VERSION 5.8 ;
BUSBITCHARS "[]" ;
DIVIDERCHAR "/" ;
UNITS
    DATABASE MICRONS 1000 ;
END UNITS

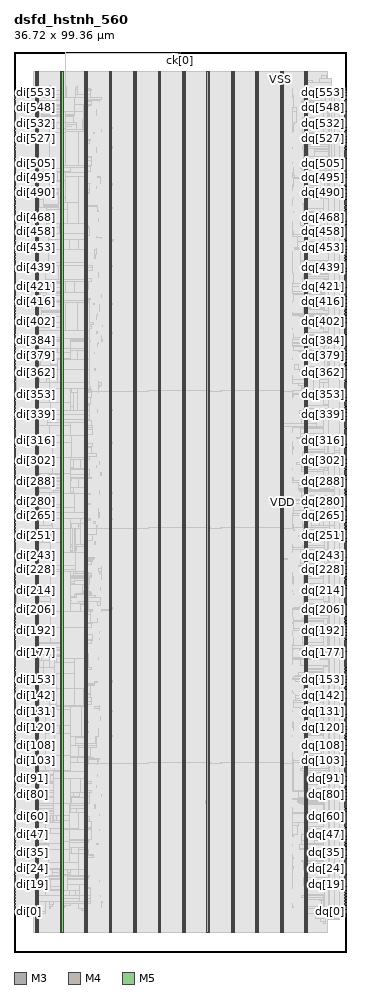
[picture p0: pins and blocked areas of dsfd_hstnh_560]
MACRO dsfd_hstnh_560
  FOREIGN dsfd_hstnh_560 0 0 ;
  CLASS BLOCK ;
  SIZE 36.72 BY 99.36 ;
  PIN ck[0]
    DIRECTION INPUT ;
    USE SIGNAL ;
    PORT
      LAYER M3 ;
        RECT  18.36 99.216 18.378 99.36 ;
    END
    PORT
      LAYER M3 ;
        RECT  18.18 99.193 18.378 99.228 ;
    END
  END ck[0]
  PIN di[0]
    DIRECTION INPUT ;
    USE SIGNAL ;
    PORT
      LAYER M4 ;
        RECT  0 4.416 0.192 4.44 ;
    END
  END di[0]
  PIN di[100]
    DIRECTION INPUT ;
    USE SIGNAL ;
    PORT
      LAYER M4 ;
        RECT  0 20.592 0.192 20.616 ;
    END
  END di[100]
  PIN di[101]
    DIRECTION INPUT ;
    USE SIGNAL ;
    PORT
      LAYER M4 ;
        RECT  0 20.784 0.192 20.808 ;
    END
  END di[101]
  PIN di[102]
    DIRECTION INPUT ;
    USE SIGNAL ;
    PORT
      LAYER M4 ;
        RECT  0 20.928 0.192 20.952 ;
    END
  END di[102]
  PIN di[103]
    DIRECTION INPUT ;
    USE SIGNAL ;
    PORT
      LAYER M4 ;
        RECT  0 21.12 0.192 21.144 ;
    END
  END di[103]
  PIN di[104]
    DIRECTION INPUT ;
    USE SIGNAL ;
    PORT
      LAYER M4 ;
        RECT  0 21.264 0.192 21.288 ;
    END
  END di[104]
  PIN di[105]
    DIRECTION INPUT ;
    USE SIGNAL ;
    PORT
      LAYER M4 ;
        RECT  0 21.408 0.192 21.432 ;
    END
  END di[105]
  PIN di[106]
    DIRECTION INPUT ;
    USE SIGNAL ;
    PORT
      LAYER M4 ;
        RECT  0 21.6 0.192 21.624 ;
    END
  END di[106]
  PIN di[107]
    DIRECTION INPUT ;
    USE SIGNAL ;
    PORT
      LAYER M4 ;
        RECT  0 21.744 0.192 21.768 ;
    END
  END di[107]
  PIN di[108]
    DIRECTION INPUT ;
    USE SIGNAL ;
    PORT
      LAYER M4 ;
        RECT  0 21.888 0.192 21.912 ;
    END
  END di[108]
  PIN di[109]
    DIRECTION INPUT ;
    USE SIGNAL ;
    PORT
      LAYER M4 ;
        RECT  0 22.08 0.192 22.104 ;
    END
  END di[109]
  PIN di[10]
    DIRECTION INPUT ;
    USE SIGNAL ;
    PORT
      LAYER M4 ;
        RECT  0 6.048 0.192 6.072 ;
    END
  END di[10]
  PIN di[110]
    DIRECTION INPUT ;
    USE SIGNAL ;
    PORT
      LAYER M4 ;
        RECT  0 22.224 0.192 22.248 ;
    END
  END di[110]
  PIN di[111]
    DIRECTION INPUT ;
    USE SIGNAL ;
    PORT
      LAYER M4 ;
        RECT  0 22.416 0.192 22.44 ;
    END
  END di[111]
  PIN di[112]
    DIRECTION INPUT ;
    USE SIGNAL ;
    PORT
      LAYER M4 ;
        RECT  0 22.56 0.192 22.584 ;
    END
  END di[112]
  PIN di[113]
    DIRECTION INPUT ;
    USE SIGNAL ;
    PORT
      LAYER M4 ;
        RECT  0 22.704 0.192 22.728 ;
    END
  END di[113]
  PIN di[114]
    DIRECTION INPUT ;
    USE SIGNAL ;
    PORT
      LAYER M4 ;
        RECT  0 22.896 0.192 22.92 ;
    END
  END di[114]
  PIN di[115]
    DIRECTION INPUT ;
    USE SIGNAL ;
    PORT
      LAYER M4 ;
        RECT  0 23.04 0.192 23.064 ;
    END
  END di[115]
  PIN di[116]
    DIRECTION INPUT ;
    USE SIGNAL ;
    PORT
      LAYER M4 ;
        RECT  0 23.184 0.192 23.208 ;
    END
  END di[116]
  PIN di[117]
    DIRECTION INPUT ;
    USE SIGNAL ;
    PORT
      LAYER M4 ;
        RECT  0 23.376 0.192 23.4 ;
    END
  END di[117]
  PIN di[118]
    DIRECTION INPUT ;
    USE SIGNAL ;
    PORT
      LAYER M4 ;
        RECT  0 23.52 0.192 23.544 ;
    END
  END di[118]
  PIN di[119]
    DIRECTION INPUT ;
    USE SIGNAL ;
    PORT
      LAYER M4 ;
        RECT  0 23.712 0.192 23.736 ;
    END
  END di[119]
  PIN di[11]
    DIRECTION INPUT ;
    USE SIGNAL ;
    PORT
      LAYER M4 ;
        RECT  0 6.192 0.192 6.216 ;
    END
  END di[11]
  PIN di[120]
    DIRECTION INPUT ;
    USE SIGNAL ;
    PORT
      LAYER M4 ;
        RECT  0 23.856 0.192 23.88 ;
    END
  END di[120]
  PIN di[121]
    DIRECTION INPUT ;
    USE SIGNAL ;
    PORT
      LAYER M4 ;
        RECT  0 24 0.192 24.024 ;
    END
  END di[121]
  PIN di[122]
    DIRECTION INPUT ;
    USE SIGNAL ;
    PORT
      LAYER M4 ;
        RECT  0 24.192 0.192 24.216 ;
    END
  END di[122]
  PIN di[123]
    DIRECTION INPUT ;
    USE SIGNAL ;
    PORT
      LAYER M4 ;
        RECT  0 24.336 0.192 24.36 ;
    END
  END di[123]
  PIN di[124]
    DIRECTION INPUT ;
    USE SIGNAL ;
    PORT
      LAYER M4 ;
        RECT  0 24.48 0.192 24.504 ;
    END
  END di[124]
  PIN di[125]
    DIRECTION INPUT ;
    USE SIGNAL ;
    PORT
      LAYER M4 ;
        RECT  0 24.672 0.192 24.696 ;
    END
  END di[125]
  PIN di[126]
    DIRECTION INPUT ;
    USE SIGNAL ;
    PORT
      LAYER M4 ;
        RECT  0 24.816 0.192 24.84 ;
    END
  END di[126]
  PIN di[127]
    DIRECTION INPUT ;
    USE SIGNAL ;
    PORT
      LAYER M4 ;
        RECT  0 25.008 0.192 25.032 ;
    END
  END di[127]
  PIN di[128]
    DIRECTION INPUT ;
    USE SIGNAL ;
    PORT
      LAYER M4 ;
        RECT  0 25.152 0.192 25.176 ;
    END
  END di[128]
  PIN di[129]
    DIRECTION INPUT ;
    USE SIGNAL ;
    PORT
      LAYER M4 ;
        RECT  0 25.296 0.192 25.32 ;
    END
  END di[129]
  PIN di[12]
    DIRECTION INPUT ;
    USE SIGNAL ;
    PORT
      LAYER M4 ;
        RECT  0 6.336 0.192 6.36 ;
    END
  END di[12]
  PIN di[130]
    DIRECTION INPUT ;
    USE SIGNAL ;
    PORT
      LAYER M4 ;
        RECT  0 25.488 0.192 25.512 ;
    END
  END di[130]
  PIN di[131]
    DIRECTION INPUT ;
    USE SIGNAL ;
    PORT
      LAYER M4 ;
        RECT  0 25.632 0.192 25.656 ;
    END
  END di[131]
  PIN di[132]
    DIRECTION INPUT ;
    USE SIGNAL ;
    PORT
      LAYER M4 ;
        RECT  0 25.776 0.192 25.8 ;
    END
  END di[132]
  PIN di[133]
    DIRECTION INPUT ;
    USE SIGNAL ;
    PORT
      LAYER M4 ;
        RECT  0 25.968 0.192 25.992 ;
    END
  END di[133]
  PIN di[134]
    DIRECTION INPUT ;
    USE SIGNAL ;
    PORT
      LAYER M4 ;
        RECT  0 26.112 0.192 26.136 ;
    END
  END di[134]
  PIN di[135]
    DIRECTION INPUT ;
    USE SIGNAL ;
    PORT
      LAYER M4 ;
        RECT  0 26.304 0.192 26.328 ;
    END
  END di[135]
  PIN di[136]
    DIRECTION INPUT ;
    USE SIGNAL ;
    PORT
      LAYER M4 ;
        RECT  0 26.448 0.192 26.472 ;
    END
  END di[136]
  PIN di[137]
    DIRECTION INPUT ;
    USE SIGNAL ;
    PORT
      LAYER M4 ;
        RECT  0 26.592 0.192 26.616 ;
    END
  END di[137]
  PIN di[138]
    DIRECTION INPUT ;
    USE SIGNAL ;
    PORT
      LAYER M4 ;
        RECT  0 26.784 0.192 26.808 ;
    END
  END di[138]
  PIN di[139]
    DIRECTION INPUT ;
    USE SIGNAL ;
    PORT
      LAYER M4 ;
        RECT  0 26.928 0.192 26.952 ;
    END
  END di[139]
  PIN di[13]
    DIRECTION INPUT ;
    USE SIGNAL ;
    PORT
      LAYER M4 ;
        RECT  0 6.528 0.192 6.552 ;
    END
  END di[13]
  PIN di[140]
    DIRECTION INPUT ;
    USE SIGNAL ;
    PORT
      LAYER M4 ;
        RECT  0 27.072 0.192 27.096 ;
    END
  END di[140]
  PIN di[141]
    DIRECTION INPUT ;
    USE SIGNAL ;
    PORT
      LAYER M4 ;
        RECT  0 27.264 0.192 27.288 ;
    END
  END di[141]
  PIN di[142]
    DIRECTION INPUT ;
    USE SIGNAL ;
    PORT
      LAYER M4 ;
        RECT  0 27.408 0.192 27.432 ;
    END
  END di[142]
  PIN di[143]
    DIRECTION INPUT ;
    USE SIGNAL ;
    PORT
      LAYER M4 ;
        RECT  0 27.6 0.192 27.624 ;
    END
  END di[143]
  PIN di[144]
    DIRECTION INPUT ;
    USE SIGNAL ;
    PORT
      LAYER M4 ;
        RECT  0 27.744 0.192 27.768 ;
    END
  END di[144]
  PIN di[145]
    DIRECTION INPUT ;
    USE SIGNAL ;
    PORT
      LAYER M4 ;
        RECT  0 27.888 0.192 27.912 ;
    END
  END di[145]
  PIN di[146]
    DIRECTION INPUT ;
    USE SIGNAL ;
    PORT
      LAYER M4 ;
        RECT  0 28.08 0.192 28.104 ;
    END
  END di[146]
  PIN di[147]
    DIRECTION INPUT ;
    USE SIGNAL ;
    PORT
      LAYER M4 ;
        RECT  0 28.224 0.192 28.248 ;
    END
  END di[147]
  PIN di[148]
    DIRECTION INPUT ;
    USE SIGNAL ;
    PORT
      LAYER M4 ;
        RECT  0 28.368 0.192 28.392 ;
    END
  END di[148]
  PIN di[149]
    DIRECTION INPUT ;
    USE SIGNAL ;
    PORT
      LAYER M4 ;
        RECT  0 28.56 0.192 28.584 ;
    END
  END di[149]
  PIN di[14]
    DIRECTION INPUT ;
    USE SIGNAL ;
    PORT
      LAYER M4 ;
        RECT  0 6.672 0.192 6.696 ;
    END
  END di[14]
  PIN di[150]
    DIRECTION INPUT ;
    USE SIGNAL ;
    PORT
      LAYER M4 ;
        RECT  0 28.704 0.192 28.728 ;
    END
  END di[150]
  PIN di[151]
    DIRECTION INPUT ;
    USE SIGNAL ;
    PORT
      LAYER M4 ;
        RECT  0 28.896 0.192 28.92 ;
    END
  END di[151]
  PIN di[152]
    DIRECTION INPUT ;
    USE SIGNAL ;
    PORT
      LAYER M4 ;
        RECT  0 29.04 0.192 29.064 ;
    END
  END di[152]
  PIN di[153]
    DIRECTION INPUT ;
    USE SIGNAL ;
    PORT
      LAYER M4 ;
        RECT  0 29.184 0.192 29.208 ;
    END
  END di[153]
  PIN di[154]
    DIRECTION INPUT ;
    USE SIGNAL ;
    PORT
      LAYER M4 ;
        RECT  0 29.376 0.192 29.4 ;
    END
  END di[154]
  PIN di[155]
    DIRECTION INPUT ;
    USE SIGNAL ;
    PORT
      LAYER M4 ;
        RECT  0 29.52 0.192 29.544 ;
    END
  END di[155]
  PIN di[156]
    DIRECTION INPUT ;
    USE SIGNAL ;
    PORT
      LAYER M4 ;
        RECT  0 29.664 0.192 29.688 ;
    END
  END di[156]
  PIN di[157]
    DIRECTION INPUT ;
    USE SIGNAL ;
    PORT
      LAYER M4 ;
        RECT  0 29.856 0.192 29.88 ;
    END
  END di[157]
  PIN di[158]
    DIRECTION INPUT ;
    USE SIGNAL ;
    PORT
      LAYER M4 ;
        RECT  0 30 0.192 30.024 ;
    END
  END di[158]
  PIN di[159]
    DIRECTION INPUT ;
    USE SIGNAL ;
    PORT
      LAYER M4 ;
        RECT  0 30.192 0.192 30.216 ;
    END
  END di[159]
  PIN di[15]
    DIRECTION INPUT ;
    USE SIGNAL ;
    PORT
      LAYER M4 ;
        RECT  0 6.864 0.192 6.888 ;
    END
  END di[15]
  PIN di[160]
    DIRECTION INPUT ;
    USE SIGNAL ;
    PORT
      LAYER M4 ;
        RECT  0 30.336 0.192 30.36 ;
    END
  END di[160]
  PIN di[161]
    DIRECTION INPUT ;
    USE SIGNAL ;
    PORT
      LAYER M4 ;
        RECT  0 30.48 0.192 30.504 ;
    END
  END di[161]
  PIN di[162]
    DIRECTION INPUT ;
    USE SIGNAL ;
    PORT
      LAYER M4 ;
        RECT  0 30.672 0.192 30.696 ;
    END
  END di[162]
  PIN di[163]
    DIRECTION INPUT ;
    USE SIGNAL ;
    PORT
      LAYER M4 ;
        RECT  0 30.816 0.192 30.84 ;
    END
  END di[163]
  PIN di[164]
    DIRECTION INPUT ;
    USE SIGNAL ;
    PORT
      LAYER M4 ;
        RECT  0 30.96 0.192 30.984 ;
    END
  END di[164]
  PIN di[165]
    DIRECTION INPUT ;
    USE SIGNAL ;
    PORT
      LAYER M4 ;
        RECT  0 31.152 0.192 31.176 ;
    END
  END di[165]
  PIN di[166]
    DIRECTION INPUT ;
    USE SIGNAL ;
    PORT
      LAYER M4 ;
        RECT  0 31.296 0.192 31.32 ;
    END
  END di[166]
  PIN di[167]
    DIRECTION INPUT ;
    USE SIGNAL ;
    PORT
      LAYER M4 ;
        RECT  0 31.488 0.192 31.512 ;
    END
  END di[167]
  PIN di[168]
    DIRECTION INPUT ;
    USE SIGNAL ;
    PORT
      LAYER M4 ;
        RECT  0 31.632 0.192 31.656 ;
    END
  END di[168]
  PIN di[169]
    DIRECTION INPUT ;
    USE SIGNAL ;
    PORT
      LAYER M4 ;
        RECT  0 31.776 0.192 31.8 ;
    END
  END di[169]
  PIN di[16]
    DIRECTION INPUT ;
    USE SIGNAL ;
    PORT
      LAYER M4 ;
        RECT  0 7.008 0.192 7.032 ;
    END
  END di[16]
  PIN di[170]
    DIRECTION INPUT ;
    USE SIGNAL ;
    PORT
      LAYER M4 ;
        RECT  0 31.968 0.192 31.992 ;
    END
  END di[170]
  PIN di[171]
    DIRECTION INPUT ;
    USE SIGNAL ;
    PORT
      LAYER M4 ;
        RECT  0 32.112 0.192 32.136 ;
    END
  END di[171]
  PIN di[172]
    DIRECTION INPUT ;
    USE SIGNAL ;
    PORT
      LAYER M4 ;
        RECT  0 32.256 0.192 32.28 ;
    END
  END di[172]
  PIN di[173]
    DIRECTION INPUT ;
    USE SIGNAL ;
    PORT
      LAYER M4 ;
        RECT  0 32.448 0.192 32.472 ;
    END
  END di[173]
  PIN di[174]
    DIRECTION INPUT ;
    USE SIGNAL ;
    PORT
      LAYER M4 ;
        RECT  0 32.592 0.192 32.616 ;
    END
  END di[174]
  PIN di[175]
    DIRECTION INPUT ;
    USE SIGNAL ;
    PORT
      LAYER M4 ;
        RECT  0 32.784 0.192 32.808 ;
    END
  END di[175]
  PIN di[176]
    DIRECTION INPUT ;
    USE SIGNAL ;
    PORT
      LAYER M4 ;
        RECT  0 32.928 0.192 32.952 ;
    END
  END di[176]
  PIN di[177]
    DIRECTION INPUT ;
    USE SIGNAL ;
    PORT
      LAYER M4 ;
        RECT  0 33.072 0.192 33.096 ;
    END
  END di[177]
  PIN di[178]
    DIRECTION INPUT ;
    USE SIGNAL ;
    PORT
      LAYER M4 ;
        RECT  0 33.264 0.192 33.288 ;
    END
  END di[178]
  PIN di[179]
    DIRECTION INPUT ;
    USE SIGNAL ;
    PORT
      LAYER M4 ;
        RECT  0 33.408 0.192 33.432 ;
    END
  END di[179]
  PIN di[17]
    DIRECTION INPUT ;
    USE SIGNAL ;
    PORT
      LAYER M4 ;
        RECT  0 7.152 0.192 7.176 ;
    END
  END di[17]
  PIN di[180]
    DIRECTION INPUT ;
    USE SIGNAL ;
    PORT
      LAYER M4 ;
        RECT  0 33.552 0.192 33.576 ;
    END
  END di[180]
  PIN di[181]
    DIRECTION INPUT ;
    USE SIGNAL ;
    PORT
      LAYER M4 ;
        RECT  0 33.744 0.192 33.768 ;
    END
  END di[181]
  PIN di[182]
    DIRECTION INPUT ;
    USE SIGNAL ;
    PORT
      LAYER M4 ;
        RECT  0 33.888 0.192 33.912 ;
    END
  END di[182]
  PIN di[183]
    DIRECTION INPUT ;
    USE SIGNAL ;
    PORT
      LAYER M4 ;
        RECT  0 34.08 0.192 34.104 ;
    END
  END di[183]
  PIN di[184]
    DIRECTION INPUT ;
    USE SIGNAL ;
    PORT
      LAYER M4 ;
        RECT  0 34.224 0.192 34.248 ;
    END
  END di[184]
  PIN di[185]
    DIRECTION INPUT ;
    USE SIGNAL ;
    PORT
      LAYER M4 ;
        RECT  0 34.368 0.192 34.392 ;
    END
  END di[185]
  PIN di[186]
    DIRECTION INPUT ;
    USE SIGNAL ;
    PORT
      LAYER M4 ;
        RECT  0 34.56 0.192 34.584 ;
    END
  END di[186]
  PIN di[187]
    DIRECTION INPUT ;
    USE SIGNAL ;
    PORT
      LAYER M4 ;
        RECT  0 34.704 0.192 34.728 ;
    END
  END di[187]
  PIN di[188]
    DIRECTION INPUT ;
    USE SIGNAL ;
    PORT
      LAYER M4 ;
        RECT  0 34.848 0.192 34.872 ;
    END
  END di[188]
  PIN di[189]
    DIRECTION INPUT ;
    USE SIGNAL ;
    PORT
      LAYER M4 ;
        RECT  0 35.04 0.192 35.064 ;
    END
  END di[189]
  PIN di[18]
    DIRECTION INPUT ;
    USE SIGNAL ;
    PORT
      LAYER M4 ;
        RECT  0 7.344 0.192 7.368 ;
    END
  END di[18]
  PIN di[190]
    DIRECTION INPUT ;
    USE SIGNAL ;
    PORT
      LAYER M4 ;
        RECT  0 35.184 0.192 35.208 ;
    END
  END di[190]
  PIN di[191]
    DIRECTION INPUT ;
    USE SIGNAL ;
    PORT
      LAYER M4 ;
        RECT  0 35.376 0.192 35.4 ;
    END
  END di[191]
  PIN di[192]
    DIRECTION INPUT ;
    USE SIGNAL ;
    PORT
      LAYER M4 ;
        RECT  0 35.52 0.192 35.544 ;
    END
  END di[192]
  PIN di[193]
    DIRECTION INPUT ;
    USE SIGNAL ;
    PORT
      LAYER M4 ;
        RECT  0 35.664 0.192 35.688 ;
    END
  END di[193]
  PIN di[194]
    DIRECTION INPUT ;
    USE SIGNAL ;
    PORT
      LAYER M4 ;
        RECT  0 35.856 0.192 35.88 ;
    END
  END di[194]
  PIN di[195]
    DIRECTION INPUT ;
    USE SIGNAL ;
    PORT
      LAYER M4 ;
        RECT  0 36 0.192 36.024 ;
    END
  END di[195]
  PIN di[196]
    DIRECTION INPUT ;
    USE SIGNAL ;
    PORT
      LAYER M4 ;
        RECT  0 36.144 0.192 36.168 ;
    END
  END di[196]
  PIN di[197]
    DIRECTION INPUT ;
    USE SIGNAL ;
    PORT
      LAYER M4 ;
        RECT  0 36.336 0.192 36.36 ;
    END
  END di[197]
  PIN di[198]
    DIRECTION INPUT ;
    USE SIGNAL ;
    PORT
      LAYER M4 ;
        RECT  0 36.48 0.192 36.504 ;
    END
  END di[198]
  PIN di[199]
    DIRECTION INPUT ;
    USE SIGNAL ;
    PORT
      LAYER M4 ;
        RECT  0 36.672 0.192 36.696 ;
    END
  END di[199]
  PIN di[19]
    DIRECTION INPUT ;
    USE SIGNAL ;
    PORT
      LAYER M4 ;
        RECT  0 7.488 0.192 7.512 ;
    END
  END di[19]
  PIN di[1]
    DIRECTION INPUT ;
    USE SIGNAL ;
    PORT
      LAYER M4 ;
        RECT  0 4.56 0.192 4.584 ;
    END
  END di[1]
  PIN di[200]
    DIRECTION INPUT ;
    USE SIGNAL ;
    PORT
      LAYER M4 ;
        RECT  0 36.816 0.192 36.84 ;
    END
  END di[200]
  PIN di[201]
    DIRECTION INPUT ;
    USE SIGNAL ;
    PORT
      LAYER M4 ;
        RECT  0 36.96 0.192 36.984 ;
    END
  END di[201]
  PIN di[202]
    DIRECTION INPUT ;
    USE SIGNAL ;
    PORT
      LAYER M4 ;
        RECT  0 37.152 0.192 37.176 ;
    END
  END di[202]
  PIN di[203]
    DIRECTION INPUT ;
    USE SIGNAL ;
    PORT
      LAYER M4 ;
        RECT  0 37.296 0.192 37.32 ;
    END
  END di[203]
  PIN di[204]
    DIRECTION INPUT ;
    USE SIGNAL ;
    PORT
      LAYER M4 ;
        RECT  0 37.44 0.192 37.464 ;
    END
  END di[204]
  PIN di[205]
    DIRECTION INPUT ;
    USE SIGNAL ;
    PORT
      LAYER M4 ;
        RECT  0 37.632 0.192 37.656 ;
    END
  END di[205]
  PIN di[206]
    DIRECTION INPUT ;
    USE SIGNAL ;
    PORT
      LAYER M4 ;
        RECT  0 37.776 0.192 37.8 ;
    END
  END di[206]
  PIN di[207]
    DIRECTION INPUT ;
    USE SIGNAL ;
    PORT
      LAYER M4 ;
        RECT  0 37.968 0.192 37.992 ;
    END
  END di[207]
  PIN di[208]
    DIRECTION INPUT ;
    USE SIGNAL ;
    PORT
      LAYER M4 ;
        RECT  0 38.112 0.192 38.136 ;
    END
  END di[208]
  PIN di[209]
    DIRECTION INPUT ;
    USE SIGNAL ;
    PORT
      LAYER M4 ;
        RECT  0 38.256 0.192 38.28 ;
    END
  END di[209]
  PIN di[20]
    DIRECTION INPUT ;
    USE SIGNAL ;
    PORT
      LAYER M4 ;
        RECT  0 7.632 0.192 7.656 ;
    END
  END di[20]
  PIN di[210]
    DIRECTION INPUT ;
    USE SIGNAL ;
    PORT
      LAYER M4 ;
        RECT  0 38.448 0.192 38.472 ;
    END
  END di[210]
  PIN di[211]
    DIRECTION INPUT ;
    USE SIGNAL ;
    PORT
      LAYER M4 ;
        RECT  0 38.592 0.192 38.616 ;
    END
  END di[211]
  PIN di[212]
    DIRECTION INPUT ;
    USE SIGNAL ;
    PORT
      LAYER M4 ;
        RECT  0 38.736 0.192 38.76 ;
    END
  END di[212]
  PIN di[213]
    DIRECTION INPUT ;
    USE SIGNAL ;
    PORT
      LAYER M4 ;
        RECT  0 38.928 0.192 38.952 ;
    END
  END di[213]
  PIN di[214]
    DIRECTION INPUT ;
    USE SIGNAL ;
    PORT
      LAYER M4 ;
        RECT  0 39.072 0.192 39.096 ;
    END
  END di[214]
  PIN di[215]
    DIRECTION INPUT ;
    USE SIGNAL ;
    PORT
      LAYER M4 ;
        RECT  0 39.264 0.192 39.288 ;
    END
  END di[215]
  PIN di[216]
    DIRECTION INPUT ;
    USE SIGNAL ;
    PORT
      LAYER M4 ;
        RECT  0 39.408 0.192 39.432 ;
    END
  END di[216]
  PIN di[217]
    DIRECTION INPUT ;
    USE SIGNAL ;
    PORT
      LAYER M4 ;
        RECT  0 39.552 0.192 39.576 ;
    END
  END di[217]
  PIN di[218]
    DIRECTION INPUT ;
    USE SIGNAL ;
    PORT
      LAYER M4 ;
        RECT  0 39.744 0.192 39.768 ;
    END
  END di[218]
  PIN di[219]
    DIRECTION INPUT ;
    USE SIGNAL ;
    PORT
      LAYER M4 ;
        RECT  0 39.888 0.192 39.912 ;
    END
  END di[219]
  PIN di[21]
    DIRECTION INPUT ;
    USE SIGNAL ;
    PORT
      LAYER M4 ;
        RECT  0 7.824 0.192 7.848 ;
    END
  END di[21]
  PIN di[220]
    DIRECTION INPUT ;
    USE SIGNAL ;
    PORT
      LAYER M4 ;
        RECT  0 40.032 0.192 40.056 ;
    END
  END di[220]
  PIN di[221]
    DIRECTION INPUT ;
    USE SIGNAL ;
    PORT
      LAYER M4 ;
        RECT  0 40.224 0.192 40.248 ;
    END
  END di[221]
  PIN di[222]
    DIRECTION INPUT ;
    USE SIGNAL ;
    PORT
      LAYER M4 ;
        RECT  0 40.368 0.192 40.392 ;
    END
  END di[222]
  PIN di[223]
    DIRECTION INPUT ;
    USE SIGNAL ;
    PORT
      LAYER M4 ;
        RECT  0 40.56 0.192 40.584 ;
    END
  END di[223]
  PIN di[224]
    DIRECTION INPUT ;
    USE SIGNAL ;
    PORT
      LAYER M4 ;
        RECT  0 40.704 0.192 40.728 ;
    END
  END di[224]
  PIN di[225]
    DIRECTION INPUT ;
    USE SIGNAL ;
    PORT
      LAYER M4 ;
        RECT  0 40.848 0.192 40.872 ;
    END
  END di[225]
  PIN di[226]
    DIRECTION INPUT ;
    USE SIGNAL ;
    PORT
      LAYER M4 ;
        RECT  0 41.04 0.192 41.064 ;
    END
  END di[226]
  PIN di[227]
    DIRECTION INPUT ;
    USE SIGNAL ;
    PORT
      LAYER M4 ;
        RECT  0 41.184 0.192 41.208 ;
    END
  END di[227]
  PIN di[228]
    DIRECTION INPUT ;
    USE SIGNAL ;
    PORT
      LAYER M4 ;
        RECT  0 41.328 0.192 41.352 ;
    END
  END di[228]
  PIN di[229]
    DIRECTION INPUT ;
    USE SIGNAL ;
    PORT
      LAYER M4 ;
        RECT  0 41.52 0.192 41.544 ;
    END
  END di[229]
  PIN di[22]
    DIRECTION INPUT ;
    USE SIGNAL ;
    PORT
      LAYER M4 ;
        RECT  0 7.968 0.192 7.992 ;
    END
  END di[22]
  PIN di[230]
    DIRECTION INPUT ;
    USE SIGNAL ;
    PORT
      LAYER M4 ;
        RECT  0 41.664 0.192 41.688 ;
    END
  END di[230]
  PIN di[231]
    DIRECTION INPUT ;
    USE SIGNAL ;
    PORT
      LAYER M4 ;
        RECT  0 41.856 0.192 41.88 ;
    END
  END di[231]
  PIN di[232]
    DIRECTION INPUT ;
    USE SIGNAL ;
    PORT
      LAYER M4 ;
        RECT  0 42 0.192 42.024 ;
    END
  END di[232]
  PIN di[233]
    DIRECTION INPUT ;
    USE SIGNAL ;
    PORT
      LAYER M4 ;
        RECT  0 42.144 0.192 42.168 ;
    END
  END di[233]
  PIN di[234]
    DIRECTION INPUT ;
    USE SIGNAL ;
    PORT
      LAYER M4 ;
        RECT  0 42.336 0.192 42.36 ;
    END
  END di[234]
  PIN di[235]
    DIRECTION INPUT ;
    USE SIGNAL ;
    PORT
      LAYER M4 ;
        RECT  0 42.48 0.192 42.504 ;
    END
  END di[235]
  PIN di[236]
    DIRECTION INPUT ;
    USE SIGNAL ;
    PORT
      LAYER M4 ;
        RECT  0 42.624 0.192 42.648 ;
    END
  END di[236]
  PIN di[237]
    DIRECTION INPUT ;
    USE SIGNAL ;
    PORT
      LAYER M4 ;
        RECT  0 42.816 0.192 42.84 ;
    END
  END di[237]
  PIN di[238]
    DIRECTION INPUT ;
    USE SIGNAL ;
    PORT
      LAYER M4 ;
        RECT  0 42.96 0.192 42.984 ;
    END
  END di[238]
  PIN di[239]
    DIRECTION INPUT ;
    USE SIGNAL ;
    PORT
      LAYER M4 ;
        RECT  0 43.152 0.192 43.176 ;
    END
  END di[239]
  PIN di[23]
    DIRECTION INPUT ;
    USE SIGNAL ;
    PORT
      LAYER M4 ;
        RECT  0 8.16 0.192 8.184 ;
    END
  END di[23]
  PIN di[240]
    DIRECTION INPUT ;
    USE SIGNAL ;
    PORT
      LAYER M4 ;
        RECT  0 43.296 0.192 43.32 ;
    END
  END di[240]
  PIN di[241]
    DIRECTION INPUT ;
    USE SIGNAL ;
    PORT
      LAYER M4 ;
        RECT  0 43.44 0.192 43.464 ;
    END
  END di[241]
  PIN di[242]
    DIRECTION INPUT ;
    USE SIGNAL ;
    PORT
      LAYER M4 ;
        RECT  0 43.632 0.192 43.656 ;
    END
  END di[242]
  PIN di[243]
    DIRECTION INPUT ;
    USE SIGNAL ;
    PORT
      LAYER M4 ;
        RECT  0 43.776 0.192 43.8 ;
    END
  END di[243]
  PIN di[244]
    DIRECTION INPUT ;
    USE SIGNAL ;
    PORT
      LAYER M4 ;
        RECT  0 43.92 0.192 43.944 ;
    END
  END di[244]
  PIN di[245]
    DIRECTION INPUT ;
    USE SIGNAL ;
    PORT
      LAYER M4 ;
        RECT  0 44.112 0.192 44.136 ;
    END
  END di[245]
  PIN di[246]
    DIRECTION INPUT ;
    USE SIGNAL ;
    PORT
      LAYER M4 ;
        RECT  0 44.256 0.192 44.28 ;
    END
  END di[246]
  PIN di[247]
    DIRECTION INPUT ;
    USE SIGNAL ;
    PORT
      LAYER M4 ;
        RECT  0 44.448 0.192 44.472 ;
    END
  END di[247]
  PIN di[248]
    DIRECTION INPUT ;
    USE SIGNAL ;
    PORT
      LAYER M4 ;
        RECT  0 44.592 0.192 44.616 ;
    END
  END di[248]
  PIN di[249]
    DIRECTION INPUT ;
    USE SIGNAL ;
    PORT
      LAYER M4 ;
        RECT  0 44.736 0.192 44.76 ;
    END
  END di[249]
  PIN di[24]
    DIRECTION INPUT ;
    USE SIGNAL ;
    PORT
      LAYER M4 ;
        RECT  0 8.304 0.192 8.328 ;
    END
  END di[24]
  PIN di[250]
    DIRECTION INPUT ;
    USE SIGNAL ;
    PORT
      LAYER M4 ;
        RECT  0 44.928 0.192 44.952 ;
    END
  END di[250]
  PIN di[251]
    DIRECTION INPUT ;
    USE SIGNAL ;
    PORT
      LAYER M4 ;
        RECT  0 45.072 0.192 45.096 ;
    END
  END di[251]
  PIN di[252]
    DIRECTION INPUT ;
    USE SIGNAL ;
    PORT
      LAYER M4 ;
        RECT  0 45.216 0.192 45.24 ;
    END
  END di[252]
  PIN di[253]
    DIRECTION INPUT ;
    USE SIGNAL ;
    PORT
      LAYER M4 ;
        RECT  0 45.408 0.192 45.432 ;
    END
  END di[253]
  PIN di[254]
    DIRECTION INPUT ;
    USE SIGNAL ;
    PORT
      LAYER M4 ;
        RECT  0 45.552 0.192 45.576 ;
    END
  END di[254]
  PIN di[255]
    DIRECTION INPUT ;
    USE SIGNAL ;
    PORT
      LAYER M4 ;
        RECT  0 45.744 0.192 45.768 ;
    END
  END di[255]
  PIN di[256]
    DIRECTION INPUT ;
    USE SIGNAL ;
    PORT
      LAYER M4 ;
        RECT  0 45.888 0.192 45.912 ;
    END
  END di[256]
  PIN di[257]
    DIRECTION INPUT ;
    USE SIGNAL ;
    PORT
      LAYER M4 ;
        RECT  0 46.032 0.192 46.056 ;
    END
  END di[257]
  PIN di[258]
    DIRECTION INPUT ;
    USE SIGNAL ;
    PORT
      LAYER M4 ;
        RECT  0 46.224 0.192 46.248 ;
    END
  END di[258]
  PIN di[259]
    DIRECTION INPUT ;
    USE SIGNAL ;
    PORT
      LAYER M4 ;
        RECT  0 46.368 0.192 46.392 ;
    END
  END di[259]
  PIN di[25]
    DIRECTION INPUT ;
    USE SIGNAL ;
    PORT
      LAYER M4 ;
        RECT  0 8.448 0.192 8.472 ;
    END
  END di[25]
  PIN di[260]
    DIRECTION INPUT ;
    USE SIGNAL ;
    PORT
      LAYER M4 ;
        RECT  0 46.512 0.192 46.536 ;
    END
  END di[260]
  PIN di[261]
    DIRECTION INPUT ;
    USE SIGNAL ;
    PORT
      LAYER M4 ;
        RECT  0 46.704 0.192 46.728 ;
    END
  END di[261]
  PIN di[262]
    DIRECTION INPUT ;
    USE SIGNAL ;
    PORT
      LAYER M4 ;
        RECT  0 46.848 0.192 46.872 ;
    END
  END di[262]
  PIN di[263]
    DIRECTION INPUT ;
    USE SIGNAL ;
    PORT
      LAYER M4 ;
        RECT  0 47.04 0.192 47.064 ;
    END
  END di[263]
  PIN di[264]
    DIRECTION INPUT ;
    USE SIGNAL ;
    PORT
      LAYER M4 ;
        RECT  0 47.184 0.192 47.208 ;
    END
  END di[264]
  PIN di[265]
    DIRECTION INPUT ;
    USE SIGNAL ;
    PORT
      LAYER M4 ;
        RECT  0 47.328 0.192 47.352 ;
    END
  END di[265]
  PIN di[266]
    DIRECTION INPUT ;
    USE SIGNAL ;
    PORT
      LAYER M4 ;
        RECT  0 47.52 0.192 47.544 ;
    END
  END di[266]
  PIN di[267]
    DIRECTION INPUT ;
    USE SIGNAL ;
    PORT
      LAYER M4 ;
        RECT  0 47.664 0.192 47.688 ;
    END
  END di[267]
  PIN di[268]
    DIRECTION INPUT ;
    USE SIGNAL ;
    PORT
      LAYER M4 ;
        RECT  0 47.808 0.192 47.832 ;
    END
  END di[268]
  PIN di[269]
    DIRECTION INPUT ;
    USE SIGNAL ;
    PORT
      LAYER M4 ;
        RECT  0 48 0.192 48.024 ;
    END
  END di[269]
  PIN di[26]
    DIRECTION INPUT ;
    USE SIGNAL ;
    PORT
      LAYER M4 ;
        RECT  0 8.64 0.192 8.664 ;
    END
  END di[26]
  PIN di[270]
    DIRECTION INPUT ;
    USE SIGNAL ;
    PORT
      LAYER M4 ;
        RECT  0 48.144 0.192 48.168 ;
    END
  END di[270]
  PIN di[271]
    DIRECTION INPUT ;
    USE SIGNAL ;
    PORT
      LAYER M4 ;
        RECT  0 48.336 0.192 48.36 ;
    END
  END di[271]
  PIN di[272]
    DIRECTION INPUT ;
    USE SIGNAL ;
    PORT
      LAYER M4 ;
        RECT  0 48.48 0.192 48.504 ;
    END
  END di[272]
  PIN di[273]
    DIRECTION INPUT ;
    USE SIGNAL ;
    PORT
      LAYER M4 ;
        RECT  0 48.624 0.192 48.648 ;
    END
  END di[273]
  PIN di[274]
    DIRECTION INPUT ;
    USE SIGNAL ;
    PORT
      LAYER M4 ;
        RECT  0 48.816 0.192 48.84 ;
    END
  END di[274]
  PIN di[275]
    DIRECTION INPUT ;
    USE SIGNAL ;
    PORT
      LAYER M4 ;
        RECT  0 48.96 0.192 48.984 ;
    END
  END di[275]
  PIN di[276]
    DIRECTION INPUT ;
    USE SIGNAL ;
    PORT
      LAYER M4 ;
        RECT  0 49.104 0.192 49.128 ;
    END
  END di[276]
  PIN di[277]
    DIRECTION INPUT ;
    USE SIGNAL ;
    PORT
      LAYER M4 ;
        RECT  0 49.296 0.192 49.32 ;
    END
  END di[277]
  PIN di[278]
    DIRECTION INPUT ;
    USE SIGNAL ;
    PORT
      LAYER M4 ;
        RECT  0 49.44 0.192 49.464 ;
    END
  END di[278]
  PIN di[279]
    DIRECTION INPUT ;
    USE SIGNAL ;
    PORT
      LAYER M4 ;
        RECT  0 49.632 0.192 49.656 ;
    END
  END di[279]
  PIN di[27]
    DIRECTION INPUT ;
    USE SIGNAL ;
    PORT
      LAYER M4 ;
        RECT  0 8.784 0.192 8.808 ;
    END
  END di[27]
  PIN di[280]
    DIRECTION INPUT ;
    USE SIGNAL ;
    PORT
      LAYER M4 ;
        RECT  0 49.776 0.192 49.8 ;
    END
  END di[280]
  PIN di[281]
    DIRECTION INPUT ;
    USE SIGNAL ;
    PORT
      LAYER M4 ;
        RECT  0 49.92 0.192 49.944 ;
    END
  END di[281]
  PIN di[282]
    DIRECTION INPUT ;
    USE SIGNAL ;
    PORT
      LAYER M4 ;
        RECT  0 50.112 0.192 50.136 ;
    END
  END di[282]
  PIN di[283]
    DIRECTION INPUT ;
    USE SIGNAL ;
    PORT
      LAYER M4 ;
        RECT  0 50.256 0.192 50.28 ;
    END
  END di[283]
  PIN di[284]
    DIRECTION INPUT ;
    USE SIGNAL ;
    PORT
      LAYER M4 ;
        RECT  0 50.4 0.192 50.424 ;
    END
  END di[284]
  PIN di[285]
    DIRECTION INPUT ;
    USE SIGNAL ;
    PORT
      LAYER M4 ;
        RECT  0 50.592 0.192 50.616 ;
    END
  END di[285]
  PIN di[286]
    DIRECTION INPUT ;
    USE SIGNAL ;
    PORT
      LAYER M4 ;
        RECT  0 50.736 0.192 50.76 ;
    END
  END di[286]
  PIN di[287]
    DIRECTION INPUT ;
    USE SIGNAL ;
    PORT
      LAYER M4 ;
        RECT  0 50.928 0.192 50.952 ;
    END
  END di[287]
  PIN di[288]
    DIRECTION INPUT ;
    USE SIGNAL ;
    PORT
      LAYER M4 ;
        RECT  0 51.072 0.192 51.096 ;
    END
  END di[288]
  PIN di[289]
    DIRECTION INPUT ;
    USE SIGNAL ;
    PORT
      LAYER M4 ;
        RECT  0 51.216 0.192 51.24 ;
    END
  END di[289]
  PIN di[28]
    DIRECTION INPUT ;
    USE SIGNAL ;
    PORT
      LAYER M4 ;
        RECT  0 8.928 0.192 8.952 ;
    END
  END di[28]
  PIN di[290]
    DIRECTION INPUT ;
    USE SIGNAL ;
    PORT
      LAYER M4 ;
        RECT  0 51.408 0.192 51.432 ;
    END
  END di[290]
  PIN di[291]
    DIRECTION INPUT ;
    USE SIGNAL ;
    PORT
      LAYER M4 ;
        RECT  0 51.552 0.192 51.576 ;
    END
  END di[291]
  PIN di[292]
    DIRECTION INPUT ;
    USE SIGNAL ;
    PORT
      LAYER M4 ;
        RECT  0 51.696 0.192 51.72 ;
    END
  END di[292]
  PIN di[293]
    DIRECTION INPUT ;
    USE SIGNAL ;
    PORT
      LAYER M4 ;
        RECT  0 51.888 0.192 51.912 ;
    END
  END di[293]
  PIN di[294]
    DIRECTION INPUT ;
    USE SIGNAL ;
    PORT
      LAYER M4 ;
        RECT  0 52.032 0.192 52.056 ;
    END
  END di[294]
  PIN di[295]
    DIRECTION INPUT ;
    USE SIGNAL ;
    PORT
      LAYER M4 ;
        RECT  0 52.224 0.192 52.248 ;
    END
  END di[295]
  PIN di[296]
    DIRECTION INPUT ;
    USE SIGNAL ;
    PORT
      LAYER M4 ;
        RECT  0 52.368 0.192 52.392 ;
    END
  END di[296]
  PIN di[297]
    DIRECTION INPUT ;
    USE SIGNAL ;
    PORT
      LAYER M4 ;
        RECT  0 52.512 0.192 52.536 ;
    END
  END di[297]
  PIN di[298]
    DIRECTION INPUT ;
    USE SIGNAL ;
    PORT
      LAYER M4 ;
        RECT  0 52.704 0.192 52.728 ;
    END
  END di[298]
  PIN di[299]
    DIRECTION INPUT ;
    USE SIGNAL ;
    PORT
      LAYER M4 ;
        RECT  0 52.848 0.192 52.872 ;
    END
  END di[299]
  PIN di[29]
    DIRECTION INPUT ;
    USE SIGNAL ;
    PORT
      LAYER M4 ;
        RECT  0 9.12 0.192 9.144 ;
    END
  END di[29]
  PIN di[2]
    DIRECTION INPUT ;
    USE SIGNAL ;
    PORT
      LAYER M4 ;
        RECT  0 4.752 0.192 4.776 ;
    END
  END di[2]
  PIN di[300]
    DIRECTION INPUT ;
    USE SIGNAL ;
    PORT
      LAYER M4 ;
        RECT  0 52.992 0.192 53.016 ;
    END
  END di[300]
  PIN di[301]
    DIRECTION INPUT ;
    USE SIGNAL ;
    PORT
      LAYER M4 ;
        RECT  0 53.184 0.192 53.208 ;
    END
  END di[301]
  PIN di[302]
    DIRECTION INPUT ;
    USE SIGNAL ;
    PORT
      LAYER M4 ;
        RECT  0 53.328 0.192 53.352 ;
    END
  END di[302]
  PIN di[303]
    DIRECTION INPUT ;
    USE SIGNAL ;
    PORT
      LAYER M4 ;
        RECT  0 53.52 0.192 53.544 ;
    END
  END di[303]
  PIN di[304]
    DIRECTION INPUT ;
    USE SIGNAL ;
    PORT
      LAYER M4 ;
        RECT  0 53.664 0.192 53.688 ;
    END
  END di[304]
  PIN di[305]
    DIRECTION INPUT ;
    USE SIGNAL ;
    PORT
      LAYER M4 ;
        RECT  0 53.808 0.192 53.832 ;
    END
  END di[305]
  PIN di[306]
    DIRECTION INPUT ;
    USE SIGNAL ;
    PORT
      LAYER M4 ;
        RECT  0 54 0.192 54.024 ;
    END
  END di[306]
  PIN di[307]
    DIRECTION INPUT ;
    USE SIGNAL ;
    PORT
      LAYER M4 ;
        RECT  0 54.144 0.192 54.168 ;
    END
  END di[307]
  PIN di[308]
    DIRECTION INPUT ;
    USE SIGNAL ;
    PORT
      LAYER M4 ;
        RECT  0 54.288 0.192 54.312 ;
    END
  END di[308]
  PIN di[309]
    DIRECTION INPUT ;
    USE SIGNAL ;
    PORT
      LAYER M4 ;
        RECT  0 54.48 0.192 54.504 ;
    END
  END di[309]
  PIN di[30]
    DIRECTION INPUT ;
    USE SIGNAL ;
    PORT
      LAYER M4 ;
        RECT  0 9.264 0.192 9.288 ;
    END
  END di[30]
  PIN di[310]
    DIRECTION INPUT ;
    USE SIGNAL ;
    PORT
      LAYER M4 ;
        RECT  0 54.624 0.192 54.648 ;
    END
  END di[310]
  PIN di[311]
    DIRECTION INPUT ;
    USE SIGNAL ;
    PORT
      LAYER M4 ;
        RECT  0 54.816 0.192 54.84 ;
    END
  END di[311]
  PIN di[312]
    DIRECTION INPUT ;
    USE SIGNAL ;
    PORT
      LAYER M4 ;
        RECT  0 54.96 0.192 54.984 ;
    END
  END di[312]
  PIN di[313]
    DIRECTION INPUT ;
    USE SIGNAL ;
    PORT
      LAYER M4 ;
        RECT  0 55.104 0.192 55.128 ;
    END
  END di[313]
  PIN di[314]
    DIRECTION INPUT ;
    USE SIGNAL ;
    PORT
      LAYER M4 ;
        RECT  0 55.296 0.192 55.32 ;
    END
  END di[314]
  PIN di[315]
    DIRECTION INPUT ;
    USE SIGNAL ;
    PORT
      LAYER M4 ;
        RECT  0 55.44 0.192 55.464 ;
    END
  END di[315]
  PIN di[316]
    DIRECTION INPUT ;
    USE SIGNAL ;
    PORT
      LAYER M4 ;
        RECT  0 55.584 0.192 55.608 ;
    END
  END di[316]
  PIN di[317]
    DIRECTION INPUT ;
    USE SIGNAL ;
    PORT
      LAYER M4 ;
        RECT  0 55.776 0.192 55.8 ;
    END
  END di[317]
  PIN di[318]
    DIRECTION INPUT ;
    USE SIGNAL ;
    PORT
      LAYER M4 ;
        RECT  0 55.92 0.192 55.944 ;
    END
  END di[318]
  PIN di[319]
    DIRECTION INPUT ;
    USE SIGNAL ;
    PORT
      LAYER M4 ;
        RECT  0 56.112 0.192 56.136 ;
    END
  END di[319]
  PIN di[31]
    DIRECTION INPUT ;
    USE SIGNAL ;
    PORT
      LAYER M4 ;
        RECT  0 9.456 0.192 9.48 ;
    END
  END di[31]
  PIN di[320]
    DIRECTION INPUT ;
    USE SIGNAL ;
    PORT
      LAYER M4 ;
        RECT  0 56.256 0.192 56.28 ;
    END
  END di[320]
  PIN di[321]
    DIRECTION INPUT ;
    USE SIGNAL ;
    PORT
      LAYER M4 ;
        RECT  0 56.4 0.192 56.424 ;
    END
  END di[321]
  PIN di[322]
    DIRECTION INPUT ;
    USE SIGNAL ;
    PORT
      LAYER M4 ;
        RECT  0 56.592 0.192 56.616 ;
    END
  END di[322]
  PIN di[323]
    DIRECTION INPUT ;
    USE SIGNAL ;
    PORT
      LAYER M4 ;
        RECT  0 56.736 0.192 56.76 ;
    END
  END di[323]
  PIN di[324]
    DIRECTION INPUT ;
    USE SIGNAL ;
    PORT
      LAYER M4 ;
        RECT  0 56.88 0.192 56.904 ;
    END
  END di[324]
  PIN di[325]
    DIRECTION INPUT ;
    USE SIGNAL ;
    PORT
      LAYER M4 ;
        RECT  0 57.072 0.192 57.096 ;
    END
  END di[325]
  PIN di[326]
    DIRECTION INPUT ;
    USE SIGNAL ;
    PORT
      LAYER M4 ;
        RECT  0 57.216 0.192 57.24 ;
    END
  END di[326]
  PIN di[327]
    DIRECTION INPUT ;
    USE SIGNAL ;
    PORT
      LAYER M4 ;
        RECT  0 57.408 0.192 57.432 ;
    END
  END di[327]
  PIN di[328]
    DIRECTION INPUT ;
    USE SIGNAL ;
    PORT
      LAYER M4 ;
        RECT  0 57.552 0.192 57.576 ;
    END
  END di[328]
  PIN di[329]
    DIRECTION INPUT ;
    USE SIGNAL ;
    PORT
      LAYER M4 ;
        RECT  0 57.696 0.192 57.72 ;
    END
  END di[329]
  PIN di[32]
    DIRECTION INPUT ;
    USE SIGNAL ;
    PORT
      LAYER M4 ;
        RECT  0 9.6 0.192 9.624 ;
    END
  END di[32]
  PIN di[330]
    DIRECTION INPUT ;
    USE SIGNAL ;
    PORT
      LAYER M4 ;
        RECT  0 57.888 0.192 57.912 ;
    END
  END di[330]
  PIN di[331]
    DIRECTION INPUT ;
    USE SIGNAL ;
    PORT
      LAYER M4 ;
        RECT  0 58.032 0.192 58.056 ;
    END
  END di[331]
  PIN di[332]
    DIRECTION INPUT ;
    USE SIGNAL ;
    PORT
      LAYER M4 ;
        RECT  0 58.176 0.192 58.2 ;
    END
  END di[332]
  PIN di[333]
    DIRECTION INPUT ;
    USE SIGNAL ;
    PORT
      LAYER M4 ;
        RECT  0 58.368 0.192 58.392 ;
    END
  END di[333]
  PIN di[334]
    DIRECTION INPUT ;
    USE SIGNAL ;
    PORT
      LAYER M4 ;
        RECT  0 58.512 0.192 58.536 ;
    END
  END di[334]
  PIN di[335]
    DIRECTION INPUT ;
    USE SIGNAL ;
    PORT
      LAYER M4 ;
        RECT  0 58.704 0.192 58.728 ;
    END
  END di[335]
  PIN di[336]
    DIRECTION INPUT ;
    USE SIGNAL ;
    PORT
      LAYER M4 ;
        RECT  0 58.848 0.192 58.872 ;
    END
  END di[336]
  PIN di[337]
    DIRECTION INPUT ;
    USE SIGNAL ;
    PORT
      LAYER M4 ;
        RECT  0 58.992 0.192 59.016 ;
    END
  END di[337]
  PIN di[338]
    DIRECTION INPUT ;
    USE SIGNAL ;
    PORT
      LAYER M4 ;
        RECT  0 59.184 0.192 59.208 ;
    END
  END di[338]
  PIN di[339]
    DIRECTION INPUT ;
    USE SIGNAL ;
    PORT
      LAYER M4 ;
        RECT  0 59.328 0.192 59.352 ;
    END
  END di[339]
  PIN di[33]
    DIRECTION INPUT ;
    USE SIGNAL ;
    PORT
      LAYER M4 ;
        RECT  0 9.744 0.192 9.768 ;
    END
  END di[33]
  PIN di[340]
    DIRECTION INPUT ;
    USE SIGNAL ;
    PORT
      LAYER M4 ;
        RECT  0 59.472 0.192 59.496 ;
    END
  END di[340]
  PIN di[341]
    DIRECTION INPUT ;
    USE SIGNAL ;
    PORT
      LAYER M4 ;
        RECT  0 59.664 0.192 59.688 ;
    END
  END di[341]
  PIN di[342]
    DIRECTION INPUT ;
    USE SIGNAL ;
    PORT
      LAYER M4 ;
        RECT  0 59.808 0.192 59.832 ;
    END
  END di[342]
  PIN di[343]
    DIRECTION INPUT ;
    USE SIGNAL ;
    PORT
      LAYER M4 ;
        RECT  0 60 0.192 60.024 ;
    END
  END di[343]
  PIN di[344]
    DIRECTION INPUT ;
    USE SIGNAL ;
    PORT
      LAYER M4 ;
        RECT  0 60.144 0.192 60.168 ;
    END
  END di[344]
  PIN di[345]
    DIRECTION INPUT ;
    USE SIGNAL ;
    PORT
      LAYER M4 ;
        RECT  0 60.288 0.192 60.312 ;
    END
  END di[345]
  PIN di[346]
    DIRECTION INPUT ;
    USE SIGNAL ;
    PORT
      LAYER M4 ;
        RECT  0 60.48 0.192 60.504 ;
    END
  END di[346]
  PIN di[347]
    DIRECTION INPUT ;
    USE SIGNAL ;
    PORT
      LAYER M4 ;
        RECT  0 60.624 0.192 60.648 ;
    END
  END di[347]
  PIN di[348]
    DIRECTION INPUT ;
    USE SIGNAL ;
    PORT
      LAYER M4 ;
        RECT  0 60.768 0.192 60.792 ;
    END
  END di[348]
  PIN di[349]
    DIRECTION INPUT ;
    USE SIGNAL ;
    PORT
      LAYER M4 ;
        RECT  0 60.96 0.192 60.984 ;
    END
  END di[349]
  PIN di[34]
    DIRECTION INPUT ;
    USE SIGNAL ;
    PORT
      LAYER M4 ;
        RECT  0 9.936 0.192 9.96 ;
    END
  END di[34]
  PIN di[350]
    DIRECTION INPUT ;
    USE SIGNAL ;
    PORT
      LAYER M4 ;
        RECT  0 61.104 0.192 61.128 ;
    END
  END di[350]
  PIN di[351]
    DIRECTION INPUT ;
    USE SIGNAL ;
    PORT
      LAYER M4 ;
        RECT  0 61.296 0.192 61.32 ;
    END
  END di[351]
  PIN di[352]
    DIRECTION INPUT ;
    USE SIGNAL ;
    PORT
      LAYER M4 ;
        RECT  0 61.44 0.192 61.464 ;
    END
  END di[352]
  PIN di[353]
    DIRECTION INPUT ;
    USE SIGNAL ;
    PORT
      LAYER M4 ;
        RECT  0 61.584 0.192 61.608 ;
    END
  END di[353]
  PIN di[354]
    DIRECTION INPUT ;
    USE SIGNAL ;
    PORT
      LAYER M4 ;
        RECT  0 61.776 0.192 61.8 ;
    END
  END di[354]
  PIN di[355]
    DIRECTION INPUT ;
    USE SIGNAL ;
    PORT
      LAYER M4 ;
        RECT  0 61.92 0.192 61.944 ;
    END
  END di[355]
  PIN di[356]
    DIRECTION INPUT ;
    USE SIGNAL ;
    PORT
      LAYER M4 ;
        RECT  0 62.064 0.192 62.088 ;
    END
  END di[356]
  PIN di[357]
    DIRECTION INPUT ;
    USE SIGNAL ;
    PORT
      LAYER M4 ;
        RECT  0 62.256 0.192 62.28 ;
    END
  END di[357]
  PIN di[358]
    DIRECTION INPUT ;
    USE SIGNAL ;
    PORT
      LAYER M4 ;
        RECT  0 62.4 0.192 62.424 ;
    END
  END di[358]
  PIN di[359]
    DIRECTION INPUT ;
    USE SIGNAL ;
    PORT
      LAYER M4 ;
        RECT  0 62.592 0.192 62.616 ;
    END
  END di[359]
  PIN di[35]
    DIRECTION INPUT ;
    USE SIGNAL ;
    PORT
      LAYER M4 ;
        RECT  0 10.08 0.192 10.104 ;
    END
  END di[35]
  PIN di[360]
    DIRECTION INPUT ;
    USE SIGNAL ;
    PORT
      LAYER M4 ;
        RECT  0 62.736 0.192 62.76 ;
    END
  END di[360]
  PIN di[361]
    DIRECTION INPUT ;
    USE SIGNAL ;
    PORT
      LAYER M4 ;
        RECT  0 62.88 0.192 62.904 ;
    END
  END di[361]
  PIN di[362]
    DIRECTION INPUT ;
    USE SIGNAL ;
    PORT
      LAYER M4 ;
        RECT  0 63.072 0.192 63.096 ;
    END
  END di[362]
  PIN di[363]
    DIRECTION INPUT ;
    USE SIGNAL ;
    PORT
      LAYER M4 ;
        RECT  0 63.216 0.192 63.24 ;
    END
  END di[363]
  PIN di[364]
    DIRECTION INPUT ;
    USE SIGNAL ;
    PORT
      LAYER M4 ;
        RECT  0 63.36 0.192 63.384 ;
    END
  END di[364]
  PIN di[365]
    DIRECTION INPUT ;
    USE SIGNAL ;
    PORT
      LAYER M4 ;
        RECT  0 63.552 0.192 63.576 ;
    END
  END di[365]
  PIN di[366]
    DIRECTION INPUT ;
    USE SIGNAL ;
    PORT
      LAYER M4 ;
        RECT  0 63.696 0.192 63.72 ;
    END
  END di[366]
  PIN di[367]
    DIRECTION INPUT ;
    USE SIGNAL ;
    PORT
      LAYER M4 ;
        RECT  0 63.888 0.192 63.912 ;
    END
  END di[367]
  PIN di[368]
    DIRECTION INPUT ;
    USE SIGNAL ;
    PORT
      LAYER M4 ;
        RECT  0 64.032 0.192 64.056 ;
    END
  END di[368]
  PIN di[369]
    DIRECTION INPUT ;
    USE SIGNAL ;
    PORT
      LAYER M4 ;
        RECT  0 64.176 0.192 64.2 ;
    END
  END di[369]
  PIN di[36]
    DIRECTION INPUT ;
    USE SIGNAL ;
    PORT
      LAYER M4 ;
        RECT  0 10.224 0.192 10.248 ;
    END
  END di[36]
  PIN di[370]
    DIRECTION INPUT ;
    USE SIGNAL ;
    PORT
      LAYER M4 ;
        RECT  0 64.368 0.192 64.392 ;
    END
  END di[370]
  PIN di[371]
    DIRECTION INPUT ;
    USE SIGNAL ;
    PORT
      LAYER M4 ;
        RECT  0 64.512 0.192 64.536 ;
    END
  END di[371]
  PIN di[372]
    DIRECTION INPUT ;
    USE SIGNAL ;
    PORT
      LAYER M4 ;
        RECT  0 64.656 0.192 64.68 ;
    END
  END di[372]
  PIN di[373]
    DIRECTION INPUT ;
    USE SIGNAL ;
    PORT
      LAYER M4 ;
        RECT  0 64.848 0.192 64.872 ;
    END
  END di[373]
  PIN di[374]
    DIRECTION INPUT ;
    USE SIGNAL ;
    PORT
      LAYER M4 ;
        RECT  0 64.992 0.192 65.016 ;
    END
  END di[374]
  PIN di[375]
    DIRECTION INPUT ;
    USE SIGNAL ;
    PORT
      LAYER M4 ;
        RECT  0 65.184 0.192 65.208 ;
    END
  END di[375]
  PIN di[376]
    DIRECTION INPUT ;
    USE SIGNAL ;
    PORT
      LAYER M4 ;
        RECT  0 65.328 0.192 65.352 ;
    END
  END di[376]
  PIN di[377]
    DIRECTION INPUT ;
    USE SIGNAL ;
    PORT
      LAYER M4 ;
        RECT  0 65.472 0.192 65.496 ;
    END
  END di[377]
  PIN di[378]
    DIRECTION INPUT ;
    USE SIGNAL ;
    PORT
      LAYER M4 ;
        RECT  0 65.664 0.192 65.688 ;
    END
  END di[378]
  PIN di[379]
    DIRECTION INPUT ;
    USE SIGNAL ;
    PORT
      LAYER M4 ;
        RECT  0 65.808 0.192 65.832 ;
    END
  END di[379]
  PIN di[37]
    DIRECTION INPUT ;
    USE SIGNAL ;
    PORT
      LAYER M4 ;
        RECT  0 10.416 0.192 10.44 ;
    END
  END di[37]
  PIN di[380]
    DIRECTION INPUT ;
    USE SIGNAL ;
    PORT
      LAYER M4 ;
        RECT  0 65.952 0.192 65.976 ;
    END
  END di[380]
  PIN di[381]
    DIRECTION INPUT ;
    USE SIGNAL ;
    PORT
      LAYER M4 ;
        RECT  0 66.144 0.192 66.168 ;
    END
  END di[381]
  PIN di[382]
    DIRECTION INPUT ;
    USE SIGNAL ;
    PORT
      LAYER M4 ;
        RECT  0 66.288 0.192 66.312 ;
    END
  END di[382]
  PIN di[383]
    DIRECTION INPUT ;
    USE SIGNAL ;
    PORT
      LAYER M4 ;
        RECT  0 66.48 0.192 66.504 ;
    END
  END di[383]
  PIN di[384]
    DIRECTION INPUT ;
    USE SIGNAL ;
    PORT
      LAYER M4 ;
        RECT  0 66.624 0.192 66.648 ;
    END
  END di[384]
  PIN di[385]
    DIRECTION INPUT ;
    USE SIGNAL ;
    PORT
      LAYER M4 ;
        RECT  0 66.768 0.192 66.792 ;
    END
  END di[385]
  PIN di[386]
    DIRECTION INPUT ;
    USE SIGNAL ;
    PORT
      LAYER M4 ;
        RECT  0 66.96 0.192 66.984 ;
    END
  END di[386]
  PIN di[387]
    DIRECTION INPUT ;
    USE SIGNAL ;
    PORT
      LAYER M4 ;
        RECT  0 67.104 0.192 67.128 ;
    END
  END di[387]
  PIN di[388]
    DIRECTION INPUT ;
    USE SIGNAL ;
    PORT
      LAYER M4 ;
        RECT  0 67.248 0.192 67.272 ;
    END
  END di[388]
  PIN di[389]
    DIRECTION INPUT ;
    USE SIGNAL ;
    PORT
      LAYER M4 ;
        RECT  0 67.44 0.192 67.464 ;
    END
  END di[389]
  PIN di[38]
    DIRECTION INPUT ;
    USE SIGNAL ;
    PORT
      LAYER M4 ;
        RECT  0 10.56 0.192 10.584 ;
    END
  END di[38]
  PIN di[390]
    DIRECTION INPUT ;
    USE SIGNAL ;
    PORT
      LAYER M4 ;
        RECT  0 67.584 0.192 67.608 ;
    END
  END di[390]
  PIN di[391]
    DIRECTION INPUT ;
    USE SIGNAL ;
    PORT
      LAYER M4 ;
        RECT  0 67.776 0.192 67.8 ;
    END
  END di[391]
  PIN di[392]
    DIRECTION INPUT ;
    USE SIGNAL ;
    PORT
      LAYER M4 ;
        RECT  0 67.92 0.192 67.944 ;
    END
  END di[392]
  PIN di[393]
    DIRECTION INPUT ;
    USE SIGNAL ;
    PORT
      LAYER M4 ;
        RECT  0 68.064 0.192 68.088 ;
    END
  END di[393]
  PIN di[394]
    DIRECTION INPUT ;
    USE SIGNAL ;
    PORT
      LAYER M4 ;
        RECT  0 68.256 0.192 68.28 ;
    END
  END di[394]
  PIN di[395]
    DIRECTION INPUT ;
    USE SIGNAL ;
    PORT
      LAYER M4 ;
        RECT  0 68.4 0.192 68.424 ;
    END
  END di[395]
  PIN di[396]
    DIRECTION INPUT ;
    USE SIGNAL ;
    PORT
      LAYER M4 ;
        RECT  0 68.544 0.192 68.568 ;
    END
  END di[396]
  PIN di[397]
    DIRECTION INPUT ;
    USE SIGNAL ;
    PORT
      LAYER M4 ;
        RECT  0 68.736 0.192 68.76 ;
    END
  END di[397]
  PIN di[398]
    DIRECTION INPUT ;
    USE SIGNAL ;
    PORT
      LAYER M4 ;
        RECT  0 68.88 0.192 68.904 ;
    END
  END di[398]
  PIN di[399]
    DIRECTION INPUT ;
    USE SIGNAL ;
    PORT
      LAYER M4 ;
        RECT  0 69.072 0.192 69.096 ;
    END
  END di[399]
  PIN di[39]
    DIRECTION INPUT ;
    USE SIGNAL ;
    PORT
      LAYER M4 ;
        RECT  0 10.752 0.192 10.776 ;
    END
  END di[39]
  PIN di[3]
    DIRECTION INPUT ;
    USE SIGNAL ;
    PORT
      LAYER M4 ;
        RECT  0 4.896 0.192 4.92 ;
    END
  END di[3]
  PIN di[400]
    DIRECTION INPUT ;
    USE SIGNAL ;
    PORT
      LAYER M4 ;
        RECT  0 69.216 0.192 69.24 ;
    END
  END di[400]
  PIN di[401]
    DIRECTION INPUT ;
    USE SIGNAL ;
    PORT
      LAYER M4 ;
        RECT  0 69.36 0.192 69.384 ;
    END
  END di[401]
  PIN di[402]
    DIRECTION INPUT ;
    USE SIGNAL ;
    PORT
      LAYER M4 ;
        RECT  0 69.552 0.192 69.576 ;
    END
  END di[402]
  PIN di[403]
    DIRECTION INPUT ;
    USE SIGNAL ;
    PORT
      LAYER M4 ;
        RECT  0 69.696 0.192 69.72 ;
    END
  END di[403]
  PIN di[404]
    DIRECTION INPUT ;
    USE SIGNAL ;
    PORT
      LAYER M4 ;
        RECT  0 69.84 0.192 69.864 ;
    END
  END di[404]
  PIN di[405]
    DIRECTION INPUT ;
    USE SIGNAL ;
    PORT
      LAYER M4 ;
        RECT  0 70.032 0.192 70.056 ;
    END
  END di[405]
  PIN di[406]
    DIRECTION INPUT ;
    USE SIGNAL ;
    PORT
      LAYER M4 ;
        RECT  0 70.176 0.192 70.2 ;
    END
  END di[406]
  PIN di[407]
    DIRECTION INPUT ;
    USE SIGNAL ;
    PORT
      LAYER M4 ;
        RECT  0 70.368 0.192 70.392 ;
    END
  END di[407]
  PIN di[408]
    DIRECTION INPUT ;
    USE SIGNAL ;
    PORT
      LAYER M4 ;
        RECT  0 70.512 0.192 70.536 ;
    END
  END di[408]
  PIN di[409]
    DIRECTION INPUT ;
    USE SIGNAL ;
    PORT
      LAYER M4 ;
        RECT  0 70.656 0.192 70.68 ;
    END
  END di[409]
  PIN di[40]
    DIRECTION INPUT ;
    USE SIGNAL ;
    PORT
      LAYER M4 ;
        RECT  0 10.896 0.192 10.92 ;
    END
  END di[40]
  PIN di[410]
    DIRECTION INPUT ;
    USE SIGNAL ;
    PORT
      LAYER M4 ;
        RECT  0 70.848 0.192 70.872 ;
    END
  END di[410]
  PIN di[411]
    DIRECTION INPUT ;
    USE SIGNAL ;
    PORT
      LAYER M4 ;
        RECT  0 70.992 0.192 71.016 ;
    END
  END di[411]
  PIN di[412]
    DIRECTION INPUT ;
    USE SIGNAL ;
    PORT
      LAYER M4 ;
        RECT  0 71.136 0.192 71.16 ;
    END
  END di[412]
  PIN di[413]
    DIRECTION INPUT ;
    USE SIGNAL ;
    PORT
      LAYER M4 ;
        RECT  0 71.328 0.192 71.352 ;
    END
  END di[413]
  PIN di[414]
    DIRECTION INPUT ;
    USE SIGNAL ;
    PORT
      LAYER M4 ;
        RECT  0 71.472 0.192 71.496 ;
    END
  END di[414]
  PIN di[415]
    DIRECTION INPUT ;
    USE SIGNAL ;
    PORT
      LAYER M4 ;
        RECT  0 71.664 0.192 71.688 ;
    END
  END di[415]
  PIN di[416]
    DIRECTION INPUT ;
    USE SIGNAL ;
    PORT
      LAYER M4 ;
        RECT  0 71.808 0.192 71.832 ;
    END
  END di[416]
  PIN di[417]
    DIRECTION INPUT ;
    USE SIGNAL ;
    PORT
      LAYER M4 ;
        RECT  0 71.952 0.192 71.976 ;
    END
  END di[417]
  PIN di[418]
    DIRECTION INPUT ;
    USE SIGNAL ;
    PORT
      LAYER M4 ;
        RECT  0 72.144 0.192 72.168 ;
    END
  END di[418]
  PIN di[419]
    DIRECTION INPUT ;
    USE SIGNAL ;
    PORT
      LAYER M4 ;
        RECT  0 72.288 0.192 72.312 ;
    END
  END di[419]
  PIN di[41]
    DIRECTION INPUT ;
    USE SIGNAL ;
    PORT
      LAYER M4 ;
        RECT  0 11.04 0.192 11.064 ;
    END
  END di[41]
  PIN di[420]
    DIRECTION INPUT ;
    USE SIGNAL ;
    PORT
      LAYER M4 ;
        RECT  0 72.432 0.192 72.456 ;
    END
  END di[420]
  PIN di[421]
    DIRECTION INPUT ;
    USE SIGNAL ;
    PORT
      LAYER M4 ;
        RECT  0 72.624 0.192 72.648 ;
    END
  END di[421]
  PIN di[422]
    DIRECTION INPUT ;
    USE SIGNAL ;
    PORT
      LAYER M4 ;
        RECT  0 72.768 0.192 72.792 ;
    END
  END di[422]
  PIN di[423]
    DIRECTION INPUT ;
    USE SIGNAL ;
    PORT
      LAYER M4 ;
        RECT  0 72.96 0.192 72.984 ;
    END
  END di[423]
  PIN di[424]
    DIRECTION INPUT ;
    USE SIGNAL ;
    PORT
      LAYER M4 ;
        RECT  0 73.104 0.192 73.128 ;
    END
  END di[424]
  PIN di[425]
    DIRECTION INPUT ;
    USE SIGNAL ;
    PORT
      LAYER M4 ;
        RECT  0 73.248 0.192 73.272 ;
    END
  END di[425]
  PIN di[426]
    DIRECTION INPUT ;
    USE SIGNAL ;
    PORT
      LAYER M4 ;
        RECT  0 73.44 0.192 73.464 ;
    END
  END di[426]
  PIN di[427]
    DIRECTION INPUT ;
    USE SIGNAL ;
    PORT
      LAYER M4 ;
        RECT  0 73.584 0.192 73.608 ;
    END
  END di[427]
  PIN di[428]
    DIRECTION INPUT ;
    USE SIGNAL ;
    PORT
      LAYER M4 ;
        RECT  0 73.728 0.192 73.752 ;
    END
  END di[428]
  PIN di[429]
    DIRECTION INPUT ;
    USE SIGNAL ;
    PORT
      LAYER M4 ;
        RECT  0 73.92 0.192 73.944 ;
    END
  END di[429]
  PIN di[42]
    DIRECTION INPUT ;
    USE SIGNAL ;
    PORT
      LAYER M4 ;
        RECT  0 11.232 0.192 11.256 ;
    END
  END di[42]
  PIN di[430]
    DIRECTION INPUT ;
    USE SIGNAL ;
    PORT
      LAYER M4 ;
        RECT  0 74.064 0.192 74.088 ;
    END
  END di[430]
  PIN di[431]
    DIRECTION INPUT ;
    USE SIGNAL ;
    PORT
      LAYER M4 ;
        RECT  0 74.256 0.192 74.28 ;
    END
  END di[431]
  PIN di[432]
    DIRECTION INPUT ;
    USE SIGNAL ;
    PORT
      LAYER M4 ;
        RECT  0 74.4 0.192 74.424 ;
    END
  END di[432]
  PIN di[433]
    DIRECTION INPUT ;
    USE SIGNAL ;
    PORT
      LAYER M4 ;
        RECT  0 74.544 0.192 74.568 ;
    END
  END di[433]
  PIN di[434]
    DIRECTION INPUT ;
    USE SIGNAL ;
    PORT
      LAYER M4 ;
        RECT  0 74.736 0.192 74.76 ;
    END
  END di[434]
  PIN di[435]
    DIRECTION INPUT ;
    USE SIGNAL ;
    PORT
      LAYER M4 ;
        RECT  0 74.88 0.192 74.904 ;
    END
  END di[435]
  PIN di[436]
    DIRECTION INPUT ;
    USE SIGNAL ;
    PORT
      LAYER M4 ;
        RECT  0 75.024 0.192 75.048 ;
    END
  END di[436]
  PIN di[437]
    DIRECTION INPUT ;
    USE SIGNAL ;
    PORT
      LAYER M4 ;
        RECT  0 75.216 0.192 75.24 ;
    END
  END di[437]
  PIN di[438]
    DIRECTION INPUT ;
    USE SIGNAL ;
    PORT
      LAYER M4 ;
        RECT  0 75.36 0.192 75.384 ;
    END
  END di[438]
  PIN di[439]
    DIRECTION INPUT ;
    USE SIGNAL ;
    PORT
      LAYER M4 ;
        RECT  0 75.552 0.192 75.576 ;
    END
  END di[439]
  PIN di[43]
    DIRECTION INPUT ;
    USE SIGNAL ;
    PORT
      LAYER M4 ;
        RECT  0 11.376 0.192 11.4 ;
    END
  END di[43]
  PIN di[440]
    DIRECTION INPUT ;
    USE SIGNAL ;
    PORT
      LAYER M4 ;
        RECT  0 75.696 0.192 75.72 ;
    END
  END di[440]
  PIN di[441]
    DIRECTION INPUT ;
    USE SIGNAL ;
    PORT
      LAYER M4 ;
        RECT  0 75.84 0.192 75.864 ;
    END
  END di[441]
  PIN di[442]
    DIRECTION INPUT ;
    USE SIGNAL ;
    PORT
      LAYER M4 ;
        RECT  0 76.032 0.192 76.056 ;
    END
  END di[442]
  PIN di[443]
    DIRECTION INPUT ;
    USE SIGNAL ;
    PORT
      LAYER M4 ;
        RECT  0 76.176 0.192 76.2 ;
    END
  END di[443]
  PIN di[444]
    DIRECTION INPUT ;
    USE SIGNAL ;
    PORT
      LAYER M4 ;
        RECT  0 76.32 0.192 76.344 ;
    END
  END di[444]
  PIN di[445]
    DIRECTION INPUT ;
    USE SIGNAL ;
    PORT
      LAYER M4 ;
        RECT  0 76.512 0.192 76.536 ;
    END
  END di[445]
  PIN di[446]
    DIRECTION INPUT ;
    USE SIGNAL ;
    PORT
      LAYER M4 ;
        RECT  0 76.656 0.192 76.68 ;
    END
  END di[446]
  PIN di[447]
    DIRECTION INPUT ;
    USE SIGNAL ;
    PORT
      LAYER M4 ;
        RECT  0 76.848 0.192 76.872 ;
    END
  END di[447]
  PIN di[448]
    DIRECTION INPUT ;
    USE SIGNAL ;
    PORT
      LAYER M4 ;
        RECT  0 76.992 0.192 77.016 ;
    END
  END di[448]
  PIN di[449]
    DIRECTION INPUT ;
    USE SIGNAL ;
    PORT
      LAYER M4 ;
        RECT  0 77.136 0.192 77.16 ;
    END
  END di[449]
  PIN di[44]
    DIRECTION INPUT ;
    USE SIGNAL ;
    PORT
      LAYER M4 ;
        RECT  0 11.52 0.192 11.544 ;
    END
  END di[44]
  PIN di[450]
    DIRECTION INPUT ;
    USE SIGNAL ;
    PORT
      LAYER M4 ;
        RECT  0 77.328 0.192 77.352 ;
    END
  END di[450]
  PIN di[451]
    DIRECTION INPUT ;
    USE SIGNAL ;
    PORT
      LAYER M4 ;
        RECT  0 77.472 0.192 77.496 ;
    END
  END di[451]
  PIN di[452]
    DIRECTION INPUT ;
    USE SIGNAL ;
    PORT
      LAYER M4 ;
        RECT  0 77.616 0.192 77.64 ;
    END
  END di[452]
  PIN di[453]
    DIRECTION INPUT ;
    USE SIGNAL ;
    PORT
      LAYER M4 ;
        RECT  0 77.808 0.192 77.832 ;
    END
  END di[453]
  PIN di[454]
    DIRECTION INPUT ;
    USE SIGNAL ;
    PORT
      LAYER M4 ;
        RECT  0 77.952 0.192 77.976 ;
    END
  END di[454]
  PIN di[455]
    DIRECTION INPUT ;
    USE SIGNAL ;
    PORT
      LAYER M4 ;
        RECT  0 78.144 0.192 78.168 ;
    END
  END di[455]
  PIN di[456]
    DIRECTION INPUT ;
    USE SIGNAL ;
    PORT
      LAYER M4 ;
        RECT  0 78.288 0.192 78.312 ;
    END
  END di[456]
  PIN di[457]
    DIRECTION INPUT ;
    USE SIGNAL ;
    PORT
      LAYER M4 ;
        RECT  0 78.432 0.192 78.456 ;
    END
  END di[457]
  PIN di[458]
    DIRECTION INPUT ;
    USE SIGNAL ;
    PORT
      LAYER M4 ;
        RECT  0 78.624 0.192 78.648 ;
    END
  END di[458]
  PIN di[459]
    DIRECTION INPUT ;
    USE SIGNAL ;
    PORT
      LAYER M4 ;
        RECT  0 78.768 0.192 78.792 ;
    END
  END di[459]
  PIN di[45]
    DIRECTION INPUT ;
    USE SIGNAL ;
    PORT
      LAYER M4 ;
        RECT  0 11.712 0.192 11.736 ;
    END
  END di[45]
  PIN di[460]
    DIRECTION INPUT ;
    USE SIGNAL ;
    PORT
      LAYER M4 ;
        RECT  0 78.912 0.192 78.936 ;
    END
  END di[460]
  PIN di[461]
    DIRECTION INPUT ;
    USE SIGNAL ;
    PORT
      LAYER M4 ;
        RECT  0 79.104 0.192 79.128 ;
    END
  END di[461]
  PIN di[462]
    DIRECTION INPUT ;
    USE SIGNAL ;
    PORT
      LAYER M4 ;
        RECT  0 79.248 0.192 79.272 ;
    END
  END di[462]
  PIN di[463]
    DIRECTION INPUT ;
    USE SIGNAL ;
    PORT
      LAYER M4 ;
        RECT  0 79.44 0.192 79.464 ;
    END
  END di[463]
  PIN di[464]
    DIRECTION INPUT ;
    USE SIGNAL ;
    PORT
      LAYER M4 ;
        RECT  0 79.584 0.192 79.608 ;
    END
  END di[464]
  PIN di[465]
    DIRECTION INPUT ;
    USE SIGNAL ;
    PORT
      LAYER M4 ;
        RECT  0 79.728 0.192 79.752 ;
    END
  END di[465]
  PIN di[466]
    DIRECTION INPUT ;
    USE SIGNAL ;
    PORT
      LAYER M4 ;
        RECT  0 79.92 0.192 79.944 ;
    END
  END di[466]
  PIN di[467]
    DIRECTION INPUT ;
    USE SIGNAL ;
    PORT
      LAYER M4 ;
        RECT  0 80.064 0.192 80.088 ;
    END
  END di[467]
  PIN di[468]
    DIRECTION INPUT ;
    USE SIGNAL ;
    PORT
      LAYER M4 ;
        RECT  0 80.208 0.192 80.232 ;
    END
  END di[468]
  PIN di[469]
    DIRECTION INPUT ;
    USE SIGNAL ;
    PORT
      LAYER M4 ;
        RECT  0 80.4 0.192 80.424 ;
    END
  END di[469]
  PIN di[46]
    DIRECTION INPUT ;
    USE SIGNAL ;
    PORT
      LAYER M4 ;
        RECT  0 11.856 0.192 11.88 ;
    END
  END di[46]
  PIN di[470]
    DIRECTION INPUT ;
    USE SIGNAL ;
    PORT
      LAYER M4 ;
        RECT  0 80.544 0.192 80.568 ;
    END
  END di[470]
  PIN di[471]
    DIRECTION INPUT ;
    USE SIGNAL ;
    PORT
      LAYER M4 ;
        RECT  0 80.736 0.192 80.76 ;
    END
  END di[471]
  PIN di[472]
    DIRECTION INPUT ;
    USE SIGNAL ;
    PORT
      LAYER M4 ;
        RECT  0 80.88 0.192 80.904 ;
    END
  END di[472]
  PIN di[473]
    DIRECTION INPUT ;
    USE SIGNAL ;
    PORT
      LAYER M4 ;
        RECT  0 81.024 0.192 81.048 ;
    END
  END di[473]
  PIN di[474]
    DIRECTION INPUT ;
    USE SIGNAL ;
    PORT
      LAYER M4 ;
        RECT  0 81.216 0.192 81.24 ;
    END
  END di[474]
  PIN di[475]
    DIRECTION INPUT ;
    USE SIGNAL ;
    PORT
      LAYER M4 ;
        RECT  0 81.36 0.192 81.384 ;
    END
  END di[475]
  PIN di[476]
    DIRECTION INPUT ;
    USE SIGNAL ;
    PORT
      LAYER M4 ;
        RECT  0 81.504 0.192 81.528 ;
    END
  END di[476]
  PIN di[477]
    DIRECTION INPUT ;
    USE SIGNAL ;
    PORT
      LAYER M4 ;
        RECT  0 81.696 0.192 81.72 ;
    END
  END di[477]
  PIN di[478]
    DIRECTION INPUT ;
    USE SIGNAL ;
    PORT
      LAYER M4 ;
        RECT  0 81.84 0.192 81.864 ;
    END
  END di[478]
  PIN di[479]
    DIRECTION INPUT ;
    USE SIGNAL ;
    PORT
      LAYER M4 ;
        RECT  0 82.032 0.192 82.056 ;
    END
  END di[479]
  PIN di[47]
    DIRECTION INPUT ;
    USE SIGNAL ;
    PORT
      LAYER M4 ;
        RECT  0 12.048 0.192 12.072 ;
    END
  END di[47]
  PIN di[480]
    DIRECTION INPUT ;
    USE SIGNAL ;
    PORT
      LAYER M4 ;
        RECT  0 82.176 0.192 82.2 ;
    END
  END di[480]
  PIN di[481]
    DIRECTION INPUT ;
    USE SIGNAL ;
    PORT
      LAYER M4 ;
        RECT  0 82.32 0.192 82.344 ;
    END
  END di[481]
  PIN di[482]
    DIRECTION INPUT ;
    USE SIGNAL ;
    PORT
      LAYER M4 ;
        RECT  0 82.512 0.192 82.536 ;
    END
  END di[482]
  PIN di[483]
    DIRECTION INPUT ;
    USE SIGNAL ;
    PORT
      LAYER M4 ;
        RECT  0 82.656 0.192 82.68 ;
    END
  END di[483]
  PIN di[484]
    DIRECTION INPUT ;
    USE SIGNAL ;
    PORT
      LAYER M4 ;
        RECT  0 82.8 0.192 82.824 ;
    END
  END di[484]
  PIN di[485]
    DIRECTION INPUT ;
    USE SIGNAL ;
    PORT
      LAYER M4 ;
        RECT  0 82.992 0.192 83.016 ;
    END
  END di[485]
  PIN di[486]
    DIRECTION INPUT ;
    USE SIGNAL ;
    PORT
      LAYER M4 ;
        RECT  0 83.136 0.192 83.16 ;
    END
  END di[486]
  PIN di[487]
    DIRECTION INPUT ;
    USE SIGNAL ;
    PORT
      LAYER M4 ;
        RECT  0 83.328 0.192 83.352 ;
    END
  END di[487]
  PIN di[488]
    DIRECTION INPUT ;
    USE SIGNAL ;
    PORT
      LAYER M4 ;
        RECT  0 83.472 0.192 83.496 ;
    END
  END di[488]
  PIN di[489]
    DIRECTION INPUT ;
    USE SIGNAL ;
    PORT
      LAYER M4 ;
        RECT  0 83.616 0.192 83.64 ;
    END
  END di[489]
  PIN di[48]
    DIRECTION INPUT ;
    USE SIGNAL ;
    PORT
      LAYER M4 ;
        RECT  0 12.192 0.192 12.216 ;
    END
  END di[48]
  PIN di[490]
    DIRECTION INPUT ;
    USE SIGNAL ;
    PORT
      LAYER M4 ;
        RECT  0 83.808 0.192 83.832 ;
    END
  END di[490]
  PIN di[491]
    DIRECTION INPUT ;
    USE SIGNAL ;
    PORT
      LAYER M4 ;
        RECT  0 83.952 0.192 83.976 ;
    END
  END di[491]
  PIN di[492]
    DIRECTION INPUT ;
    USE SIGNAL ;
    PORT
      LAYER M4 ;
        RECT  0 84.096 0.192 84.12 ;
    END
  END di[492]
  PIN di[493]
    DIRECTION INPUT ;
    USE SIGNAL ;
    PORT
      LAYER M4 ;
        RECT  0 84.288 0.192 84.312 ;
    END
  END di[493]
  PIN di[494]
    DIRECTION INPUT ;
    USE SIGNAL ;
    PORT
      LAYER M4 ;
        RECT  0 84.432 0.192 84.456 ;
    END
  END di[494]
  PIN di[495]
    DIRECTION INPUT ;
    USE SIGNAL ;
    PORT
      LAYER M4 ;
        RECT  0 84.624 0.192 84.648 ;
    END
  END di[495]
  PIN di[496]
    DIRECTION INPUT ;
    USE SIGNAL ;
    PORT
      LAYER M4 ;
        RECT  0 84.768 0.192 84.792 ;
    END
  END di[496]
  PIN di[497]
    DIRECTION INPUT ;
    USE SIGNAL ;
    PORT
      LAYER M4 ;
        RECT  0 84.912 0.192 84.936 ;
    END
  END di[497]
  PIN di[498]
    DIRECTION INPUT ;
    USE SIGNAL ;
    PORT
      LAYER M4 ;
        RECT  0 85.104 0.192 85.128 ;
    END
  END di[498]
  PIN di[499]
    DIRECTION INPUT ;
    USE SIGNAL ;
    PORT
      LAYER M4 ;
        RECT  0 85.248 0.192 85.272 ;
    END
  END di[499]
  PIN di[49]
    DIRECTION INPUT ;
    USE SIGNAL ;
    PORT
      LAYER M4 ;
        RECT  0 12.336 0.192 12.36 ;
    END
  END di[49]
  PIN di[4]
    DIRECTION INPUT ;
    USE SIGNAL ;
    PORT
      LAYER M4 ;
        RECT  0 5.04 0.192 5.064 ;
    END
  END di[4]
  PIN di[500]
    DIRECTION INPUT ;
    USE SIGNAL ;
    PORT
      LAYER M4 ;
        RECT  0 85.392 0.192 85.416 ;
    END
  END di[500]
  PIN di[501]
    DIRECTION INPUT ;
    USE SIGNAL ;
    PORT
      LAYER M4 ;
        RECT  0 85.584 0.192 85.608 ;
    END
  END di[501]
  PIN di[502]
    DIRECTION INPUT ;
    USE SIGNAL ;
    PORT
      LAYER M4 ;
        RECT  0 85.728 0.192 85.752 ;
    END
  END di[502]
  PIN di[503]
    DIRECTION INPUT ;
    USE SIGNAL ;
    PORT
      LAYER M4 ;
        RECT  0 85.92 0.192 85.944 ;
    END
  END di[503]
  PIN di[504]
    DIRECTION INPUT ;
    USE SIGNAL ;
    PORT
      LAYER M4 ;
        RECT  0 86.064 0.192 86.088 ;
    END
  END di[504]
  PIN di[505]
    DIRECTION INPUT ;
    USE SIGNAL ;
    PORT
      LAYER M4 ;
        RECT  0 86.208 0.192 86.232 ;
    END
  END di[505]
  PIN di[506]
    DIRECTION INPUT ;
    USE SIGNAL ;
    PORT
      LAYER M4 ;
        RECT  0 86.4 0.192 86.424 ;
    END
  END di[506]
  PIN di[507]
    DIRECTION INPUT ;
    USE SIGNAL ;
    PORT
      LAYER M4 ;
        RECT  0 86.544 0.192 86.568 ;
    END
  END di[507]
  PIN di[508]
    DIRECTION INPUT ;
    USE SIGNAL ;
    PORT
      LAYER M4 ;
        RECT  0 86.688 0.192 86.712 ;
    END
  END di[508]
  PIN di[509]
    DIRECTION INPUT ;
    USE SIGNAL ;
    PORT
      LAYER M4 ;
        RECT  0 86.88 0.192 86.904 ;
    END
  END di[509]
  PIN di[50]
    DIRECTION INPUT ;
    USE SIGNAL ;
    PORT
      LAYER M4 ;
        RECT  0 12.528 0.192 12.552 ;
    END
  END di[50]
  PIN di[510]
    DIRECTION INPUT ;
    USE SIGNAL ;
    PORT
      LAYER M4 ;
        RECT  0 87.024 0.192 87.048 ;
    END
  END di[510]
  PIN di[511]
    DIRECTION INPUT ;
    USE SIGNAL ;
    PORT
      LAYER M4 ;
        RECT  0 87.216 0.192 87.24 ;
    END
  END di[511]
  PIN di[512]
    DIRECTION INPUT ;
    USE SIGNAL ;
    PORT
      LAYER M4 ;
        RECT  0 87.36 0.192 87.384 ;
    END
  END di[512]
  PIN di[513]
    DIRECTION INPUT ;
    USE SIGNAL ;
    PORT
      LAYER M4 ;
        RECT  0 87.504 0.192 87.528 ;
    END
  END di[513]
  PIN di[514]
    DIRECTION INPUT ;
    USE SIGNAL ;
    PORT
      LAYER M4 ;
        RECT  0 87.696 0.192 87.72 ;
    END
  END di[514]
  PIN di[515]
    DIRECTION INPUT ;
    USE SIGNAL ;
    PORT
      LAYER M4 ;
        RECT  0 87.84 0.192 87.864 ;
    END
  END di[515]
  PIN di[516]
    DIRECTION INPUT ;
    USE SIGNAL ;
    PORT
      LAYER M4 ;
        RECT  0 87.984 0.192 88.008 ;
    END
  END di[516]
  PIN di[517]
    DIRECTION INPUT ;
    USE SIGNAL ;
    PORT
      LAYER M4 ;
        RECT  0 88.176 0.192 88.2 ;
    END
  END di[517]
  PIN di[518]
    DIRECTION INPUT ;
    USE SIGNAL ;
    PORT
      LAYER M4 ;
        RECT  0 88.32 0.192 88.344 ;
    END
  END di[518]
  PIN di[519]
    DIRECTION INPUT ;
    USE SIGNAL ;
    PORT
      LAYER M4 ;
        RECT  0 88.512 0.192 88.536 ;
    END
  END di[519]
  PIN di[51]
    DIRECTION INPUT ;
    USE SIGNAL ;
    PORT
      LAYER M4 ;
        RECT  0 12.672 0.192 12.696 ;
    END
  END di[51]
  PIN di[520]
    DIRECTION INPUT ;
    USE SIGNAL ;
    PORT
      LAYER M4 ;
        RECT  0 88.656 0.192 88.68 ;
    END
  END di[520]
  PIN di[521]
    DIRECTION INPUT ;
    USE SIGNAL ;
    PORT
      LAYER M4 ;
        RECT  0 88.8 0.192 88.824 ;
    END
  END di[521]
  PIN di[522]
    DIRECTION INPUT ;
    USE SIGNAL ;
    PORT
      LAYER M4 ;
        RECT  0 88.992 0.192 89.016 ;
    END
  END di[522]
  PIN di[523]
    DIRECTION INPUT ;
    USE SIGNAL ;
    PORT
      LAYER M4 ;
        RECT  0 89.136 0.192 89.16 ;
    END
  END di[523]
  PIN di[524]
    DIRECTION INPUT ;
    USE SIGNAL ;
    PORT
      LAYER M4 ;
        RECT  0 89.28 0.192 89.304 ;
    END
  END di[524]
  PIN di[525]
    DIRECTION INPUT ;
    USE SIGNAL ;
    PORT
      LAYER M4 ;
        RECT  0 89.472 0.192 89.496 ;
    END
  END di[525]
  PIN di[526]
    DIRECTION INPUT ;
    USE SIGNAL ;
    PORT
      LAYER M4 ;
        RECT  0 89.616 0.192 89.64 ;
    END
  END di[526]
  PIN di[527]
    DIRECTION INPUT ;
    USE SIGNAL ;
    PORT
      LAYER M4 ;
        RECT  0 89.808 0.192 89.832 ;
    END
  END di[527]
  PIN di[528]
    DIRECTION INPUT ;
    USE SIGNAL ;
    PORT
      LAYER M4 ;
        RECT  0 89.952 0.192 89.976 ;
    END
  END di[528]
  PIN di[529]
    DIRECTION INPUT ;
    USE SIGNAL ;
    PORT
      LAYER M4 ;
        RECT  0 90.096 0.192 90.12 ;
    END
  END di[529]
  PIN di[52]
    DIRECTION INPUT ;
    USE SIGNAL ;
    PORT
      LAYER M4 ;
        RECT  0 12.816 0.192 12.84 ;
    END
  END di[52]
  PIN di[530]
    DIRECTION INPUT ;
    USE SIGNAL ;
    PORT
      LAYER M4 ;
        RECT  0 90.288 0.192 90.312 ;
    END
  END di[530]
  PIN di[531]
    DIRECTION INPUT ;
    USE SIGNAL ;
    PORT
      LAYER M4 ;
        RECT  0 90.432 0.192 90.456 ;
    END
  END di[531]
  PIN di[532]
    DIRECTION INPUT ;
    USE SIGNAL ;
    PORT
      LAYER M4 ;
        RECT  0 90.576 0.192 90.6 ;
    END
  END di[532]
  PIN di[533]
    DIRECTION INPUT ;
    USE SIGNAL ;
    PORT
      LAYER M4 ;
        RECT  0 90.768 0.192 90.792 ;
    END
  END di[533]
  PIN di[534]
    DIRECTION INPUT ;
    USE SIGNAL ;
    PORT
      LAYER M4 ;
        RECT  0 90.912 0.192 90.936 ;
    END
  END di[534]
  PIN di[535]
    DIRECTION INPUT ;
    USE SIGNAL ;
    PORT
      LAYER M4 ;
        RECT  0 91.104 0.192 91.128 ;
    END
  END di[535]
  PIN di[536]
    DIRECTION INPUT ;
    USE SIGNAL ;
    PORT
      LAYER M4 ;
        RECT  0 91.248 0.192 91.272 ;
    END
  END di[536]
  PIN di[537]
    DIRECTION INPUT ;
    USE SIGNAL ;
    PORT
      LAYER M4 ;
        RECT  0 91.392 0.192 91.416 ;
    END
  END di[537]
  PIN di[538]
    DIRECTION INPUT ;
    USE SIGNAL ;
    PORT
      LAYER M4 ;
        RECT  0 91.584 0.192 91.608 ;
    END
  END di[538]
  PIN di[539]
    DIRECTION INPUT ;
    USE SIGNAL ;
    PORT
      LAYER M4 ;
        RECT  0 91.728 0.192 91.752 ;
    END
  END di[539]
  PIN di[53]
    DIRECTION INPUT ;
    USE SIGNAL ;
    PORT
      LAYER M4 ;
        RECT  0 13.008 0.192 13.032 ;
    END
  END di[53]
  PIN di[540]
    DIRECTION INPUT ;
    USE SIGNAL ;
    PORT
      LAYER M4 ;
        RECT  0 91.872 0.192 91.896 ;
    END
  END di[540]
  PIN di[541]
    DIRECTION INPUT ;
    USE SIGNAL ;
    PORT
      LAYER M4 ;
        RECT  0 92.064 0.192 92.088 ;
    END
  END di[541]
  PIN di[542]
    DIRECTION INPUT ;
    USE SIGNAL ;
    PORT
      LAYER M4 ;
        RECT  0 92.208 0.192 92.232 ;
    END
  END di[542]
  PIN di[543]
    DIRECTION INPUT ;
    USE SIGNAL ;
    PORT
      LAYER M4 ;
        RECT  0 92.4 0.192 92.424 ;
    END
  END di[543]
  PIN di[544]
    DIRECTION INPUT ;
    USE SIGNAL ;
    PORT
      LAYER M4 ;
        RECT  0 92.544 0.192 92.568 ;
    END
  END di[544]
  PIN di[545]
    DIRECTION INPUT ;
    USE SIGNAL ;
    PORT
      LAYER M4 ;
        RECT  0 92.688 0.192 92.712 ;
    END
  END di[545]
  PIN di[546]
    DIRECTION INPUT ;
    USE SIGNAL ;
    PORT
      LAYER M4 ;
        RECT  0 92.88 0.192 92.904 ;
    END
  END di[546]
  PIN di[547]
    DIRECTION INPUT ;
    USE SIGNAL ;
    PORT
      LAYER M4 ;
        RECT  0 93.024 0.192 93.048 ;
    END
  END di[547]
  PIN di[548]
    DIRECTION INPUT ;
    USE SIGNAL ;
    PORT
      LAYER M4 ;
        RECT  0 93.168 0.192 93.192 ;
    END
  END di[548]
  PIN di[549]
    DIRECTION INPUT ;
    USE SIGNAL ;
    PORT
      LAYER M4 ;
        RECT  0 93.36 0.192 93.384 ;
    END
  END di[549]
  PIN di[54]
    DIRECTION INPUT ;
    USE SIGNAL ;
    PORT
      LAYER M4 ;
        RECT  0 13.152 0.192 13.176 ;
    END
  END di[54]
  PIN di[550]
    DIRECTION INPUT ;
    USE SIGNAL ;
    PORT
      LAYER M4 ;
        RECT  0 93.504 0.192 93.528 ;
    END
  END di[550]
  PIN di[551]
    DIRECTION INPUT ;
    USE SIGNAL ;
    PORT
      LAYER M4 ;
        RECT  0 93.696 0.192 93.72 ;
    END
  END di[551]
  PIN di[552]
    DIRECTION INPUT ;
    USE SIGNAL ;
    PORT
      LAYER M4 ;
        RECT  0 93.84 0.192 93.864 ;
    END
  END di[552]
  PIN di[553]
    DIRECTION INPUT ;
    USE SIGNAL ;
    PORT
      LAYER M4 ;
        RECT  0 93.984 0.192 94.008 ;
    END
  END di[553]
  PIN di[554]
    DIRECTION INPUT ;
    USE SIGNAL ;
    PORT
      LAYER M4 ;
        RECT  0 94.176 0.192 94.2 ;
    END
  END di[554]
  PIN di[555]
    DIRECTION INPUT ;
    USE SIGNAL ;
    PORT
      LAYER M4 ;
        RECT  0 94.32 0.192 94.344 ;
    END
  END di[555]
  PIN di[556]
    DIRECTION INPUT ;
    USE SIGNAL ;
    PORT
      LAYER M4 ;
        RECT  0 94.464 0.192 94.488 ;
    END
  END di[556]
  PIN di[557]
    DIRECTION INPUT ;
    USE SIGNAL ;
    PORT
      LAYER M4 ;
        RECT  0 94.656 0.192 94.68 ;
    END
  END di[557]
  PIN di[558]
    DIRECTION INPUT ;
    USE SIGNAL ;
    PORT
      LAYER M4 ;
        RECT  0 94.8 0.192 94.824 ;
    END
  END di[558]
  PIN di[559]
    DIRECTION INPUT ;
    USE SIGNAL ;
    PORT
      LAYER M4 ;
        RECT  0 94.992 0.192 95.016 ;
    END
  END di[559]
  PIN di[55]
    DIRECTION INPUT ;
    USE SIGNAL ;
    PORT
      LAYER M4 ;
        RECT  0 13.344 0.192 13.368 ;
    END
  END di[55]
  PIN di[56]
    DIRECTION INPUT ;
    USE SIGNAL ;
    PORT
      LAYER M4 ;
        RECT  0 13.488 0.192 13.512 ;
    END
  END di[56]
  PIN di[57]
    DIRECTION INPUT ;
    USE SIGNAL ;
    PORT
      LAYER M4 ;
        RECT  0 13.632 0.192 13.656 ;
    END
  END di[57]
  PIN di[58]
    DIRECTION INPUT ;
    USE SIGNAL ;
    PORT
      LAYER M4 ;
        RECT  0 13.824 0.192 13.848 ;
    END
  END di[58]
  PIN di[59]
    DIRECTION INPUT ;
    USE SIGNAL ;
    PORT
      LAYER M4 ;
        RECT  0 13.968 0.192 13.992 ;
    END
  END di[59]
  PIN di[5]
    DIRECTION INPUT ;
    USE SIGNAL ;
    PORT
      LAYER M4 ;
        RECT  0 5.232 0.192 5.256 ;
    END
  END di[5]
  PIN di[60]
    DIRECTION INPUT ;
    USE SIGNAL ;
    PORT
      LAYER M4 ;
        RECT  0 14.112 0.192 14.136 ;
    END
  END di[60]
  PIN di[61]
    DIRECTION INPUT ;
    USE SIGNAL ;
    PORT
      LAYER M4 ;
        RECT  0 14.304 0.192 14.328 ;
    END
  END di[61]
  PIN di[62]
    DIRECTION INPUT ;
    USE SIGNAL ;
    PORT
      LAYER M4 ;
        RECT  0 14.448 0.192 14.472 ;
    END
  END di[62]
  PIN di[63]
    DIRECTION INPUT ;
    USE SIGNAL ;
    PORT
      LAYER M4 ;
        RECT  0 14.64 0.192 14.664 ;
    END
  END di[63]
  PIN di[64]
    DIRECTION INPUT ;
    USE SIGNAL ;
    PORT
      LAYER M4 ;
        RECT  0 14.784 0.192 14.808 ;
    END
  END di[64]
  PIN di[65]
    DIRECTION INPUT ;
    USE SIGNAL ;
    PORT
      LAYER M4 ;
        RECT  0 14.928 0.192 14.952 ;
    END
  END di[65]
  PIN di[66]
    DIRECTION INPUT ;
    USE SIGNAL ;
    PORT
      LAYER M4 ;
        RECT  0 15.12 0.192 15.144 ;
    END
  END di[66]
  PIN di[67]
    DIRECTION INPUT ;
    USE SIGNAL ;
    PORT
      LAYER M4 ;
        RECT  0 15.264 0.192 15.288 ;
    END
  END di[67]
  PIN di[68]
    DIRECTION INPUT ;
    USE SIGNAL ;
    PORT
      LAYER M4 ;
        RECT  0 15.408 0.192 15.432 ;
    END
  END di[68]
  PIN di[69]
    DIRECTION INPUT ;
    USE SIGNAL ;
    PORT
      LAYER M4 ;
        RECT  0 15.6 0.192 15.624 ;
    END
  END di[69]
  PIN di[6]
    DIRECTION INPUT ;
    USE SIGNAL ;
    PORT
      LAYER M4 ;
        RECT  0 5.376 0.192 5.4 ;
    END
  END di[6]
  PIN di[70]
    DIRECTION INPUT ;
    USE SIGNAL ;
    PORT
      LAYER M4 ;
        RECT  0 15.744 0.192 15.768 ;
    END
  END di[70]
  PIN di[71]
    DIRECTION INPUT ;
    USE SIGNAL ;
    PORT
      LAYER M4 ;
        RECT  0 15.936 0.192 15.96 ;
    END
  END di[71]
  PIN di[72]
    DIRECTION INPUT ;
    USE SIGNAL ;
    PORT
      LAYER M4 ;
        RECT  0 16.08 0.192 16.104 ;
    END
  END di[72]
  PIN di[73]
    DIRECTION INPUT ;
    USE SIGNAL ;
    PORT
      LAYER M4 ;
        RECT  0 16.224 0.192 16.248 ;
    END
  END di[73]
  PIN di[74]
    DIRECTION INPUT ;
    USE SIGNAL ;
    PORT
      LAYER M4 ;
        RECT  0 16.416 0.192 16.44 ;
    END
  END di[74]
  PIN di[75]
    DIRECTION INPUT ;
    USE SIGNAL ;
    PORT
      LAYER M4 ;
        RECT  0 16.56 0.192 16.584 ;
    END
  END di[75]
  PIN di[76]
    DIRECTION INPUT ;
    USE SIGNAL ;
    PORT
      LAYER M4 ;
        RECT  0 16.704 0.192 16.728 ;
    END
  END di[76]
  PIN di[77]
    DIRECTION INPUT ;
    USE SIGNAL ;
    PORT
      LAYER M4 ;
        RECT  0 16.896 0.192 16.92 ;
    END
  END di[77]
  PIN di[78]
    DIRECTION INPUT ;
    USE SIGNAL ;
    PORT
      LAYER M4 ;
        RECT  0 17.04 0.192 17.064 ;
    END
  END di[78]
  PIN di[79]
    DIRECTION INPUT ;
    USE SIGNAL ;
    PORT
      LAYER M4 ;
        RECT  0 17.232 0.192 17.256 ;
    END
  END di[79]
  PIN di[7]
    DIRECTION INPUT ;
    USE SIGNAL ;
    PORT
      LAYER M4 ;
        RECT  0 5.568 0.192 5.592 ;
    END
  END di[7]
  PIN di[80]
    DIRECTION INPUT ;
    USE SIGNAL ;
    PORT
      LAYER M4 ;
        RECT  0 17.376 0.192 17.4 ;
    END
  END di[80]
  PIN di[81]
    DIRECTION INPUT ;
    USE SIGNAL ;
    PORT
      LAYER M4 ;
        RECT  0 17.52 0.192 17.544 ;
    END
  END di[81]
  PIN di[82]
    DIRECTION INPUT ;
    USE SIGNAL ;
    PORT
      LAYER M4 ;
        RECT  0 17.712 0.192 17.736 ;
    END
  END di[82]
  PIN di[83]
    DIRECTION INPUT ;
    USE SIGNAL ;
    PORT
      LAYER M4 ;
        RECT  0 17.856 0.192 17.88 ;
    END
  END di[83]
  PIN di[84]
    DIRECTION INPUT ;
    USE SIGNAL ;
    PORT
      LAYER M4 ;
        RECT  0 18 0.192 18.024 ;
    END
  END di[84]
  PIN di[85]
    DIRECTION INPUT ;
    USE SIGNAL ;
    PORT
      LAYER M4 ;
        RECT  0 18.192 0.192 18.216 ;
    END
  END di[85]
  PIN di[86]
    DIRECTION INPUT ;
    USE SIGNAL ;
    PORT
      LAYER M4 ;
        RECT  0 18.336 0.192 18.36 ;
    END
  END di[86]
  PIN di[87]
    DIRECTION INPUT ;
    USE SIGNAL ;
    PORT
      LAYER M4 ;
        RECT  0 18.528 0.192 18.552 ;
    END
  END di[87]
  PIN di[88]
    DIRECTION INPUT ;
    USE SIGNAL ;
    PORT
      LAYER M4 ;
        RECT  0 18.672 0.192 18.696 ;
    END
  END di[88]
  PIN di[89]
    DIRECTION INPUT ;
    USE SIGNAL ;
    PORT
      LAYER M4 ;
        RECT  0 18.816 0.192 18.84 ;
    END
  END di[89]
  PIN di[8]
    DIRECTION INPUT ;
    USE SIGNAL ;
    PORT
      LAYER M4 ;
        RECT  0 5.712 0.192 5.736 ;
    END
  END di[8]
  PIN di[90]
    DIRECTION INPUT ;
    USE SIGNAL ;
    PORT
      LAYER M4 ;
        RECT  0 19.008 0.192 19.032 ;
    END
  END di[90]
  PIN di[91]
    DIRECTION INPUT ;
    USE SIGNAL ;
    PORT
      LAYER M4 ;
        RECT  0 19.152 0.192 19.176 ;
    END
  END di[91]
  PIN di[92]
    DIRECTION INPUT ;
    USE SIGNAL ;
    PORT
      LAYER M4 ;
        RECT  0 19.296 0.192 19.32 ;
    END
  END di[92]
  PIN di[93]
    DIRECTION INPUT ;
    USE SIGNAL ;
    PORT
      LAYER M4 ;
        RECT  0 19.488 0.192 19.512 ;
    END
  END di[93]
  PIN di[94]
    DIRECTION INPUT ;
    USE SIGNAL ;
    PORT
      LAYER M4 ;
        RECT  0 19.632 0.192 19.656 ;
    END
  END di[94]
  PIN di[95]
    DIRECTION INPUT ;
    USE SIGNAL ;
    PORT
      LAYER M4 ;
        RECT  0 19.824 0.192 19.848 ;
    END
  END di[95]
  PIN di[96]
    DIRECTION INPUT ;
    USE SIGNAL ;
    PORT
      LAYER M4 ;
        RECT  0 19.968 0.192 19.992 ;
    END
  END di[96]
  PIN di[97]
    DIRECTION INPUT ;
    USE SIGNAL ;
    PORT
      LAYER M4 ;
        RECT  0 20.112 0.192 20.136 ;
    END
  END di[97]
  PIN di[98]
    DIRECTION INPUT ;
    USE SIGNAL ;
    PORT
      LAYER M4 ;
        RECT  0 20.304 0.192 20.328 ;
    END
  END di[98]
  PIN di[99]
    DIRECTION INPUT ;
    USE SIGNAL ;
    PORT
      LAYER M4 ;
        RECT  0 20.448 0.192 20.472 ;
    END
  END di[99]
  PIN di[9]
    DIRECTION INPUT ;
    USE SIGNAL ;
    PORT
      LAYER M4 ;
        RECT  0 5.856 0.192 5.88 ;
    END
  END di[9]
  PIN dq[0]
    DIRECTION OUTPUT ;
    USE SIGNAL ;
    PORT
      LAYER M4 ;
        RECT  36.528 4.416 36.72 4.44 ;
    END
  END dq[0]
  PIN dq[100]
    DIRECTION OUTPUT ;
    USE SIGNAL ;
    PORT
      LAYER M4 ;
        RECT  36.528 20.592 36.72 20.616 ;
    END
  END dq[100]
  PIN dq[101]
    DIRECTION OUTPUT ;
    USE SIGNAL ;
    PORT
      LAYER M4 ;
        RECT  36.528 20.784 36.72 20.808 ;
    END
  END dq[101]
  PIN dq[102]
    DIRECTION OUTPUT ;
    USE SIGNAL ;
    PORT
      LAYER M4 ;
        RECT  36.528 20.928 36.72 20.952 ;
    END
  END dq[102]
  PIN dq[103]
    DIRECTION OUTPUT ;
    USE SIGNAL ;
    PORT
      LAYER M4 ;
        RECT  36.528 21.12 36.72 21.144 ;
    END
  END dq[103]
  PIN dq[104]
    DIRECTION OUTPUT ;
    USE SIGNAL ;
    PORT
      LAYER M4 ;
        RECT  36.528 21.264 36.72 21.288 ;
    END
  END dq[104]
  PIN dq[105]
    DIRECTION OUTPUT ;
    USE SIGNAL ;
    PORT
      LAYER M4 ;
        RECT  36.528 21.408 36.72 21.432 ;
    END
  END dq[105]
  PIN dq[106]
    DIRECTION OUTPUT ;
    USE SIGNAL ;
    PORT
      LAYER M4 ;
        RECT  36.528 21.6 36.72 21.624 ;
    END
  END dq[106]
  PIN dq[107]
    DIRECTION OUTPUT ;
    USE SIGNAL ;
    PORT
      LAYER M4 ;
        RECT  36.528 21.744 36.72 21.768 ;
    END
  END dq[107]
  PIN dq[108]
    DIRECTION OUTPUT ;
    USE SIGNAL ;
    PORT
      LAYER M4 ;
        RECT  36.528 21.888 36.72 21.912 ;
    END
  END dq[108]
  PIN dq[109]
    DIRECTION OUTPUT ;
    USE SIGNAL ;
    PORT
      LAYER M4 ;
        RECT  36.528 22.08 36.72 22.104 ;
    END
  END dq[109]
  PIN dq[10]
    DIRECTION OUTPUT ;
    USE SIGNAL ;
    PORT
      LAYER M4 ;
        RECT  36.528 6.048 36.72 6.072 ;
    END
  END dq[10]
  PIN dq[110]
    DIRECTION OUTPUT ;
    USE SIGNAL ;
    PORT
      LAYER M4 ;
        RECT  36.528 22.224 36.72 22.248 ;
    END
  END dq[110]
  PIN dq[111]
    DIRECTION OUTPUT ;
    USE SIGNAL ;
    PORT
      LAYER M4 ;
        RECT  36.528 22.416 36.72 22.44 ;
    END
  END dq[111]
  PIN dq[112]
    DIRECTION OUTPUT ;
    USE SIGNAL ;
    PORT
      LAYER M4 ;
        RECT  36.528 22.56 36.72 22.584 ;
    END
  END dq[112]
  PIN dq[113]
    DIRECTION OUTPUT ;
    USE SIGNAL ;
    PORT
      LAYER M4 ;
        RECT  36.528 22.704 36.72 22.728 ;
    END
  END dq[113]
  PIN dq[114]
    DIRECTION OUTPUT ;
    USE SIGNAL ;
    PORT
      LAYER M4 ;
        RECT  36.528 22.896 36.72 22.92 ;
    END
  END dq[114]
  PIN dq[115]
    DIRECTION OUTPUT ;
    USE SIGNAL ;
    PORT
      LAYER M4 ;
        RECT  36.528 23.04 36.72 23.064 ;
    END
  END dq[115]
  PIN dq[116]
    DIRECTION OUTPUT ;
    USE SIGNAL ;
    PORT
      LAYER M4 ;
        RECT  36.528 23.184 36.72 23.208 ;
    END
  END dq[116]
  PIN dq[117]
    DIRECTION OUTPUT ;
    USE SIGNAL ;
    PORT
      LAYER M4 ;
        RECT  36.528 23.376 36.72 23.4 ;
    END
  END dq[117]
  PIN dq[118]
    DIRECTION OUTPUT ;
    USE SIGNAL ;
    PORT
      LAYER M4 ;
        RECT  36.528 23.52 36.72 23.544 ;
    END
  END dq[118]
  PIN dq[119]
    DIRECTION OUTPUT ;
    USE SIGNAL ;
    PORT
      LAYER M4 ;
        RECT  36.528 23.712 36.72 23.736 ;
    END
  END dq[119]
  PIN dq[11]
    DIRECTION OUTPUT ;
    USE SIGNAL ;
    PORT
      LAYER M4 ;
        RECT  36.528 6.192 36.72 6.216 ;
    END
  END dq[11]
  PIN dq[120]
    DIRECTION OUTPUT ;
    USE SIGNAL ;
    PORT
      LAYER M4 ;
        RECT  36.528 23.856 36.72 23.88 ;
    END
  END dq[120]
  PIN dq[121]
    DIRECTION OUTPUT ;
    USE SIGNAL ;
    PORT
      LAYER M4 ;
        RECT  36.528 24 36.72 24.024 ;
    END
  END dq[121]
  PIN dq[122]
    DIRECTION OUTPUT ;
    USE SIGNAL ;
    PORT
      LAYER M4 ;
        RECT  36.528 24.192 36.72 24.216 ;
    END
  END dq[122]
  PIN dq[123]
    DIRECTION OUTPUT ;
    USE SIGNAL ;
    PORT
      LAYER M4 ;
        RECT  36.528 24.336 36.72 24.36 ;
    END
  END dq[123]
  PIN dq[124]
    DIRECTION OUTPUT ;
    USE SIGNAL ;
    PORT
      LAYER M4 ;
        RECT  36.528 24.48 36.72 24.504 ;
    END
  END dq[124]
  PIN dq[125]
    DIRECTION OUTPUT ;
    USE SIGNAL ;
    PORT
      LAYER M4 ;
        RECT  36.528 24.672 36.72 24.696 ;
    END
  END dq[125]
  PIN dq[126]
    DIRECTION OUTPUT ;
    USE SIGNAL ;
    PORT
      LAYER M4 ;
        RECT  36.528 24.816 36.72 24.84 ;
    END
  END dq[126]
  PIN dq[127]
    DIRECTION OUTPUT ;
    USE SIGNAL ;
    PORT
      LAYER M4 ;
        RECT  36.528 25.008 36.72 25.032 ;
    END
  END dq[127]
  PIN dq[128]
    DIRECTION OUTPUT ;
    USE SIGNAL ;
    PORT
      LAYER M4 ;
        RECT  36.528 25.152 36.72 25.176 ;
    END
  END dq[128]
  PIN dq[129]
    DIRECTION OUTPUT ;
    USE SIGNAL ;
    PORT
      LAYER M4 ;
        RECT  36.528 25.296 36.72 25.32 ;
    END
  END dq[129]
  PIN dq[12]
    DIRECTION OUTPUT ;
    USE SIGNAL ;
    PORT
      LAYER M4 ;
        RECT  36.528 6.336 36.72 6.36 ;
    END
  END dq[12]
  PIN dq[130]
    DIRECTION OUTPUT ;
    USE SIGNAL ;
    PORT
      LAYER M4 ;
        RECT  36.528 25.488 36.72 25.512 ;
    END
  END dq[130]
  PIN dq[131]
    DIRECTION OUTPUT ;
    USE SIGNAL ;
    PORT
      LAYER M4 ;
        RECT  36.528 25.632 36.72 25.656 ;
    END
  END dq[131]
  PIN dq[132]
    DIRECTION OUTPUT ;
    USE SIGNAL ;
    PORT
      LAYER M4 ;
        RECT  36.528 25.776 36.72 25.8 ;
    END
  END dq[132]
  PIN dq[133]
    DIRECTION OUTPUT ;
    USE SIGNAL ;
    PORT
      LAYER M4 ;
        RECT  36.528 25.968 36.72 25.992 ;
    END
  END dq[133]
  PIN dq[134]
    DIRECTION OUTPUT ;
    USE SIGNAL ;
    PORT
      LAYER M4 ;
        RECT  36.528 26.112 36.72 26.136 ;
    END
  END dq[134]
  PIN dq[135]
    DIRECTION OUTPUT ;
    USE SIGNAL ;
    PORT
      LAYER M4 ;
        RECT  36.528 26.304 36.72 26.328 ;
    END
  END dq[135]
  PIN dq[136]
    DIRECTION OUTPUT ;
    USE SIGNAL ;
    PORT
      LAYER M4 ;
        RECT  36.528 26.448 36.72 26.472 ;
    END
  END dq[136]
  PIN dq[137]
    DIRECTION OUTPUT ;
    USE SIGNAL ;
    PORT
      LAYER M4 ;
        RECT  36.528 26.592 36.72 26.616 ;
    END
  END dq[137]
  PIN dq[138]
    DIRECTION OUTPUT ;
    USE SIGNAL ;
    PORT
      LAYER M4 ;
        RECT  36.528 26.784 36.72 26.808 ;
    END
  END dq[138]
  PIN dq[139]
    DIRECTION OUTPUT ;
    USE SIGNAL ;
    PORT
      LAYER M4 ;
        RECT  36.528 26.928 36.72 26.952 ;
    END
  END dq[139]
  PIN dq[13]
    DIRECTION OUTPUT ;
    USE SIGNAL ;
    PORT
      LAYER M4 ;
        RECT  36.528 6.528 36.72 6.552 ;
    END
  END dq[13]
  PIN dq[140]
    DIRECTION OUTPUT ;
    USE SIGNAL ;
    PORT
      LAYER M4 ;
        RECT  36.528 27.072 36.72 27.096 ;
    END
  END dq[140]
  PIN dq[141]
    DIRECTION OUTPUT ;
    USE SIGNAL ;
    PORT
      LAYER M4 ;
        RECT  36.528 27.264 36.72 27.288 ;
    END
  END dq[141]
  PIN dq[142]
    DIRECTION OUTPUT ;
    USE SIGNAL ;
    PORT
      LAYER M4 ;
        RECT  36.528 27.408 36.72 27.432 ;
    END
  END dq[142]
  PIN dq[143]
    DIRECTION OUTPUT ;
    USE SIGNAL ;
    PORT
      LAYER M4 ;
        RECT  36.528 27.6 36.72 27.624 ;
    END
  END dq[143]
  PIN dq[144]
    DIRECTION OUTPUT ;
    USE SIGNAL ;
    PORT
      LAYER M4 ;
        RECT  36.528 27.744 36.72 27.768 ;
    END
  END dq[144]
  PIN dq[145]
    DIRECTION OUTPUT ;
    USE SIGNAL ;
    PORT
      LAYER M4 ;
        RECT  36.528 27.888 36.72 27.912 ;
    END
  END dq[145]
  PIN dq[146]
    DIRECTION OUTPUT ;
    USE SIGNAL ;
    PORT
      LAYER M4 ;
        RECT  36.528 28.08 36.72 28.104 ;
    END
  END dq[146]
  PIN dq[147]
    DIRECTION OUTPUT ;
    USE SIGNAL ;
    PORT
      LAYER M4 ;
        RECT  36.528 28.224 36.72 28.248 ;
    END
  END dq[147]
  PIN dq[148]
    DIRECTION OUTPUT ;
    USE SIGNAL ;
    PORT
      LAYER M4 ;
        RECT  36.528 28.368 36.72 28.392 ;
    END
  END dq[148]
  PIN dq[149]
    DIRECTION OUTPUT ;
    USE SIGNAL ;
    PORT
      LAYER M4 ;
        RECT  36.528 28.56 36.72 28.584 ;
    END
  END dq[149]
  PIN dq[14]
    DIRECTION OUTPUT ;
    USE SIGNAL ;
    PORT
      LAYER M4 ;
        RECT  36.528 6.672 36.72 6.696 ;
    END
  END dq[14]
  PIN dq[150]
    DIRECTION OUTPUT ;
    USE SIGNAL ;
    PORT
      LAYER M4 ;
        RECT  36.528 28.704 36.72 28.728 ;
    END
  END dq[150]
  PIN dq[151]
    DIRECTION OUTPUT ;
    USE SIGNAL ;
    PORT
      LAYER M4 ;
        RECT  36.528 28.896 36.72 28.92 ;
    END
  END dq[151]
  PIN dq[152]
    DIRECTION OUTPUT ;
    USE SIGNAL ;
    PORT
      LAYER M4 ;
        RECT  36.528 29.04 36.72 29.064 ;
    END
  END dq[152]
  PIN dq[153]
    DIRECTION OUTPUT ;
    USE SIGNAL ;
    PORT
      LAYER M4 ;
        RECT  36.528 29.184 36.72 29.208 ;
    END
  END dq[153]
  PIN dq[154]
    DIRECTION OUTPUT ;
    USE SIGNAL ;
    PORT
      LAYER M4 ;
        RECT  36.528 29.376 36.72 29.4 ;
    END
  END dq[154]
  PIN dq[155]
    DIRECTION OUTPUT ;
    USE SIGNAL ;
    PORT
      LAYER M4 ;
        RECT  36.528 29.52 36.72 29.544 ;
    END
  END dq[155]
  PIN dq[156]
    DIRECTION OUTPUT ;
    USE SIGNAL ;
    PORT
      LAYER M4 ;
        RECT  36.528 29.664 36.72 29.688 ;
    END
  END dq[156]
  PIN dq[157]
    DIRECTION OUTPUT ;
    USE SIGNAL ;
    PORT
      LAYER M4 ;
        RECT  36.528 29.856 36.72 29.88 ;
    END
  END dq[157]
  PIN dq[158]
    DIRECTION OUTPUT ;
    USE SIGNAL ;
    PORT
      LAYER M4 ;
        RECT  36.528 30 36.72 30.024 ;
    END
  END dq[158]
  PIN dq[159]
    DIRECTION OUTPUT ;
    USE SIGNAL ;
    PORT
      LAYER M4 ;
        RECT  36.528 30.192 36.72 30.216 ;
    END
  END dq[159]
  PIN dq[15]
    DIRECTION OUTPUT ;
    USE SIGNAL ;
    PORT
      LAYER M4 ;
        RECT  36.528 6.864 36.72 6.888 ;
    END
  END dq[15]
  PIN dq[160]
    DIRECTION OUTPUT ;
    USE SIGNAL ;
    PORT
      LAYER M4 ;
        RECT  36.528 30.336 36.72 30.36 ;
    END
  END dq[160]
  PIN dq[161]
    DIRECTION OUTPUT ;
    USE SIGNAL ;
    PORT
      LAYER M4 ;
        RECT  36.528 30.48 36.72 30.504 ;
    END
  END dq[161]
  PIN dq[162]
    DIRECTION OUTPUT ;
    USE SIGNAL ;
    PORT
      LAYER M4 ;
        RECT  36.528 30.672 36.72 30.696 ;
    END
  END dq[162]
  PIN dq[163]
    DIRECTION OUTPUT ;
    USE SIGNAL ;
    PORT
      LAYER M4 ;
        RECT  36.528 30.816 36.72 30.84 ;
    END
  END dq[163]
  PIN dq[164]
    DIRECTION OUTPUT ;
    USE SIGNAL ;
    PORT
      LAYER M4 ;
        RECT  36.528 30.96 36.72 30.984 ;
    END
  END dq[164]
  PIN dq[165]
    DIRECTION OUTPUT ;
    USE SIGNAL ;
    PORT
      LAYER M4 ;
        RECT  36.528 31.152 36.72 31.176 ;
    END
  END dq[165]
  PIN dq[166]
    DIRECTION OUTPUT ;
    USE SIGNAL ;
    PORT
      LAYER M4 ;
        RECT  36.528 31.296 36.72 31.32 ;
    END
  END dq[166]
  PIN dq[167]
    DIRECTION OUTPUT ;
    USE SIGNAL ;
    PORT
      LAYER M4 ;
        RECT  36.528 31.488 36.72 31.512 ;
    END
  END dq[167]
  PIN dq[168]
    DIRECTION OUTPUT ;
    USE SIGNAL ;
    PORT
      LAYER M4 ;
        RECT  36.528 31.632 36.72 31.656 ;
    END
  END dq[168]
  PIN dq[169]
    DIRECTION OUTPUT ;
    USE SIGNAL ;
    PORT
      LAYER M4 ;
        RECT  36.528 31.776 36.72 31.8 ;
    END
  END dq[169]
  PIN dq[16]
    DIRECTION OUTPUT ;
    USE SIGNAL ;
    PORT
      LAYER M4 ;
        RECT  36.528 7.008 36.72 7.032 ;
    END
  END dq[16]
  PIN dq[170]
    DIRECTION OUTPUT ;
    USE SIGNAL ;
    PORT
      LAYER M4 ;
        RECT  36.528 31.968 36.72 31.992 ;
    END
  END dq[170]
  PIN dq[171]
    DIRECTION OUTPUT ;
    USE SIGNAL ;
    PORT
      LAYER M4 ;
        RECT  36.528 32.112 36.72 32.136 ;
    END
  END dq[171]
  PIN dq[172]
    DIRECTION OUTPUT ;
    USE SIGNAL ;
    PORT
      LAYER M4 ;
        RECT  36.528 32.256 36.72 32.28 ;
    END
  END dq[172]
  PIN dq[173]
    DIRECTION OUTPUT ;
    USE SIGNAL ;
    PORT
      LAYER M4 ;
        RECT  36.528 32.448 36.72 32.472 ;
    END
  END dq[173]
  PIN dq[174]
    DIRECTION OUTPUT ;
    USE SIGNAL ;
    PORT
      LAYER M4 ;
        RECT  36.528 32.592 36.72 32.616 ;
    END
  END dq[174]
  PIN dq[175]
    DIRECTION OUTPUT ;
    USE SIGNAL ;
    PORT
      LAYER M4 ;
        RECT  36.528 32.784 36.72 32.808 ;
    END
  END dq[175]
  PIN dq[176]
    DIRECTION OUTPUT ;
    USE SIGNAL ;
    PORT
      LAYER M4 ;
        RECT  36.528 32.928 36.72 32.952 ;
    END
  END dq[176]
  PIN dq[177]
    DIRECTION OUTPUT ;
    USE SIGNAL ;
    PORT
      LAYER M4 ;
        RECT  36.528 33.072 36.72 33.096 ;
    END
  END dq[177]
  PIN dq[178]
    DIRECTION OUTPUT ;
    USE SIGNAL ;
    PORT
      LAYER M4 ;
        RECT  36.528 33.264 36.72 33.288 ;
    END
  END dq[178]
  PIN dq[179]
    DIRECTION OUTPUT ;
    USE SIGNAL ;
    PORT
      LAYER M4 ;
        RECT  36.528 33.408 36.72 33.432 ;
    END
  END dq[179]
  PIN dq[17]
    DIRECTION OUTPUT ;
    USE SIGNAL ;
    PORT
      LAYER M4 ;
        RECT  36.528 7.152 36.72 7.176 ;
    END
  END dq[17]
  PIN dq[180]
    DIRECTION OUTPUT ;
    USE SIGNAL ;
    PORT
      LAYER M4 ;
        RECT  36.528 33.552 36.72 33.576 ;
    END
  END dq[180]
  PIN dq[181]
    DIRECTION OUTPUT ;
    USE SIGNAL ;
    PORT
      LAYER M4 ;
        RECT  36.528 33.744 36.72 33.768 ;
    END
  END dq[181]
  PIN dq[182]
    DIRECTION OUTPUT ;
    USE SIGNAL ;
    PORT
      LAYER M4 ;
        RECT  36.528 33.888 36.72 33.912 ;
    END
  END dq[182]
  PIN dq[183]
    DIRECTION OUTPUT ;
    USE SIGNAL ;
    PORT
      LAYER M4 ;
        RECT  36.528 34.08 36.72 34.104 ;
    END
  END dq[183]
  PIN dq[184]
    DIRECTION OUTPUT ;
    USE SIGNAL ;
    PORT
      LAYER M4 ;
        RECT  36.528 34.224 36.72 34.248 ;
    END
  END dq[184]
  PIN dq[185]
    DIRECTION OUTPUT ;
    USE SIGNAL ;
    PORT
      LAYER M4 ;
        RECT  36.528 34.368 36.72 34.392 ;
    END
  END dq[185]
  PIN dq[186]
    DIRECTION OUTPUT ;
    USE SIGNAL ;
    PORT
      LAYER M4 ;
        RECT  36.528 34.56 36.72 34.584 ;
    END
  END dq[186]
  PIN dq[187]
    DIRECTION OUTPUT ;
    USE SIGNAL ;
    PORT
      LAYER M4 ;
        RECT  36.528 34.704 36.72 34.728 ;
    END
  END dq[187]
  PIN dq[188]
    DIRECTION OUTPUT ;
    USE SIGNAL ;
    PORT
      LAYER M4 ;
        RECT  36.528 34.848 36.72 34.872 ;
    END
  END dq[188]
  PIN dq[189]
    DIRECTION OUTPUT ;
    USE SIGNAL ;
    PORT
      LAYER M4 ;
        RECT  36.528 35.04 36.72 35.064 ;
    END
  END dq[189]
  PIN dq[18]
    DIRECTION OUTPUT ;
    USE SIGNAL ;
    PORT
      LAYER M4 ;
        RECT  36.528 7.344 36.72 7.368 ;
    END
  END dq[18]
  PIN dq[190]
    DIRECTION OUTPUT ;
    USE SIGNAL ;
    PORT
      LAYER M4 ;
        RECT  36.528 35.184 36.72 35.208 ;
    END
  END dq[190]
  PIN dq[191]
    DIRECTION OUTPUT ;
    USE SIGNAL ;
    PORT
      LAYER M4 ;
        RECT  36.528 35.376 36.72 35.4 ;
    END
  END dq[191]
  PIN dq[192]
    DIRECTION OUTPUT ;
    USE SIGNAL ;
    PORT
      LAYER M4 ;
        RECT  36.528 35.52 36.72 35.544 ;
    END
  END dq[192]
  PIN dq[193]
    DIRECTION OUTPUT ;
    USE SIGNAL ;
    PORT
      LAYER M4 ;
        RECT  36.528 35.664 36.72 35.688 ;
    END
  END dq[193]
  PIN dq[194]
    DIRECTION OUTPUT ;
    USE SIGNAL ;
    PORT
      LAYER M4 ;
        RECT  36.528 35.856 36.72 35.88 ;
    END
  END dq[194]
  PIN dq[195]
    DIRECTION OUTPUT ;
    USE SIGNAL ;
    PORT
      LAYER M4 ;
        RECT  36.528 36 36.72 36.024 ;
    END
  END dq[195]
  PIN dq[196]
    DIRECTION OUTPUT ;
    USE SIGNAL ;
    PORT
      LAYER M4 ;
        RECT  36.528 36.144 36.72 36.168 ;
    END
  END dq[196]
  PIN dq[197]
    DIRECTION OUTPUT ;
    USE SIGNAL ;
    PORT
      LAYER M4 ;
        RECT  36.528 36.336 36.72 36.36 ;
    END
  END dq[197]
  PIN dq[198]
    DIRECTION OUTPUT ;
    USE SIGNAL ;
    PORT
      LAYER M4 ;
        RECT  36.528 36.48 36.72 36.504 ;
    END
  END dq[198]
  PIN dq[199]
    DIRECTION OUTPUT ;
    USE SIGNAL ;
    PORT
      LAYER M4 ;
        RECT  36.528 36.672 36.72 36.696 ;
    END
  END dq[199]
  PIN dq[19]
    DIRECTION OUTPUT ;
    USE SIGNAL ;
    PORT
      LAYER M4 ;
        RECT  36.528 7.488 36.72 7.512 ;
    END
  END dq[19]
  PIN dq[1]
    DIRECTION OUTPUT ;
    USE SIGNAL ;
    PORT
      LAYER M4 ;
        RECT  36.528 4.56 36.72 4.584 ;
    END
  END dq[1]
  PIN dq[200]
    DIRECTION OUTPUT ;
    USE SIGNAL ;
    PORT
      LAYER M4 ;
        RECT  36.528 36.816 36.72 36.84 ;
    END
  END dq[200]
  PIN dq[201]
    DIRECTION OUTPUT ;
    USE SIGNAL ;
    PORT
      LAYER M4 ;
        RECT  36.528 36.96 36.72 36.984 ;
    END
  END dq[201]
  PIN dq[202]
    DIRECTION OUTPUT ;
    USE SIGNAL ;
    PORT
      LAYER M4 ;
        RECT  36.528 37.152 36.72 37.176 ;
    END
  END dq[202]
  PIN dq[203]
    DIRECTION OUTPUT ;
    USE SIGNAL ;
    PORT
      LAYER M4 ;
        RECT  36.528 37.296 36.72 37.32 ;
    END
  END dq[203]
  PIN dq[204]
    DIRECTION OUTPUT ;
    USE SIGNAL ;
    PORT
      LAYER M4 ;
        RECT  36.528 37.44 36.72 37.464 ;
    END
  END dq[204]
  PIN dq[205]
    DIRECTION OUTPUT ;
    USE SIGNAL ;
    PORT
      LAYER M4 ;
        RECT  36.528 37.632 36.72 37.656 ;
    END
  END dq[205]
  PIN dq[206]
    DIRECTION OUTPUT ;
    USE SIGNAL ;
    PORT
      LAYER M4 ;
        RECT  36.528 37.776 36.72 37.8 ;
    END
  END dq[206]
  PIN dq[207]
    DIRECTION OUTPUT ;
    USE SIGNAL ;
    PORT
      LAYER M4 ;
        RECT  36.528 37.968 36.72 37.992 ;
    END
  END dq[207]
  PIN dq[208]
    DIRECTION OUTPUT ;
    USE SIGNAL ;
    PORT
      LAYER M4 ;
        RECT  36.528 38.112 36.72 38.136 ;
    END
  END dq[208]
  PIN dq[209]
    DIRECTION OUTPUT ;
    USE SIGNAL ;
    PORT
      LAYER M4 ;
        RECT  36.528 38.256 36.72 38.28 ;
    END
  END dq[209]
  PIN dq[20]
    DIRECTION OUTPUT ;
    USE SIGNAL ;
    PORT
      LAYER M4 ;
        RECT  36.528 7.632 36.72 7.656 ;
    END
  END dq[20]
  PIN dq[210]
    DIRECTION OUTPUT ;
    USE SIGNAL ;
    PORT
      LAYER M4 ;
        RECT  36.528 38.448 36.72 38.472 ;
    END
  END dq[210]
  PIN dq[211]
    DIRECTION OUTPUT ;
    USE SIGNAL ;
    PORT
      LAYER M4 ;
        RECT  36.528 38.592 36.72 38.616 ;
    END
  END dq[211]
  PIN dq[212]
    DIRECTION OUTPUT ;
    USE SIGNAL ;
    PORT
      LAYER M4 ;
        RECT  36.528 38.736 36.72 38.76 ;
    END
  END dq[212]
  PIN dq[213]
    DIRECTION OUTPUT ;
    USE SIGNAL ;
    PORT
      LAYER M4 ;
        RECT  36.528 38.928 36.72 38.952 ;
    END
  END dq[213]
  PIN dq[214]
    DIRECTION OUTPUT ;
    USE SIGNAL ;
    PORT
      LAYER M4 ;
        RECT  36.528 39.072 36.72 39.096 ;
    END
  END dq[214]
  PIN dq[215]
    DIRECTION OUTPUT ;
    USE SIGNAL ;
    PORT
      LAYER M4 ;
        RECT  36.528 39.264 36.72 39.288 ;
    END
  END dq[215]
  PIN dq[216]
    DIRECTION OUTPUT ;
    USE SIGNAL ;
    PORT
      LAYER M4 ;
        RECT  36.528 39.408 36.72 39.432 ;
    END
  END dq[216]
  PIN dq[217]
    DIRECTION OUTPUT ;
    USE SIGNAL ;
    PORT
      LAYER M4 ;
        RECT  36.528 39.552 36.72 39.576 ;
    END
  END dq[217]
  PIN dq[218]
    DIRECTION OUTPUT ;
    USE SIGNAL ;
    PORT
      LAYER M4 ;
        RECT  36.528 39.744 36.72 39.768 ;
    END
  END dq[218]
  PIN dq[219]
    DIRECTION OUTPUT ;
    USE SIGNAL ;
    PORT
      LAYER M4 ;
        RECT  36.528 39.888 36.72 39.912 ;
    END
  END dq[219]
  PIN dq[21]
    DIRECTION OUTPUT ;
    USE SIGNAL ;
    PORT
      LAYER M4 ;
        RECT  36.528 7.824 36.72 7.848 ;
    END
  END dq[21]
  PIN dq[220]
    DIRECTION OUTPUT ;
    USE SIGNAL ;
    PORT
      LAYER M4 ;
        RECT  36.528 40.032 36.72 40.056 ;
    END
  END dq[220]
  PIN dq[221]
    DIRECTION OUTPUT ;
    USE SIGNAL ;
    PORT
      LAYER M4 ;
        RECT  36.528 40.224 36.72 40.248 ;
    END
  END dq[221]
  PIN dq[222]
    DIRECTION OUTPUT ;
    USE SIGNAL ;
    PORT
      LAYER M4 ;
        RECT  36.528 40.368 36.72 40.392 ;
    END
  END dq[222]
  PIN dq[223]
    DIRECTION OUTPUT ;
    USE SIGNAL ;
    PORT
      LAYER M4 ;
        RECT  36.528 40.56 36.72 40.584 ;
    END
  END dq[223]
  PIN dq[224]
    DIRECTION OUTPUT ;
    USE SIGNAL ;
    PORT
      LAYER M4 ;
        RECT  36.528 40.704 36.72 40.728 ;
    END
  END dq[224]
  PIN dq[225]
    DIRECTION OUTPUT ;
    USE SIGNAL ;
    PORT
      LAYER M4 ;
        RECT  36.528 40.848 36.72 40.872 ;
    END
  END dq[225]
  PIN dq[226]
    DIRECTION OUTPUT ;
    USE SIGNAL ;
    PORT
      LAYER M4 ;
        RECT  36.528 41.04 36.72 41.064 ;
    END
  END dq[226]
  PIN dq[227]
    DIRECTION OUTPUT ;
    USE SIGNAL ;
    PORT
      LAYER M4 ;
        RECT  36.528 41.184 36.72 41.208 ;
    END
  END dq[227]
  PIN dq[228]
    DIRECTION OUTPUT ;
    USE SIGNAL ;
    PORT
      LAYER M4 ;
        RECT  36.528 41.328 36.72 41.352 ;
    END
  END dq[228]
  PIN dq[229]
    DIRECTION OUTPUT ;
    USE SIGNAL ;
    PORT
      LAYER M4 ;
        RECT  36.528 41.52 36.72 41.544 ;
    END
  END dq[229]
  PIN dq[22]
    DIRECTION OUTPUT ;
    USE SIGNAL ;
    PORT
      LAYER M4 ;
        RECT  36.528 7.968 36.72 7.992 ;
    END
  END dq[22]
  PIN dq[230]
    DIRECTION OUTPUT ;
    USE SIGNAL ;
    PORT
      LAYER M4 ;
        RECT  36.528 41.664 36.72 41.688 ;
    END
  END dq[230]
  PIN dq[231]
    DIRECTION OUTPUT ;
    USE SIGNAL ;
    PORT
      LAYER M4 ;
        RECT  36.528 41.856 36.72 41.88 ;
    END
  END dq[231]
  PIN dq[232]
    DIRECTION OUTPUT ;
    USE SIGNAL ;
    PORT
      LAYER M4 ;
        RECT  36.528 42 36.72 42.024 ;
    END
  END dq[232]
  PIN dq[233]
    DIRECTION OUTPUT ;
    USE SIGNAL ;
    PORT
      LAYER M4 ;
        RECT  36.528 42.144 36.72 42.168 ;
    END
  END dq[233]
  PIN dq[234]
    DIRECTION OUTPUT ;
    USE SIGNAL ;
    PORT
      LAYER M4 ;
        RECT  36.528 42.336 36.72 42.36 ;
    END
  END dq[234]
  PIN dq[235]
    DIRECTION OUTPUT ;
    USE SIGNAL ;
    PORT
      LAYER M4 ;
        RECT  36.528 42.48 36.72 42.504 ;
    END
  END dq[235]
  PIN dq[236]
    DIRECTION OUTPUT ;
    USE SIGNAL ;
    PORT
      LAYER M4 ;
        RECT  36.528 42.624 36.72 42.648 ;
    END
  END dq[236]
  PIN dq[237]
    DIRECTION OUTPUT ;
    USE SIGNAL ;
    PORT
      LAYER M4 ;
        RECT  36.528 42.816 36.72 42.84 ;
    END
  END dq[237]
  PIN dq[238]
    DIRECTION OUTPUT ;
    USE SIGNAL ;
    PORT
      LAYER M4 ;
        RECT  36.528 42.96 36.72 42.984 ;
    END
  END dq[238]
  PIN dq[239]
    DIRECTION OUTPUT ;
    USE SIGNAL ;
    PORT
      LAYER M4 ;
        RECT  36.528 43.152 36.72 43.176 ;
    END
  END dq[239]
  PIN dq[23]
    DIRECTION OUTPUT ;
    USE SIGNAL ;
    PORT
      LAYER M4 ;
        RECT  36.528 8.16 36.72 8.184 ;
    END
  END dq[23]
  PIN dq[240]
    DIRECTION OUTPUT ;
    USE SIGNAL ;
    PORT
      LAYER M4 ;
        RECT  36.528 43.296 36.72 43.32 ;
    END
  END dq[240]
  PIN dq[241]
    DIRECTION OUTPUT ;
    USE SIGNAL ;
    PORT
      LAYER M4 ;
        RECT  36.528 43.44 36.72 43.464 ;
    END
  END dq[241]
  PIN dq[242]
    DIRECTION OUTPUT ;
    USE SIGNAL ;
    PORT
      LAYER M4 ;
        RECT  36.528 43.632 36.72 43.656 ;
    END
  END dq[242]
  PIN dq[243]
    DIRECTION OUTPUT ;
    USE SIGNAL ;
    PORT
      LAYER M4 ;
        RECT  36.528 43.776 36.72 43.8 ;
    END
  END dq[243]
  PIN dq[244]
    DIRECTION OUTPUT ;
    USE SIGNAL ;
    PORT
      LAYER M4 ;
        RECT  36.528 43.92 36.72 43.944 ;
    END
  END dq[244]
  PIN dq[245]
    DIRECTION OUTPUT ;
    USE SIGNAL ;
    PORT
      LAYER M4 ;
        RECT  36.528 44.112 36.72 44.136 ;
    END
  END dq[245]
  PIN dq[246]
    DIRECTION OUTPUT ;
    USE SIGNAL ;
    PORT
      LAYER M4 ;
        RECT  36.528 44.256 36.72 44.28 ;
    END
  END dq[246]
  PIN dq[247]
    DIRECTION OUTPUT ;
    USE SIGNAL ;
    PORT
      LAYER M4 ;
        RECT  36.528 44.448 36.72 44.472 ;
    END
  END dq[247]
  PIN dq[248]
    DIRECTION OUTPUT ;
    USE SIGNAL ;
    PORT
      LAYER M4 ;
        RECT  36.528 44.592 36.72 44.616 ;
    END
  END dq[248]
  PIN dq[249]
    DIRECTION OUTPUT ;
    USE SIGNAL ;
    PORT
      LAYER M4 ;
        RECT  36.528 44.736 36.72 44.76 ;
    END
  END dq[249]
  PIN dq[24]
    DIRECTION OUTPUT ;
    USE SIGNAL ;
    PORT
      LAYER M4 ;
        RECT  36.528 8.304 36.72 8.328 ;
    END
  END dq[24]
  PIN dq[250]
    DIRECTION OUTPUT ;
    USE SIGNAL ;
    PORT
      LAYER M4 ;
        RECT  36.528 44.928 36.72 44.952 ;
    END
  END dq[250]
  PIN dq[251]
    DIRECTION OUTPUT ;
    USE SIGNAL ;
    PORT
      LAYER M4 ;
        RECT  36.528 45.072 36.72 45.096 ;
    END
  END dq[251]
  PIN dq[252]
    DIRECTION OUTPUT ;
    USE SIGNAL ;
    PORT
      LAYER M4 ;
        RECT  36.528 45.216 36.72 45.24 ;
    END
  END dq[252]
  PIN dq[253]
    DIRECTION OUTPUT ;
    USE SIGNAL ;
    PORT
      LAYER M4 ;
        RECT  36.528 45.408 36.72 45.432 ;
    END
  END dq[253]
  PIN dq[254]
    DIRECTION OUTPUT ;
    USE SIGNAL ;
    PORT
      LAYER M4 ;
        RECT  36.528 45.552 36.72 45.576 ;
    END
  END dq[254]
  PIN dq[255]
    DIRECTION OUTPUT ;
    USE SIGNAL ;
    PORT
      LAYER M4 ;
        RECT  36.528 45.744 36.72 45.768 ;
    END
  END dq[255]
  PIN dq[256]
    DIRECTION OUTPUT ;
    USE SIGNAL ;
    PORT
      LAYER M4 ;
        RECT  36.528 45.888 36.72 45.912 ;
    END
  END dq[256]
  PIN dq[257]
    DIRECTION OUTPUT ;
    USE SIGNAL ;
    PORT
      LAYER M4 ;
        RECT  36.528 46.032 36.72 46.056 ;
    END
  END dq[257]
  PIN dq[258]
    DIRECTION OUTPUT ;
    USE SIGNAL ;
    PORT
      LAYER M4 ;
        RECT  36.528 46.224 36.72 46.248 ;
    END
  END dq[258]
  PIN dq[259]
    DIRECTION OUTPUT ;
    USE SIGNAL ;
    PORT
      LAYER M4 ;
        RECT  36.528 46.368 36.72 46.392 ;
    END
  END dq[259]
  PIN dq[25]
    DIRECTION OUTPUT ;
    USE SIGNAL ;
    PORT
      LAYER M4 ;
        RECT  36.528 8.448 36.72 8.472 ;
    END
  END dq[25]
  PIN dq[260]
    DIRECTION OUTPUT ;
    USE SIGNAL ;
    PORT
      LAYER M4 ;
        RECT  36.528 46.512 36.72 46.536 ;
    END
  END dq[260]
  PIN dq[261]
    DIRECTION OUTPUT ;
    USE SIGNAL ;
    PORT
      LAYER M4 ;
        RECT  36.528 46.704 36.72 46.728 ;
    END
  END dq[261]
  PIN dq[262]
    DIRECTION OUTPUT ;
    USE SIGNAL ;
    PORT
      LAYER M4 ;
        RECT  36.528 46.848 36.72 46.872 ;
    END
  END dq[262]
  PIN dq[263]
    DIRECTION OUTPUT ;
    USE SIGNAL ;
    PORT
      LAYER M4 ;
        RECT  36.528 47.04 36.72 47.064 ;
    END
  END dq[263]
  PIN dq[264]
    DIRECTION OUTPUT ;
    USE SIGNAL ;
    PORT
      LAYER M4 ;
        RECT  36.528 47.184 36.72 47.208 ;
    END
  END dq[264]
  PIN dq[265]
    DIRECTION OUTPUT ;
    USE SIGNAL ;
    PORT
      LAYER M4 ;
        RECT  36.528 47.328 36.72 47.352 ;
    END
  END dq[265]
  PIN dq[266]
    DIRECTION OUTPUT ;
    USE SIGNAL ;
    PORT
      LAYER M4 ;
        RECT  36.528 47.52 36.72 47.544 ;
    END
  END dq[266]
  PIN dq[267]
    DIRECTION OUTPUT ;
    USE SIGNAL ;
    PORT
      LAYER M4 ;
        RECT  36.528 47.664 36.72 47.688 ;
    END
  END dq[267]
  PIN dq[268]
    DIRECTION OUTPUT ;
    USE SIGNAL ;
    PORT
      LAYER M4 ;
        RECT  36.528 47.808 36.72 47.832 ;
    END
  END dq[268]
  PIN dq[269]
    DIRECTION OUTPUT ;
    USE SIGNAL ;
    PORT
      LAYER M4 ;
        RECT  36.528 48 36.72 48.024 ;
    END
  END dq[269]
  PIN dq[26]
    DIRECTION OUTPUT ;
    USE SIGNAL ;
    PORT
      LAYER M4 ;
        RECT  36.528 8.64 36.72 8.664 ;
    END
  END dq[26]
  PIN dq[270]
    DIRECTION OUTPUT ;
    USE SIGNAL ;
    PORT
      LAYER M4 ;
        RECT  36.528 48.144 36.72 48.168 ;
    END
  END dq[270]
  PIN dq[271]
    DIRECTION OUTPUT ;
    USE SIGNAL ;
    PORT
      LAYER M4 ;
        RECT  36.528 48.336 36.72 48.36 ;
    END
  END dq[271]
  PIN dq[272]
    DIRECTION OUTPUT ;
    USE SIGNAL ;
    PORT
      LAYER M4 ;
        RECT  36.528 48.48 36.72 48.504 ;
    END
  END dq[272]
  PIN dq[273]
    DIRECTION OUTPUT ;
    USE SIGNAL ;
    PORT
      LAYER M4 ;
        RECT  36.528 48.624 36.72 48.648 ;
    END
  END dq[273]
  PIN dq[274]
    DIRECTION OUTPUT ;
    USE SIGNAL ;
    PORT
      LAYER M4 ;
        RECT  36.528 48.816 36.72 48.84 ;
    END
  END dq[274]
  PIN dq[275]
    DIRECTION OUTPUT ;
    USE SIGNAL ;
    PORT
      LAYER M4 ;
        RECT  36.528 48.96 36.72 48.984 ;
    END
  END dq[275]
  PIN dq[276]
    DIRECTION OUTPUT ;
    USE SIGNAL ;
    PORT
      LAYER M4 ;
        RECT  36.528 49.104 36.72 49.128 ;
    END
  END dq[276]
  PIN dq[277]
    DIRECTION OUTPUT ;
    USE SIGNAL ;
    PORT
      LAYER M4 ;
        RECT  36.528 49.296 36.72 49.32 ;
    END
  END dq[277]
  PIN dq[278]
    DIRECTION OUTPUT ;
    USE SIGNAL ;
    PORT
      LAYER M4 ;
        RECT  36.528 49.44 36.72 49.464 ;
    END
  END dq[278]
  PIN dq[279]
    DIRECTION OUTPUT ;
    USE SIGNAL ;
    PORT
      LAYER M4 ;
        RECT  36.528 49.632 36.72 49.656 ;
    END
  END dq[279]
  PIN dq[27]
    DIRECTION OUTPUT ;
    USE SIGNAL ;
    PORT
      LAYER M4 ;
        RECT  36.528 8.784 36.72 8.808 ;
    END
  END dq[27]
  PIN dq[280]
    DIRECTION OUTPUT ;
    USE SIGNAL ;
    PORT
      LAYER M4 ;
        RECT  36.528 49.776 36.72 49.8 ;
    END
  END dq[280]
  PIN dq[281]
    DIRECTION OUTPUT ;
    USE SIGNAL ;
    PORT
      LAYER M4 ;
        RECT  36.528 49.92 36.72 49.944 ;
    END
  END dq[281]
  PIN dq[282]
    DIRECTION OUTPUT ;
    USE SIGNAL ;
    PORT
      LAYER M4 ;
        RECT  36.528 50.112 36.72 50.136 ;
    END
  END dq[282]
  PIN dq[283]
    DIRECTION OUTPUT ;
    USE SIGNAL ;
    PORT
      LAYER M4 ;
        RECT  36.528 50.256 36.72 50.28 ;
    END
  END dq[283]
  PIN dq[284]
    DIRECTION OUTPUT ;
    USE SIGNAL ;
    PORT
      LAYER M4 ;
        RECT  36.528 50.4 36.72 50.424 ;
    END
  END dq[284]
  PIN dq[285]
    DIRECTION OUTPUT ;
    USE SIGNAL ;
    PORT
      LAYER M4 ;
        RECT  36.528 50.592 36.72 50.616 ;
    END
  END dq[285]
  PIN dq[286]
    DIRECTION OUTPUT ;
    USE SIGNAL ;
    PORT
      LAYER M4 ;
        RECT  36.528 50.736 36.72 50.76 ;
    END
  END dq[286]
  PIN dq[287]
    DIRECTION OUTPUT ;
    USE SIGNAL ;
    PORT
      LAYER M4 ;
        RECT  36.528 50.928 36.72 50.952 ;
    END
  END dq[287]
  PIN dq[288]
    DIRECTION OUTPUT ;
    USE SIGNAL ;
    PORT
      LAYER M4 ;
        RECT  36.528 51.072 36.72 51.096 ;
    END
  END dq[288]
  PIN dq[289]
    DIRECTION OUTPUT ;
    USE SIGNAL ;
    PORT
      LAYER M4 ;
        RECT  36.528 51.216 36.72 51.24 ;
    END
  END dq[289]
  PIN dq[28]
    DIRECTION OUTPUT ;
    USE SIGNAL ;
    PORT
      LAYER M4 ;
        RECT  36.528 8.928 36.72 8.952 ;
    END
  END dq[28]
  PIN dq[290]
    DIRECTION OUTPUT ;
    USE SIGNAL ;
    PORT
      LAYER M4 ;
        RECT  36.528 51.408 36.72 51.432 ;
    END
  END dq[290]
  PIN dq[291]
    DIRECTION OUTPUT ;
    USE SIGNAL ;
    PORT
      LAYER M4 ;
        RECT  36.528 51.552 36.72 51.576 ;
    END
  END dq[291]
  PIN dq[292]
    DIRECTION OUTPUT ;
    USE SIGNAL ;
    PORT
      LAYER M4 ;
        RECT  36.528 51.696 36.72 51.72 ;
    END
  END dq[292]
  PIN dq[293]
    DIRECTION OUTPUT ;
    USE SIGNAL ;
    PORT
      LAYER M4 ;
        RECT  36.528 51.888 36.72 51.912 ;
    END
  END dq[293]
  PIN dq[294]
    DIRECTION OUTPUT ;
    USE SIGNAL ;
    PORT
      LAYER M4 ;
        RECT  36.528 52.032 36.72 52.056 ;
    END
  END dq[294]
  PIN dq[295]
    DIRECTION OUTPUT ;
    USE SIGNAL ;
    PORT
      LAYER M4 ;
        RECT  36.528 52.224 36.72 52.248 ;
    END
  END dq[295]
  PIN dq[296]
    DIRECTION OUTPUT ;
    USE SIGNAL ;
    PORT
      LAYER M4 ;
        RECT  36.528 52.368 36.72 52.392 ;
    END
  END dq[296]
  PIN dq[297]
    DIRECTION OUTPUT ;
    USE SIGNAL ;
    PORT
      LAYER M4 ;
        RECT  36.528 52.512 36.72 52.536 ;
    END
  END dq[297]
  PIN dq[298]
    DIRECTION OUTPUT ;
    USE SIGNAL ;
    PORT
      LAYER M4 ;
        RECT  36.528 52.704 36.72 52.728 ;
    END
  END dq[298]
  PIN dq[299]
    DIRECTION OUTPUT ;
    USE SIGNAL ;
    PORT
      LAYER M4 ;
        RECT  36.528 52.848 36.72 52.872 ;
    END
  END dq[299]
  PIN dq[29]
    DIRECTION OUTPUT ;
    USE SIGNAL ;
    PORT
      LAYER M4 ;
        RECT  36.528 9.12 36.72 9.144 ;
    END
  END dq[29]
  PIN dq[2]
    DIRECTION OUTPUT ;
    USE SIGNAL ;
    PORT
      LAYER M4 ;
        RECT  36.528 4.752 36.72 4.776 ;
    END
  END dq[2]
  PIN dq[300]
    DIRECTION OUTPUT ;
    USE SIGNAL ;
    PORT
      LAYER M4 ;
        RECT  36.528 52.992 36.72 53.016 ;
    END
  END dq[300]
  PIN dq[301]
    DIRECTION OUTPUT ;
    USE SIGNAL ;
    PORT
      LAYER M4 ;
        RECT  36.528 53.184 36.72 53.208 ;
    END
  END dq[301]
  PIN dq[302]
    DIRECTION OUTPUT ;
    USE SIGNAL ;
    PORT
      LAYER M4 ;
        RECT  36.528 53.328 36.72 53.352 ;
    END
  END dq[302]
  PIN dq[303]
    DIRECTION OUTPUT ;
    USE SIGNAL ;
    PORT
      LAYER M4 ;
        RECT  36.528 53.52 36.72 53.544 ;
    END
  END dq[303]
  PIN dq[304]
    DIRECTION OUTPUT ;
    USE SIGNAL ;
    PORT
      LAYER M4 ;
        RECT  36.528 53.664 36.72 53.688 ;
    END
  END dq[304]
  PIN dq[305]
    DIRECTION OUTPUT ;
    USE SIGNAL ;
    PORT
      LAYER M4 ;
        RECT  36.528 53.808 36.72 53.832 ;
    END
  END dq[305]
  PIN dq[306]
    DIRECTION OUTPUT ;
    USE SIGNAL ;
    PORT
      LAYER M4 ;
        RECT  36.528 54 36.72 54.024 ;
    END
  END dq[306]
  PIN dq[307]
    DIRECTION OUTPUT ;
    USE SIGNAL ;
    PORT
      LAYER M4 ;
        RECT  36.528 54.144 36.72 54.168 ;
    END
  END dq[307]
  PIN dq[308]
    DIRECTION OUTPUT ;
    USE SIGNAL ;
    PORT
      LAYER M4 ;
        RECT  36.528 54.288 36.72 54.312 ;
    END
  END dq[308]
  PIN dq[309]
    DIRECTION OUTPUT ;
    USE SIGNAL ;
    PORT
      LAYER M4 ;
        RECT  36.528 54.48 36.72 54.504 ;
    END
  END dq[309]
  PIN dq[30]
    DIRECTION OUTPUT ;
    USE SIGNAL ;
    PORT
      LAYER M4 ;
        RECT  36.528 9.264 36.72 9.288 ;
    END
  END dq[30]
  PIN dq[310]
    DIRECTION OUTPUT ;
    USE SIGNAL ;
    PORT
      LAYER M4 ;
        RECT  36.528 54.624 36.72 54.648 ;
    END
  END dq[310]
  PIN dq[311]
    DIRECTION OUTPUT ;
    USE SIGNAL ;
    PORT
      LAYER M4 ;
        RECT  36.528 54.816 36.72 54.84 ;
    END
  END dq[311]
  PIN dq[312]
    DIRECTION OUTPUT ;
    USE SIGNAL ;
    PORT
      LAYER M4 ;
        RECT  36.528 54.96 36.72 54.984 ;
    END
  END dq[312]
  PIN dq[313]
    DIRECTION OUTPUT ;
    USE SIGNAL ;
    PORT
      LAYER M4 ;
        RECT  36.528 55.104 36.72 55.128 ;
    END
  END dq[313]
  PIN dq[314]
    DIRECTION OUTPUT ;
    USE SIGNAL ;
    PORT
      LAYER M4 ;
        RECT  36.528 55.296 36.72 55.32 ;
    END
  END dq[314]
  PIN dq[315]
    DIRECTION OUTPUT ;
    USE SIGNAL ;
    PORT
      LAYER M4 ;
        RECT  36.528 55.44 36.72 55.464 ;
    END
  END dq[315]
  PIN dq[316]
    DIRECTION OUTPUT ;
    USE SIGNAL ;
    PORT
      LAYER M4 ;
        RECT  36.528 55.584 36.72 55.608 ;
    END
  END dq[316]
  PIN dq[317]
    DIRECTION OUTPUT ;
    USE SIGNAL ;
    PORT
      LAYER M4 ;
        RECT  36.528 55.776 36.72 55.8 ;
    END
  END dq[317]
  PIN dq[318]
    DIRECTION OUTPUT ;
    USE SIGNAL ;
    PORT
      LAYER M4 ;
        RECT  36.528 55.92 36.72 55.944 ;
    END
  END dq[318]
  PIN dq[319]
    DIRECTION OUTPUT ;
    USE SIGNAL ;
    PORT
      LAYER M4 ;
        RECT  36.528 56.112 36.72 56.136 ;
    END
  END dq[319]
  PIN dq[31]
    DIRECTION OUTPUT ;
    USE SIGNAL ;
    PORT
      LAYER M4 ;
        RECT  36.528 9.456 36.72 9.48 ;
    END
  END dq[31]
  PIN dq[320]
    DIRECTION OUTPUT ;
    USE SIGNAL ;
    PORT
      LAYER M4 ;
        RECT  36.528 56.256 36.72 56.28 ;
    END
  END dq[320]
  PIN dq[321]
    DIRECTION OUTPUT ;
    USE SIGNAL ;
    PORT
      LAYER M4 ;
        RECT  36.528 56.4 36.72 56.424 ;
    END
  END dq[321]
  PIN dq[322]
    DIRECTION OUTPUT ;
    USE SIGNAL ;
    PORT
      LAYER M4 ;
        RECT  36.528 56.592 36.72 56.616 ;
    END
  END dq[322]
  PIN dq[323]
    DIRECTION OUTPUT ;
    USE SIGNAL ;
    PORT
      LAYER M4 ;
        RECT  36.528 56.736 36.72 56.76 ;
    END
  END dq[323]
  PIN dq[324]
    DIRECTION OUTPUT ;
    USE SIGNAL ;
    PORT
      LAYER M4 ;
        RECT  36.528 56.88 36.72 56.904 ;
    END
  END dq[324]
  PIN dq[325]
    DIRECTION OUTPUT ;
    USE SIGNAL ;
    PORT
      LAYER M4 ;
        RECT  36.528 57.072 36.72 57.096 ;
    END
  END dq[325]
  PIN dq[326]
    DIRECTION OUTPUT ;
    USE SIGNAL ;
    PORT
      LAYER M4 ;
        RECT  36.528 57.216 36.72 57.24 ;
    END
  END dq[326]
  PIN dq[327]
    DIRECTION OUTPUT ;
    USE SIGNAL ;
    PORT
      LAYER M4 ;
        RECT  36.528 57.408 36.72 57.432 ;
    END
  END dq[327]
  PIN dq[328]
    DIRECTION OUTPUT ;
    USE SIGNAL ;
    PORT
      LAYER M4 ;
        RECT  36.528 57.552 36.72 57.576 ;
    END
  END dq[328]
  PIN dq[329]
    DIRECTION OUTPUT ;
    USE SIGNAL ;
    PORT
      LAYER M4 ;
        RECT  36.528 57.696 36.72 57.72 ;
    END
  END dq[329]
  PIN dq[32]
    DIRECTION OUTPUT ;
    USE SIGNAL ;
    PORT
      LAYER M4 ;
        RECT  36.528 9.6 36.72 9.624 ;
    END
  END dq[32]
  PIN dq[330]
    DIRECTION OUTPUT ;
    USE SIGNAL ;
    PORT
      LAYER M4 ;
        RECT  36.528 57.888 36.72 57.912 ;
    END
  END dq[330]
  PIN dq[331]
    DIRECTION OUTPUT ;
    USE SIGNAL ;
    PORT
      LAYER M4 ;
        RECT  36.528 58.032 36.72 58.056 ;
    END
  END dq[331]
  PIN dq[332]
    DIRECTION OUTPUT ;
    USE SIGNAL ;
    PORT
      LAYER M4 ;
        RECT  36.528 58.176 36.72 58.2 ;
    END
  END dq[332]
  PIN dq[333]
    DIRECTION OUTPUT ;
    USE SIGNAL ;
    PORT
      LAYER M4 ;
        RECT  36.528 58.368 36.72 58.392 ;
    END
  END dq[333]
  PIN dq[334]
    DIRECTION OUTPUT ;
    USE SIGNAL ;
    PORT
      LAYER M4 ;
        RECT  36.528 58.512 36.72 58.536 ;
    END
  END dq[334]
  PIN dq[335]
    DIRECTION OUTPUT ;
    USE SIGNAL ;
    PORT
      LAYER M4 ;
        RECT  36.528 58.704 36.72 58.728 ;
    END
  END dq[335]
  PIN dq[336]
    DIRECTION OUTPUT ;
    USE SIGNAL ;
    PORT
      LAYER M4 ;
        RECT  36.528 58.848 36.72 58.872 ;
    END
  END dq[336]
  PIN dq[337]
    DIRECTION OUTPUT ;
    USE SIGNAL ;
    PORT
      LAYER M4 ;
        RECT  36.528 58.992 36.72 59.016 ;
    END
  END dq[337]
  PIN dq[338]
    DIRECTION OUTPUT ;
    USE SIGNAL ;
    PORT
      LAYER M4 ;
        RECT  36.528 59.184 36.72 59.208 ;
    END
  END dq[338]
  PIN dq[339]
    DIRECTION OUTPUT ;
    USE SIGNAL ;
    PORT
      LAYER M4 ;
        RECT  36.528 59.328 36.72 59.352 ;
    END
  END dq[339]
  PIN dq[33]
    DIRECTION OUTPUT ;
    USE SIGNAL ;
    PORT
      LAYER M4 ;
        RECT  36.528 9.744 36.72 9.768 ;
    END
  END dq[33]
  PIN dq[340]
    DIRECTION OUTPUT ;
    USE SIGNAL ;
    PORT
      LAYER M4 ;
        RECT  36.528 59.472 36.72 59.496 ;
    END
  END dq[340]
  PIN dq[341]
    DIRECTION OUTPUT ;
    USE SIGNAL ;
    PORT
      LAYER M4 ;
        RECT  36.528 59.664 36.72 59.688 ;
    END
  END dq[341]
  PIN dq[342]
    DIRECTION OUTPUT ;
    USE SIGNAL ;
    PORT
      LAYER M4 ;
        RECT  36.528 59.808 36.72 59.832 ;
    END
  END dq[342]
  PIN dq[343]
    DIRECTION OUTPUT ;
    USE SIGNAL ;
    PORT
      LAYER M4 ;
        RECT  36.528 60 36.72 60.024 ;
    END
  END dq[343]
  PIN dq[344]
    DIRECTION OUTPUT ;
    USE SIGNAL ;
    PORT
      LAYER M4 ;
        RECT  36.528 60.144 36.72 60.168 ;
    END
  END dq[344]
  PIN dq[345]
    DIRECTION OUTPUT ;
    USE SIGNAL ;
    PORT
      LAYER M4 ;
        RECT  36.528 60.288 36.72 60.312 ;
    END
  END dq[345]
  PIN dq[346]
    DIRECTION OUTPUT ;
    USE SIGNAL ;
    PORT
      LAYER M4 ;
        RECT  36.528 60.48 36.72 60.504 ;
    END
  END dq[346]
  PIN dq[347]
    DIRECTION OUTPUT ;
    USE SIGNAL ;
    PORT
      LAYER M4 ;
        RECT  36.528 60.624 36.72 60.648 ;
    END
  END dq[347]
  PIN dq[348]
    DIRECTION OUTPUT ;
    USE SIGNAL ;
    PORT
      LAYER M4 ;
        RECT  36.528 60.768 36.72 60.792 ;
    END
  END dq[348]
  PIN dq[349]
    DIRECTION OUTPUT ;
    USE SIGNAL ;
    PORT
      LAYER M4 ;
        RECT  36.528 60.96 36.72 60.984 ;
    END
  END dq[349]
  PIN dq[34]
    DIRECTION OUTPUT ;
    USE SIGNAL ;
    PORT
      LAYER M4 ;
        RECT  36.528 9.936 36.72 9.96 ;
    END
  END dq[34]
  PIN dq[350]
    DIRECTION OUTPUT ;
    USE SIGNAL ;
    PORT
      LAYER M4 ;
        RECT  36.528 61.104 36.72 61.128 ;
    END
  END dq[350]
  PIN dq[351]
    DIRECTION OUTPUT ;
    USE SIGNAL ;
    PORT
      LAYER M4 ;
        RECT  36.528 61.296 36.72 61.32 ;
    END
  END dq[351]
  PIN dq[352]
    DIRECTION OUTPUT ;
    USE SIGNAL ;
    PORT
      LAYER M4 ;
        RECT  36.528 61.44 36.72 61.464 ;
    END
  END dq[352]
  PIN dq[353]
    DIRECTION OUTPUT ;
    USE SIGNAL ;
    PORT
      LAYER M4 ;
        RECT  36.528 61.584 36.72 61.608 ;
    END
  END dq[353]
  PIN dq[354]
    DIRECTION OUTPUT ;
    USE SIGNAL ;
    PORT
      LAYER M4 ;
        RECT  36.528 61.776 36.72 61.8 ;
    END
  END dq[354]
  PIN dq[355]
    DIRECTION OUTPUT ;
    USE SIGNAL ;
    PORT
      LAYER M4 ;
        RECT  36.528 61.92 36.72 61.944 ;
    END
  END dq[355]
  PIN dq[356]
    DIRECTION OUTPUT ;
    USE SIGNAL ;
    PORT
      LAYER M4 ;
        RECT  36.528 62.064 36.72 62.088 ;
    END
  END dq[356]
  PIN dq[357]
    DIRECTION OUTPUT ;
    USE SIGNAL ;
    PORT
      LAYER M4 ;
        RECT  36.528 62.256 36.72 62.28 ;
    END
  END dq[357]
  PIN dq[358]
    DIRECTION OUTPUT ;
    USE SIGNAL ;
    PORT
      LAYER M4 ;
        RECT  36.528 62.4 36.72 62.424 ;
    END
  END dq[358]
  PIN dq[359]
    DIRECTION OUTPUT ;
    USE SIGNAL ;
    PORT
      LAYER M4 ;
        RECT  36.528 62.592 36.72 62.616 ;
    END
  END dq[359]
  PIN dq[35]
    DIRECTION OUTPUT ;
    USE SIGNAL ;
    PORT
      LAYER M4 ;
        RECT  36.528 10.08 36.72 10.104 ;
    END
  END dq[35]
  PIN dq[360]
    DIRECTION OUTPUT ;
    USE SIGNAL ;
    PORT
      LAYER M4 ;
        RECT  36.528 62.736 36.72 62.76 ;
    END
  END dq[360]
  PIN dq[361]
    DIRECTION OUTPUT ;
    USE SIGNAL ;
    PORT
      LAYER M4 ;
        RECT  36.528 62.88 36.72 62.904 ;
    END
  END dq[361]
  PIN dq[362]
    DIRECTION OUTPUT ;
    USE SIGNAL ;
    PORT
      LAYER M4 ;
        RECT  36.528 63.072 36.72 63.096 ;
    END
  END dq[362]
  PIN dq[363]
    DIRECTION OUTPUT ;
    USE SIGNAL ;
    PORT
      LAYER M4 ;
        RECT  36.528 63.216 36.72 63.24 ;
    END
  END dq[363]
  PIN dq[364]
    DIRECTION OUTPUT ;
    USE SIGNAL ;
    PORT
      LAYER M4 ;
        RECT  36.528 63.36 36.72 63.384 ;
    END
  END dq[364]
  PIN dq[365]
    DIRECTION OUTPUT ;
    USE SIGNAL ;
    PORT
      LAYER M4 ;
        RECT  36.528 63.552 36.72 63.576 ;
    END
  END dq[365]
  PIN dq[366]
    DIRECTION OUTPUT ;
    USE SIGNAL ;
    PORT
      LAYER M4 ;
        RECT  36.528 63.696 36.72 63.72 ;
    END
  END dq[366]
  PIN dq[367]
    DIRECTION OUTPUT ;
    USE SIGNAL ;
    PORT
      LAYER M4 ;
        RECT  36.528 63.888 36.72 63.912 ;
    END
  END dq[367]
  PIN dq[368]
    DIRECTION OUTPUT ;
    USE SIGNAL ;
    PORT
      LAYER M4 ;
        RECT  36.528 64.032 36.72 64.056 ;
    END
  END dq[368]
  PIN dq[369]
    DIRECTION OUTPUT ;
    USE SIGNAL ;
    PORT
      LAYER M4 ;
        RECT  36.528 64.176 36.72 64.2 ;
    END
  END dq[369]
  PIN dq[36]
    DIRECTION OUTPUT ;
    USE SIGNAL ;
    PORT
      LAYER M4 ;
        RECT  36.528 10.224 36.72 10.248 ;
    END
  END dq[36]
  PIN dq[370]
    DIRECTION OUTPUT ;
    USE SIGNAL ;
    PORT
      LAYER M4 ;
        RECT  36.528 64.368 36.72 64.392 ;
    END
  END dq[370]
  PIN dq[371]
    DIRECTION OUTPUT ;
    USE SIGNAL ;
    PORT
      LAYER M4 ;
        RECT  36.528 64.512 36.72 64.536 ;
    END
  END dq[371]
  PIN dq[372]
    DIRECTION OUTPUT ;
    USE SIGNAL ;
    PORT
      LAYER M4 ;
        RECT  36.528 64.656 36.72 64.68 ;
    END
  END dq[372]
  PIN dq[373]
    DIRECTION OUTPUT ;
    USE SIGNAL ;
    PORT
      LAYER M4 ;
        RECT  36.528 64.848 36.72 64.872 ;
    END
  END dq[373]
  PIN dq[374]
    DIRECTION OUTPUT ;
    USE SIGNAL ;
    PORT
      LAYER M4 ;
        RECT  36.528 64.992 36.72 65.016 ;
    END
  END dq[374]
  PIN dq[375]
    DIRECTION OUTPUT ;
    USE SIGNAL ;
    PORT
      LAYER M4 ;
        RECT  36.528 65.184 36.72 65.208 ;
    END
  END dq[375]
  PIN dq[376]
    DIRECTION OUTPUT ;
    USE SIGNAL ;
    PORT
      LAYER M4 ;
        RECT  36.528 65.328 36.72 65.352 ;
    END
  END dq[376]
  PIN dq[377]
    DIRECTION OUTPUT ;
    USE SIGNAL ;
    PORT
      LAYER M4 ;
        RECT  36.528 65.472 36.72 65.496 ;
    END
  END dq[377]
  PIN dq[378]
    DIRECTION OUTPUT ;
    USE SIGNAL ;
    PORT
      LAYER M4 ;
        RECT  36.528 65.664 36.72 65.688 ;
    END
  END dq[378]
  PIN dq[379]
    DIRECTION OUTPUT ;
    USE SIGNAL ;
    PORT
      LAYER M4 ;
        RECT  36.528 65.808 36.72 65.832 ;
    END
  END dq[379]
  PIN dq[37]
    DIRECTION OUTPUT ;
    USE SIGNAL ;
    PORT
      LAYER M4 ;
        RECT  36.528 10.416 36.72 10.44 ;
    END
  END dq[37]
  PIN dq[380]
    DIRECTION OUTPUT ;
    USE SIGNAL ;
    PORT
      LAYER M4 ;
        RECT  36.528 65.952 36.72 65.976 ;
    END
  END dq[380]
  PIN dq[381]
    DIRECTION OUTPUT ;
    USE SIGNAL ;
    PORT
      LAYER M4 ;
        RECT  36.528 66.144 36.72 66.168 ;
    END
  END dq[381]
  PIN dq[382]
    DIRECTION OUTPUT ;
    USE SIGNAL ;
    PORT
      LAYER M4 ;
        RECT  36.528 66.288 36.72 66.312 ;
    END
  END dq[382]
  PIN dq[383]
    DIRECTION OUTPUT ;
    USE SIGNAL ;
    PORT
      LAYER M4 ;
        RECT  36.528 66.48 36.72 66.504 ;
    END
  END dq[383]
  PIN dq[384]
    DIRECTION OUTPUT ;
    USE SIGNAL ;
    PORT
      LAYER M4 ;
        RECT  36.528 66.624 36.72 66.648 ;
    END
  END dq[384]
  PIN dq[385]
    DIRECTION OUTPUT ;
    USE SIGNAL ;
    PORT
      LAYER M4 ;
        RECT  36.528 66.768 36.72 66.792 ;
    END
  END dq[385]
  PIN dq[386]
    DIRECTION OUTPUT ;
    USE SIGNAL ;
    PORT
      LAYER M4 ;
        RECT  36.528 66.96 36.72 66.984 ;
    END
  END dq[386]
  PIN dq[387]
    DIRECTION OUTPUT ;
    USE SIGNAL ;
    PORT
      LAYER M4 ;
        RECT  36.528 67.104 36.72 67.128 ;
    END
  END dq[387]
  PIN dq[388]
    DIRECTION OUTPUT ;
    USE SIGNAL ;
    PORT
      LAYER M4 ;
        RECT  36.528 67.248 36.72 67.272 ;
    END
  END dq[388]
  PIN dq[389]
    DIRECTION OUTPUT ;
    USE SIGNAL ;
    PORT
      LAYER M4 ;
        RECT  36.528 67.44 36.72 67.464 ;
    END
  END dq[389]
  PIN dq[38]
    DIRECTION OUTPUT ;
    USE SIGNAL ;
    PORT
      LAYER M4 ;
        RECT  36.528 10.56 36.72 10.584 ;
    END
  END dq[38]
  PIN dq[390]
    DIRECTION OUTPUT ;
    USE SIGNAL ;
    PORT
      LAYER M4 ;
        RECT  36.528 67.584 36.72 67.608 ;
    END
  END dq[390]
  PIN dq[391]
    DIRECTION OUTPUT ;
    USE SIGNAL ;
    PORT
      LAYER M4 ;
        RECT  36.528 67.776 36.72 67.8 ;
    END
  END dq[391]
  PIN dq[392]
    DIRECTION OUTPUT ;
    USE SIGNAL ;
    PORT
      LAYER M4 ;
        RECT  36.528 67.92 36.72 67.944 ;
    END
  END dq[392]
  PIN dq[393]
    DIRECTION OUTPUT ;
    USE SIGNAL ;
    PORT
      LAYER M4 ;
        RECT  36.528 68.064 36.72 68.088 ;
    END
  END dq[393]
  PIN dq[394]
    DIRECTION OUTPUT ;
    USE SIGNAL ;
    PORT
      LAYER M4 ;
        RECT  36.528 68.256 36.72 68.28 ;
    END
  END dq[394]
  PIN dq[395]
    DIRECTION OUTPUT ;
    USE SIGNAL ;
    PORT
      LAYER M4 ;
        RECT  36.528 68.4 36.72 68.424 ;
    END
  END dq[395]
  PIN dq[396]
    DIRECTION OUTPUT ;
    USE SIGNAL ;
    PORT
      LAYER M4 ;
        RECT  36.528 68.544 36.72 68.568 ;
    END
  END dq[396]
  PIN dq[397]
    DIRECTION OUTPUT ;
    USE SIGNAL ;
    PORT
      LAYER M4 ;
        RECT  36.528 68.736 36.72 68.76 ;
    END
  END dq[397]
  PIN dq[398]
    DIRECTION OUTPUT ;
    USE SIGNAL ;
    PORT
      LAYER M4 ;
        RECT  36.528 68.88 36.72 68.904 ;
    END
  END dq[398]
  PIN dq[399]
    DIRECTION OUTPUT ;
    USE SIGNAL ;
    PORT
      LAYER M4 ;
        RECT  36.528 69.072 36.72 69.096 ;
    END
  END dq[399]
  PIN dq[39]
    DIRECTION OUTPUT ;
    USE SIGNAL ;
    PORT
      LAYER M4 ;
        RECT  36.528 10.752 36.72 10.776 ;
    END
  END dq[39]
  PIN dq[3]
    DIRECTION OUTPUT ;
    USE SIGNAL ;
    PORT
      LAYER M4 ;
        RECT  36.528 4.896 36.72 4.92 ;
    END
  END dq[3]
  PIN dq[400]
    DIRECTION OUTPUT ;
    USE SIGNAL ;
    PORT
      LAYER M4 ;
        RECT  36.528 69.216 36.72 69.24 ;
    END
  END dq[400]
  PIN dq[401]
    DIRECTION OUTPUT ;
    USE SIGNAL ;
    PORT
      LAYER M4 ;
        RECT  36.528 69.36 36.72 69.384 ;
    END
  END dq[401]
  PIN dq[402]
    DIRECTION OUTPUT ;
    USE SIGNAL ;
    PORT
      LAYER M4 ;
        RECT  36.528 69.552 36.72 69.576 ;
    END
  END dq[402]
  PIN dq[403]
    DIRECTION OUTPUT ;
    USE SIGNAL ;
    PORT
      LAYER M4 ;
        RECT  36.528 69.696 36.72 69.72 ;
    END
  END dq[403]
  PIN dq[404]
    DIRECTION OUTPUT ;
    USE SIGNAL ;
    PORT
      LAYER M4 ;
        RECT  36.528 69.84 36.72 69.864 ;
    END
  END dq[404]
  PIN dq[405]
    DIRECTION OUTPUT ;
    USE SIGNAL ;
    PORT
      LAYER M4 ;
        RECT  36.528 70.032 36.72 70.056 ;
    END
  END dq[405]
  PIN dq[406]
    DIRECTION OUTPUT ;
    USE SIGNAL ;
    PORT
      LAYER M4 ;
        RECT  36.528 70.176 36.72 70.2 ;
    END
  END dq[406]
  PIN dq[407]
    DIRECTION OUTPUT ;
    USE SIGNAL ;
    PORT
      LAYER M4 ;
        RECT  36.528 70.368 36.72 70.392 ;
    END
  END dq[407]
  PIN dq[408]
    DIRECTION OUTPUT ;
    USE SIGNAL ;
    PORT
      LAYER M4 ;
        RECT  36.528 70.512 36.72 70.536 ;
    END
  END dq[408]
  PIN dq[409]
    DIRECTION OUTPUT ;
    USE SIGNAL ;
    PORT
      LAYER M4 ;
        RECT  36.528 70.656 36.72 70.68 ;
    END
  END dq[409]
  PIN dq[40]
    DIRECTION OUTPUT ;
    USE SIGNAL ;
    PORT
      LAYER M4 ;
        RECT  36.528 10.896 36.72 10.92 ;
    END
  END dq[40]
  PIN dq[410]
    DIRECTION OUTPUT ;
    USE SIGNAL ;
    PORT
      LAYER M4 ;
        RECT  36.528 70.848 36.72 70.872 ;
    END
  END dq[410]
  PIN dq[411]
    DIRECTION OUTPUT ;
    USE SIGNAL ;
    PORT
      LAYER M4 ;
        RECT  36.528 70.992 36.72 71.016 ;
    END
  END dq[411]
  PIN dq[412]
    DIRECTION OUTPUT ;
    USE SIGNAL ;
    PORT
      LAYER M4 ;
        RECT  36.528 71.136 36.72 71.16 ;
    END
  END dq[412]
  PIN dq[413]
    DIRECTION OUTPUT ;
    USE SIGNAL ;
    PORT
      LAYER M4 ;
        RECT  36.528 71.328 36.72 71.352 ;
    END
  END dq[413]
  PIN dq[414]
    DIRECTION OUTPUT ;
    USE SIGNAL ;
    PORT
      LAYER M4 ;
        RECT  36.528 71.472 36.72 71.496 ;
    END
  END dq[414]
  PIN dq[415]
    DIRECTION OUTPUT ;
    USE SIGNAL ;
    PORT
      LAYER M4 ;
        RECT  36.528 71.664 36.72 71.688 ;
    END
  END dq[415]
  PIN dq[416]
    DIRECTION OUTPUT ;
    USE SIGNAL ;
    PORT
      LAYER M4 ;
        RECT  36.528 71.808 36.72 71.832 ;
    END
  END dq[416]
  PIN dq[417]
    DIRECTION OUTPUT ;
    USE SIGNAL ;
    PORT
      LAYER M4 ;
        RECT  36.528 71.952 36.72 71.976 ;
    END
  END dq[417]
  PIN dq[418]
    DIRECTION OUTPUT ;
    USE SIGNAL ;
    PORT
      LAYER M4 ;
        RECT  36.528 72.144 36.72 72.168 ;
    END
  END dq[418]
  PIN dq[419]
    DIRECTION OUTPUT ;
    USE SIGNAL ;
    PORT
      LAYER M4 ;
        RECT  36.528 72.288 36.72 72.312 ;
    END
  END dq[419]
  PIN dq[41]
    DIRECTION OUTPUT ;
    USE SIGNAL ;
    PORT
      LAYER M4 ;
        RECT  36.528 11.04 36.72 11.064 ;
    END
  END dq[41]
  PIN dq[420]
    DIRECTION OUTPUT ;
    USE SIGNAL ;
    PORT
      LAYER M4 ;
        RECT  36.528 72.432 36.72 72.456 ;
    END
  END dq[420]
  PIN dq[421]
    DIRECTION OUTPUT ;
    USE SIGNAL ;
    PORT
      LAYER M4 ;
        RECT  36.528 72.624 36.72 72.648 ;
    END
  END dq[421]
  PIN dq[422]
    DIRECTION OUTPUT ;
    USE SIGNAL ;
    PORT
      LAYER M4 ;
        RECT  36.528 72.768 36.72 72.792 ;
    END
  END dq[422]
  PIN dq[423]
    DIRECTION OUTPUT ;
    USE SIGNAL ;
    PORT
      LAYER M4 ;
        RECT  36.528 72.96 36.72 72.984 ;
    END
  END dq[423]
  PIN dq[424]
    DIRECTION OUTPUT ;
    USE SIGNAL ;
    PORT
      LAYER M4 ;
        RECT  36.528 73.104 36.72 73.128 ;
    END
  END dq[424]
  PIN dq[425]
    DIRECTION OUTPUT ;
    USE SIGNAL ;
    PORT
      LAYER M4 ;
        RECT  36.528 73.248 36.72 73.272 ;
    END
  END dq[425]
  PIN dq[426]
    DIRECTION OUTPUT ;
    USE SIGNAL ;
    PORT
      LAYER M4 ;
        RECT  36.528 73.44 36.72 73.464 ;
    END
  END dq[426]
  PIN dq[427]
    DIRECTION OUTPUT ;
    USE SIGNAL ;
    PORT
      LAYER M4 ;
        RECT  36.528 73.584 36.72 73.608 ;
    END
  END dq[427]
  PIN dq[428]
    DIRECTION OUTPUT ;
    USE SIGNAL ;
    PORT
      LAYER M4 ;
        RECT  36.528 73.728 36.72 73.752 ;
    END
  END dq[428]
  PIN dq[429]
    DIRECTION OUTPUT ;
    USE SIGNAL ;
    PORT
      LAYER M4 ;
        RECT  36.528 73.92 36.72 73.944 ;
    END
  END dq[429]
  PIN dq[42]
    DIRECTION OUTPUT ;
    USE SIGNAL ;
    PORT
      LAYER M4 ;
        RECT  36.528 11.232 36.72 11.256 ;
    END
  END dq[42]
  PIN dq[430]
    DIRECTION OUTPUT ;
    USE SIGNAL ;
    PORT
      LAYER M4 ;
        RECT  36.528 74.064 36.72 74.088 ;
    END
  END dq[430]
  PIN dq[431]
    DIRECTION OUTPUT ;
    USE SIGNAL ;
    PORT
      LAYER M4 ;
        RECT  36.528 74.256 36.72 74.28 ;
    END
  END dq[431]
  PIN dq[432]
    DIRECTION OUTPUT ;
    USE SIGNAL ;
    PORT
      LAYER M4 ;
        RECT  36.528 74.4 36.72 74.424 ;
    END
  END dq[432]
  PIN dq[433]
    DIRECTION OUTPUT ;
    USE SIGNAL ;
    PORT
      LAYER M4 ;
        RECT  36.528 74.544 36.72 74.568 ;
    END
  END dq[433]
  PIN dq[434]
    DIRECTION OUTPUT ;
    USE SIGNAL ;
    PORT
      LAYER M4 ;
        RECT  36.528 74.736 36.72 74.76 ;
    END
  END dq[434]
  PIN dq[435]
    DIRECTION OUTPUT ;
    USE SIGNAL ;
    PORT
      LAYER M4 ;
        RECT  36.528 74.88 36.72 74.904 ;
    END
  END dq[435]
  PIN dq[436]
    DIRECTION OUTPUT ;
    USE SIGNAL ;
    PORT
      LAYER M4 ;
        RECT  36.528 75.024 36.72 75.048 ;
    END
  END dq[436]
  PIN dq[437]
    DIRECTION OUTPUT ;
    USE SIGNAL ;
    PORT
      LAYER M4 ;
        RECT  36.528 75.216 36.72 75.24 ;
    END
  END dq[437]
  PIN dq[438]
    DIRECTION OUTPUT ;
    USE SIGNAL ;
    PORT
      LAYER M4 ;
        RECT  36.528 75.36 36.72 75.384 ;
    END
  END dq[438]
  PIN dq[439]
    DIRECTION OUTPUT ;
    USE SIGNAL ;
    PORT
      LAYER M4 ;
        RECT  36.528 75.552 36.72 75.576 ;
    END
  END dq[439]
  PIN dq[43]
    DIRECTION OUTPUT ;
    USE SIGNAL ;
    PORT
      LAYER M4 ;
        RECT  36.528 11.376 36.72 11.4 ;
    END
  END dq[43]
  PIN dq[440]
    DIRECTION OUTPUT ;
    USE SIGNAL ;
    PORT
      LAYER M4 ;
        RECT  36.528 75.696 36.72 75.72 ;
    END
  END dq[440]
  PIN dq[441]
    DIRECTION OUTPUT ;
    USE SIGNAL ;
    PORT
      LAYER M4 ;
        RECT  36.528 75.84 36.72 75.864 ;
    END
  END dq[441]
  PIN dq[442]
    DIRECTION OUTPUT ;
    USE SIGNAL ;
    PORT
      LAYER M4 ;
        RECT  36.528 76.032 36.72 76.056 ;
    END
  END dq[442]
  PIN dq[443]
    DIRECTION OUTPUT ;
    USE SIGNAL ;
    PORT
      LAYER M4 ;
        RECT  36.528 76.176 36.72 76.2 ;
    END
  END dq[443]
  PIN dq[444]
    DIRECTION OUTPUT ;
    USE SIGNAL ;
    PORT
      LAYER M4 ;
        RECT  36.528 76.32 36.72 76.344 ;
    END
  END dq[444]
  PIN dq[445]
    DIRECTION OUTPUT ;
    USE SIGNAL ;
    PORT
      LAYER M4 ;
        RECT  36.528 76.512 36.72 76.536 ;
    END
  END dq[445]
  PIN dq[446]
    DIRECTION OUTPUT ;
    USE SIGNAL ;
    PORT
      LAYER M4 ;
        RECT  36.528 76.656 36.72 76.68 ;
    END
  END dq[446]
  PIN dq[447]
    DIRECTION OUTPUT ;
    USE SIGNAL ;
    PORT
      LAYER M4 ;
        RECT  36.528 76.848 36.72 76.872 ;
    END
  END dq[447]
  PIN dq[448]
    DIRECTION OUTPUT ;
    USE SIGNAL ;
    PORT
      LAYER M4 ;
        RECT  36.528 76.992 36.72 77.016 ;
    END
  END dq[448]
  PIN dq[449]
    DIRECTION OUTPUT ;
    USE SIGNAL ;
    PORT
      LAYER M4 ;
        RECT  36.528 77.136 36.72 77.16 ;
    END
  END dq[449]
  PIN dq[44]
    DIRECTION OUTPUT ;
    USE SIGNAL ;
    PORT
      LAYER M4 ;
        RECT  36.528 11.52 36.72 11.544 ;
    END
  END dq[44]
  PIN dq[450]
    DIRECTION OUTPUT ;
    USE SIGNAL ;
    PORT
      LAYER M4 ;
        RECT  36.528 77.328 36.72 77.352 ;
    END
  END dq[450]
  PIN dq[451]
    DIRECTION OUTPUT ;
    USE SIGNAL ;
    PORT
      LAYER M4 ;
        RECT  36.528 77.472 36.72 77.496 ;
    END
  END dq[451]
  PIN dq[452]
    DIRECTION OUTPUT ;
    USE SIGNAL ;
    PORT
      LAYER M4 ;
        RECT  36.528 77.616 36.72 77.64 ;
    END
  END dq[452]
  PIN dq[453]
    DIRECTION OUTPUT ;
    USE SIGNAL ;
    PORT
      LAYER M4 ;
        RECT  36.528 77.808 36.72 77.832 ;
    END
  END dq[453]
  PIN dq[454]
    DIRECTION OUTPUT ;
    USE SIGNAL ;
    PORT
      LAYER M4 ;
        RECT  36.528 77.952 36.72 77.976 ;
    END
  END dq[454]
  PIN dq[455]
    DIRECTION OUTPUT ;
    USE SIGNAL ;
    PORT
      LAYER M4 ;
        RECT  36.528 78.144 36.72 78.168 ;
    END
  END dq[455]
  PIN dq[456]
    DIRECTION OUTPUT ;
    USE SIGNAL ;
    PORT
      LAYER M4 ;
        RECT  36.528 78.288 36.72 78.312 ;
    END
  END dq[456]
  PIN dq[457]
    DIRECTION OUTPUT ;
    USE SIGNAL ;
    PORT
      LAYER M4 ;
        RECT  36.528 78.432 36.72 78.456 ;
    END
  END dq[457]
  PIN dq[458]
    DIRECTION OUTPUT ;
    USE SIGNAL ;
    PORT
      LAYER M4 ;
        RECT  36.528 78.624 36.72 78.648 ;
    END
  END dq[458]
  PIN dq[459]
    DIRECTION OUTPUT ;
    USE SIGNAL ;
    PORT
      LAYER M4 ;
        RECT  36.528 78.768 36.72 78.792 ;
    END
  END dq[459]
  PIN dq[45]
    DIRECTION OUTPUT ;
    USE SIGNAL ;
    PORT
      LAYER M4 ;
        RECT  36.528 11.712 36.72 11.736 ;
    END
  END dq[45]
  PIN dq[460]
    DIRECTION OUTPUT ;
    USE SIGNAL ;
    PORT
      LAYER M4 ;
        RECT  36.528 78.912 36.72 78.936 ;
    END
  END dq[460]
  PIN dq[461]
    DIRECTION OUTPUT ;
    USE SIGNAL ;
    PORT
      LAYER M4 ;
        RECT  36.528 79.104 36.72 79.128 ;
    END
  END dq[461]
  PIN dq[462]
    DIRECTION OUTPUT ;
    USE SIGNAL ;
    PORT
      LAYER M4 ;
        RECT  36.528 79.248 36.72 79.272 ;
    END
  END dq[462]
  PIN dq[463]
    DIRECTION OUTPUT ;
    USE SIGNAL ;
    PORT
      LAYER M4 ;
        RECT  36.528 79.44 36.72 79.464 ;
    END
  END dq[463]
  PIN dq[464]
    DIRECTION OUTPUT ;
    USE SIGNAL ;
    PORT
      LAYER M4 ;
        RECT  36.528 79.584 36.72 79.608 ;
    END
  END dq[464]
  PIN dq[465]
    DIRECTION OUTPUT ;
    USE SIGNAL ;
    PORT
      LAYER M4 ;
        RECT  36.528 79.728 36.72 79.752 ;
    END
  END dq[465]
  PIN dq[466]
    DIRECTION OUTPUT ;
    USE SIGNAL ;
    PORT
      LAYER M4 ;
        RECT  36.528 79.92 36.72 79.944 ;
    END
  END dq[466]
  PIN dq[467]
    DIRECTION OUTPUT ;
    USE SIGNAL ;
    PORT
      LAYER M4 ;
        RECT  36.528 80.064 36.72 80.088 ;
    END
  END dq[467]
  PIN dq[468]
    DIRECTION OUTPUT ;
    USE SIGNAL ;
    PORT
      LAYER M4 ;
        RECT  36.528 80.208 36.72 80.232 ;
    END
  END dq[468]
  PIN dq[469]
    DIRECTION OUTPUT ;
    USE SIGNAL ;
    PORT
      LAYER M4 ;
        RECT  36.528 80.4 36.72 80.424 ;
    END
  END dq[469]
  PIN dq[46]
    DIRECTION OUTPUT ;
    USE SIGNAL ;
    PORT
      LAYER M4 ;
        RECT  36.528 11.856 36.72 11.88 ;
    END
  END dq[46]
  PIN dq[470]
    DIRECTION OUTPUT ;
    USE SIGNAL ;
    PORT
      LAYER M4 ;
        RECT  36.528 80.544 36.72 80.568 ;
    END
  END dq[470]
  PIN dq[471]
    DIRECTION OUTPUT ;
    USE SIGNAL ;
    PORT
      LAYER M4 ;
        RECT  36.528 80.736 36.72 80.76 ;
    END
  END dq[471]
  PIN dq[472]
    DIRECTION OUTPUT ;
    USE SIGNAL ;
    PORT
      LAYER M4 ;
        RECT  36.528 80.88 36.72 80.904 ;
    END
  END dq[472]
  PIN dq[473]
    DIRECTION OUTPUT ;
    USE SIGNAL ;
    PORT
      LAYER M4 ;
        RECT  36.528 81.024 36.72 81.048 ;
    END
  END dq[473]
  PIN dq[474]
    DIRECTION OUTPUT ;
    USE SIGNAL ;
    PORT
      LAYER M4 ;
        RECT  36.528 81.216 36.72 81.24 ;
    END
  END dq[474]
  PIN dq[475]
    DIRECTION OUTPUT ;
    USE SIGNAL ;
    PORT
      LAYER M4 ;
        RECT  36.528 81.36 36.72 81.384 ;
    END
  END dq[475]
  PIN dq[476]
    DIRECTION OUTPUT ;
    USE SIGNAL ;
    PORT
      LAYER M4 ;
        RECT  36.528 81.504 36.72 81.528 ;
    END
  END dq[476]
  PIN dq[477]
    DIRECTION OUTPUT ;
    USE SIGNAL ;
    PORT
      LAYER M4 ;
        RECT  36.528 81.696 36.72 81.72 ;
    END
  END dq[477]
  PIN dq[478]
    DIRECTION OUTPUT ;
    USE SIGNAL ;
    PORT
      LAYER M4 ;
        RECT  36.528 81.84 36.72 81.864 ;
    END
  END dq[478]
  PIN dq[479]
    DIRECTION OUTPUT ;
    USE SIGNAL ;
    PORT
      LAYER M4 ;
        RECT  36.528 82.032 36.72 82.056 ;
    END
  END dq[479]
  PIN dq[47]
    DIRECTION OUTPUT ;
    USE SIGNAL ;
    PORT
      LAYER M4 ;
        RECT  36.528 12.048 36.72 12.072 ;
    END
  END dq[47]
  PIN dq[480]
    DIRECTION OUTPUT ;
    USE SIGNAL ;
    PORT
      LAYER M4 ;
        RECT  36.528 82.176 36.72 82.2 ;
    END
  END dq[480]
  PIN dq[481]
    DIRECTION OUTPUT ;
    USE SIGNAL ;
    PORT
      LAYER M4 ;
        RECT  36.528 82.32 36.72 82.344 ;
    END
  END dq[481]
  PIN dq[482]
    DIRECTION OUTPUT ;
    USE SIGNAL ;
    PORT
      LAYER M4 ;
        RECT  36.528 82.512 36.72 82.536 ;
    END
  END dq[482]
  PIN dq[483]
    DIRECTION OUTPUT ;
    USE SIGNAL ;
    PORT
      LAYER M4 ;
        RECT  36.528 82.656 36.72 82.68 ;
    END
  END dq[483]
  PIN dq[484]
    DIRECTION OUTPUT ;
    USE SIGNAL ;
    PORT
      LAYER M4 ;
        RECT  36.528 82.8 36.72 82.824 ;
    END
  END dq[484]
  PIN dq[485]
    DIRECTION OUTPUT ;
    USE SIGNAL ;
    PORT
      LAYER M4 ;
        RECT  36.528 82.992 36.72 83.016 ;
    END
  END dq[485]
  PIN dq[486]
    DIRECTION OUTPUT ;
    USE SIGNAL ;
    PORT
      LAYER M4 ;
        RECT  36.528 83.136 36.72 83.16 ;
    END
  END dq[486]
  PIN dq[487]
    DIRECTION OUTPUT ;
    USE SIGNAL ;
    PORT
      LAYER M4 ;
        RECT  36.528 83.328 36.72 83.352 ;
    END
  END dq[487]
  PIN dq[488]
    DIRECTION OUTPUT ;
    USE SIGNAL ;
    PORT
      LAYER M4 ;
        RECT  36.528 83.472 36.72 83.496 ;
    END
  END dq[488]
  PIN dq[489]
    DIRECTION OUTPUT ;
    USE SIGNAL ;
    PORT
      LAYER M4 ;
        RECT  36.528 83.616 36.72 83.64 ;
    END
  END dq[489]
  PIN dq[48]
    DIRECTION OUTPUT ;
    USE SIGNAL ;
    PORT
      LAYER M4 ;
        RECT  36.528 12.192 36.72 12.216 ;
    END
  END dq[48]
  PIN dq[490]
    DIRECTION OUTPUT ;
    USE SIGNAL ;
    PORT
      LAYER M4 ;
        RECT  36.528 83.808 36.72 83.832 ;
    END
  END dq[490]
  PIN dq[491]
    DIRECTION OUTPUT ;
    USE SIGNAL ;
    PORT
      LAYER M4 ;
        RECT  36.528 83.952 36.72 83.976 ;
    END
  END dq[491]
  PIN dq[492]
    DIRECTION OUTPUT ;
    USE SIGNAL ;
    PORT
      LAYER M4 ;
        RECT  36.528 84.096 36.72 84.12 ;
    END
  END dq[492]
  PIN dq[493]
    DIRECTION OUTPUT ;
    USE SIGNAL ;
    PORT
      LAYER M4 ;
        RECT  36.528 84.288 36.72 84.312 ;
    END
  END dq[493]
  PIN dq[494]
    DIRECTION OUTPUT ;
    USE SIGNAL ;
    PORT
      LAYER M4 ;
        RECT  36.528 84.432 36.72 84.456 ;
    END
  END dq[494]
  PIN dq[495]
    DIRECTION OUTPUT ;
    USE SIGNAL ;
    PORT
      LAYER M4 ;
        RECT  36.528 84.624 36.72 84.648 ;
    END
  END dq[495]
  PIN dq[496]
    DIRECTION OUTPUT ;
    USE SIGNAL ;
    PORT
      LAYER M4 ;
        RECT  36.528 84.768 36.72 84.792 ;
    END
  END dq[496]
  PIN dq[497]
    DIRECTION OUTPUT ;
    USE SIGNAL ;
    PORT
      LAYER M4 ;
        RECT  36.528 84.912 36.72 84.936 ;
    END
  END dq[497]
  PIN dq[498]
    DIRECTION OUTPUT ;
    USE SIGNAL ;
    PORT
      LAYER M4 ;
        RECT  36.528 85.104 36.72 85.128 ;
    END
  END dq[498]
  PIN dq[499]
    DIRECTION OUTPUT ;
    USE SIGNAL ;
    PORT
      LAYER M4 ;
        RECT  36.528 85.248 36.72 85.272 ;
    END
  END dq[499]
  PIN dq[49]
    DIRECTION OUTPUT ;
    USE SIGNAL ;
    PORT
      LAYER M4 ;
        RECT  36.528 12.336 36.72 12.36 ;
    END
  END dq[49]
  PIN dq[4]
    DIRECTION OUTPUT ;
    USE SIGNAL ;
    PORT
      LAYER M4 ;
        RECT  36.528 5.04 36.72 5.064 ;
    END
  END dq[4]
  PIN dq[500]
    DIRECTION OUTPUT ;
    USE SIGNAL ;
    PORT
      LAYER M4 ;
        RECT  36.528 85.392 36.72 85.416 ;
    END
  END dq[500]
  PIN dq[501]
    DIRECTION OUTPUT ;
    USE SIGNAL ;
    PORT
      LAYER M4 ;
        RECT  36.528 85.584 36.72 85.608 ;
    END
  END dq[501]
  PIN dq[502]
    DIRECTION OUTPUT ;
    USE SIGNAL ;
    PORT
      LAYER M4 ;
        RECT  36.528 85.728 36.72 85.752 ;
    END
  END dq[502]
  PIN dq[503]
    DIRECTION OUTPUT ;
    USE SIGNAL ;
    PORT
      LAYER M4 ;
        RECT  36.528 85.92 36.72 85.944 ;
    END
  END dq[503]
  PIN dq[504]
    DIRECTION OUTPUT ;
    USE SIGNAL ;
    PORT
      LAYER M4 ;
        RECT  36.528 86.064 36.72 86.088 ;
    END
  END dq[504]
  PIN dq[505]
    DIRECTION OUTPUT ;
    USE SIGNAL ;
    PORT
      LAYER M4 ;
        RECT  36.528 86.208 36.72 86.232 ;
    END
  END dq[505]
  PIN dq[506]
    DIRECTION OUTPUT ;
    USE SIGNAL ;
    PORT
      LAYER M4 ;
        RECT  36.528 86.4 36.72 86.424 ;
    END
  END dq[506]
  PIN dq[507]
    DIRECTION OUTPUT ;
    USE SIGNAL ;
    PORT
      LAYER M4 ;
        RECT  36.528 86.544 36.72 86.568 ;
    END
  END dq[507]
  PIN dq[508]
    DIRECTION OUTPUT ;
    USE SIGNAL ;
    PORT
      LAYER M4 ;
        RECT  36.528 86.688 36.72 86.712 ;
    END
  END dq[508]
  PIN dq[509]
    DIRECTION OUTPUT ;
    USE SIGNAL ;
    PORT
      LAYER M4 ;
        RECT  36.528 86.88 36.72 86.904 ;
    END
  END dq[509]
  PIN dq[50]
    DIRECTION OUTPUT ;
    USE SIGNAL ;
    PORT
      LAYER M4 ;
        RECT  36.528 12.528 36.72 12.552 ;
    END
  END dq[50]
  PIN dq[510]
    DIRECTION OUTPUT ;
    USE SIGNAL ;
    PORT
      LAYER M4 ;
        RECT  36.528 87.024 36.72 87.048 ;
    END
  END dq[510]
  PIN dq[511]
    DIRECTION OUTPUT ;
    USE SIGNAL ;
    PORT
      LAYER M4 ;
        RECT  36.528 87.216 36.72 87.24 ;
    END
  END dq[511]
  PIN dq[512]
    DIRECTION OUTPUT ;
    USE SIGNAL ;
    PORT
      LAYER M4 ;
        RECT  36.528 87.36 36.72 87.384 ;
    END
  END dq[512]
  PIN dq[513]
    DIRECTION OUTPUT ;
    USE SIGNAL ;
    PORT
      LAYER M4 ;
        RECT  36.528 87.504 36.72 87.528 ;
    END
  END dq[513]
  PIN dq[514]
    DIRECTION OUTPUT ;
    USE SIGNAL ;
    PORT
      LAYER M4 ;
        RECT  36.528 87.696 36.72 87.72 ;
    END
  END dq[514]
  PIN dq[515]
    DIRECTION OUTPUT ;
    USE SIGNAL ;
    PORT
      LAYER M4 ;
        RECT  36.528 87.84 36.72 87.864 ;
    END
  END dq[515]
  PIN dq[516]
    DIRECTION OUTPUT ;
    USE SIGNAL ;
    PORT
      LAYER M4 ;
        RECT  36.528 87.984 36.72 88.008 ;
    END
  END dq[516]
  PIN dq[517]
    DIRECTION OUTPUT ;
    USE SIGNAL ;
    PORT
      LAYER M4 ;
        RECT  36.528 88.176 36.72 88.2 ;
    END
  END dq[517]
  PIN dq[518]
    DIRECTION OUTPUT ;
    USE SIGNAL ;
    PORT
      LAYER M4 ;
        RECT  36.528 88.32 36.72 88.344 ;
    END
  END dq[518]
  PIN dq[519]
    DIRECTION OUTPUT ;
    USE SIGNAL ;
    PORT
      LAYER M4 ;
        RECT  36.528 88.512 36.72 88.536 ;
    END
  END dq[519]
  PIN dq[51]
    DIRECTION OUTPUT ;
    USE SIGNAL ;
    PORT
      LAYER M4 ;
        RECT  36.528 12.672 36.72 12.696 ;
    END
  END dq[51]
  PIN dq[520]
    DIRECTION OUTPUT ;
    USE SIGNAL ;
    PORT
      LAYER M4 ;
        RECT  36.528 88.656 36.72 88.68 ;
    END
  END dq[520]
  PIN dq[521]
    DIRECTION OUTPUT ;
    USE SIGNAL ;
    PORT
      LAYER M4 ;
        RECT  36.528 88.8 36.72 88.824 ;
    END
  END dq[521]
  PIN dq[522]
    DIRECTION OUTPUT ;
    USE SIGNAL ;
    PORT
      LAYER M4 ;
        RECT  36.528 88.992 36.72 89.016 ;
    END
  END dq[522]
  PIN dq[523]
    DIRECTION OUTPUT ;
    USE SIGNAL ;
    PORT
      LAYER M4 ;
        RECT  36.528 89.136 36.72 89.16 ;
    END
  END dq[523]
  PIN dq[524]
    DIRECTION OUTPUT ;
    USE SIGNAL ;
    PORT
      LAYER M4 ;
        RECT  36.528 89.28 36.72 89.304 ;
    END
  END dq[524]
  PIN dq[525]
    DIRECTION OUTPUT ;
    USE SIGNAL ;
    PORT
      LAYER M4 ;
        RECT  36.528 89.472 36.72 89.496 ;
    END
  END dq[525]
  PIN dq[526]
    DIRECTION OUTPUT ;
    USE SIGNAL ;
    PORT
      LAYER M4 ;
        RECT  36.528 89.616 36.72 89.64 ;
    END
  END dq[526]
  PIN dq[527]
    DIRECTION OUTPUT ;
    USE SIGNAL ;
    PORT
      LAYER M4 ;
        RECT  36.528 89.808 36.72 89.832 ;
    END
  END dq[527]
  PIN dq[528]
    DIRECTION OUTPUT ;
    USE SIGNAL ;
    PORT
      LAYER M4 ;
        RECT  36.528 89.952 36.72 89.976 ;
    END
  END dq[528]
  PIN dq[529]
    DIRECTION OUTPUT ;
    USE SIGNAL ;
    PORT
      LAYER M4 ;
        RECT  36.528 90.096 36.72 90.12 ;
    END
  END dq[529]
  PIN dq[52]
    DIRECTION OUTPUT ;
    USE SIGNAL ;
    PORT
      LAYER M4 ;
        RECT  36.528 12.816 36.72 12.84 ;
    END
  END dq[52]
  PIN dq[530]
    DIRECTION OUTPUT ;
    USE SIGNAL ;
    PORT
      LAYER M4 ;
        RECT  36.528 90.288 36.72 90.312 ;
    END
  END dq[530]
  PIN dq[531]
    DIRECTION OUTPUT ;
    USE SIGNAL ;
    PORT
      LAYER M4 ;
        RECT  36.528 90.432 36.72 90.456 ;
    END
  END dq[531]
  PIN dq[532]
    DIRECTION OUTPUT ;
    USE SIGNAL ;
    PORT
      LAYER M4 ;
        RECT  36.528 90.576 36.72 90.6 ;
    END
  END dq[532]
  PIN dq[533]
    DIRECTION OUTPUT ;
    USE SIGNAL ;
    PORT
      LAYER M4 ;
        RECT  36.528 90.768 36.72 90.792 ;
    END
  END dq[533]
  PIN dq[534]
    DIRECTION OUTPUT ;
    USE SIGNAL ;
    PORT
      LAYER M4 ;
        RECT  36.528 90.912 36.72 90.936 ;
    END
  END dq[534]
  PIN dq[535]
    DIRECTION OUTPUT ;
    USE SIGNAL ;
    PORT
      LAYER M4 ;
        RECT  36.528 91.104 36.72 91.128 ;
    END
  END dq[535]
  PIN dq[536]
    DIRECTION OUTPUT ;
    USE SIGNAL ;
    PORT
      LAYER M4 ;
        RECT  36.528 91.248 36.72 91.272 ;
    END
  END dq[536]
  PIN dq[537]
    DIRECTION OUTPUT ;
    USE SIGNAL ;
    PORT
      LAYER M4 ;
        RECT  36.528 91.392 36.72 91.416 ;
    END
  END dq[537]
  PIN dq[538]
    DIRECTION OUTPUT ;
    USE SIGNAL ;
    PORT
      LAYER M4 ;
        RECT  36.528 91.584 36.72 91.608 ;
    END
  END dq[538]
  PIN dq[539]
    DIRECTION OUTPUT ;
    USE SIGNAL ;
    PORT
      LAYER M4 ;
        RECT  36.528 91.728 36.72 91.752 ;
    END
  END dq[539]
  PIN dq[53]
    DIRECTION OUTPUT ;
    USE SIGNAL ;
    PORT
      LAYER M4 ;
        RECT  36.528 13.008 36.72 13.032 ;
    END
  END dq[53]
  PIN dq[540]
    DIRECTION OUTPUT ;
    USE SIGNAL ;
    PORT
      LAYER M4 ;
        RECT  36.528 91.872 36.72 91.896 ;
    END
  END dq[540]
  PIN dq[541]
    DIRECTION OUTPUT ;
    USE SIGNAL ;
    PORT
      LAYER M4 ;
        RECT  36.528 92.064 36.72 92.088 ;
    END
  END dq[541]
  PIN dq[542]
    DIRECTION OUTPUT ;
    USE SIGNAL ;
    PORT
      LAYER M4 ;
        RECT  36.528 92.208 36.72 92.232 ;
    END
  END dq[542]
  PIN dq[543]
    DIRECTION OUTPUT ;
    USE SIGNAL ;
    PORT
      LAYER M4 ;
        RECT  36.528 92.4 36.72 92.424 ;
    END
  END dq[543]
  PIN dq[544]
    DIRECTION OUTPUT ;
    USE SIGNAL ;
    PORT
      LAYER M4 ;
        RECT  36.528 92.544 36.72 92.568 ;
    END
  END dq[544]
  PIN dq[545]
    DIRECTION OUTPUT ;
    USE SIGNAL ;
    PORT
      LAYER M4 ;
        RECT  36.528 92.688 36.72 92.712 ;
    END
  END dq[545]
  PIN dq[546]
    DIRECTION OUTPUT ;
    USE SIGNAL ;
    PORT
      LAYER M4 ;
        RECT  36.528 92.88 36.72 92.904 ;
    END
  END dq[546]
  PIN dq[547]
    DIRECTION OUTPUT ;
    USE SIGNAL ;
    PORT
      LAYER M4 ;
        RECT  36.528 93.024 36.72 93.048 ;
    END
  END dq[547]
  PIN dq[548]
    DIRECTION OUTPUT ;
    USE SIGNAL ;
    PORT
      LAYER M4 ;
        RECT  36.528 93.168 36.72 93.192 ;
    END
  END dq[548]
  PIN dq[549]
    DIRECTION OUTPUT ;
    USE SIGNAL ;
    PORT
      LAYER M4 ;
        RECT  36.528 93.36 36.72 93.384 ;
    END
  END dq[549]
  PIN dq[54]
    DIRECTION OUTPUT ;
    USE SIGNAL ;
    PORT
      LAYER M4 ;
        RECT  36.528 13.152 36.72 13.176 ;
    END
  END dq[54]
  PIN dq[550]
    DIRECTION OUTPUT ;
    USE SIGNAL ;
    PORT
      LAYER M4 ;
        RECT  36.528 93.504 36.72 93.528 ;
    END
  END dq[550]
  PIN dq[551]
    DIRECTION OUTPUT ;
    USE SIGNAL ;
    PORT
      LAYER M4 ;
        RECT  36.528 93.696 36.72 93.72 ;
    END
  END dq[551]
  PIN dq[552]
    DIRECTION OUTPUT ;
    USE SIGNAL ;
    PORT
      LAYER M4 ;
        RECT  36.528 93.84 36.72 93.864 ;
    END
  END dq[552]
  PIN dq[553]
    DIRECTION OUTPUT ;
    USE SIGNAL ;
    PORT
      LAYER M4 ;
        RECT  36.528 93.984 36.72 94.008 ;
    END
  END dq[553]
  PIN dq[554]
    DIRECTION OUTPUT ;
    USE SIGNAL ;
    PORT
      LAYER M4 ;
        RECT  36.528 94.176 36.72 94.2 ;
    END
  END dq[554]
  PIN dq[555]
    DIRECTION OUTPUT ;
    USE SIGNAL ;
    PORT
      LAYER M4 ;
        RECT  36.528 94.32 36.72 94.344 ;
    END
  END dq[555]
  PIN dq[556]
    DIRECTION OUTPUT ;
    USE SIGNAL ;
    PORT
      LAYER M4 ;
        RECT  36.528 94.464 36.72 94.488 ;
    END
  END dq[556]
  PIN dq[557]
    DIRECTION OUTPUT ;
    USE SIGNAL ;
    PORT
      LAYER M4 ;
        RECT  36.528 94.656 36.72 94.68 ;
    END
  END dq[557]
  PIN dq[558]
    DIRECTION OUTPUT ;
    USE SIGNAL ;
    PORT
      LAYER M4 ;
        RECT  36.528 94.8 36.72 94.824 ;
    END
  END dq[558]
  PIN dq[559]
    DIRECTION OUTPUT ;
    USE SIGNAL ;
    PORT
      LAYER M4 ;
        RECT  36.528 94.992 36.72 95.016 ;
    END
  END dq[559]
  PIN dq[55]
    DIRECTION OUTPUT ;
    USE SIGNAL ;
    PORT
      LAYER M4 ;
        RECT  36.528 13.344 36.72 13.368 ;
    END
  END dq[55]
  PIN dq[56]
    DIRECTION OUTPUT ;
    USE SIGNAL ;
    PORT
      LAYER M4 ;
        RECT  36.528 13.488 36.72 13.512 ;
    END
  END dq[56]
  PIN dq[57]
    DIRECTION OUTPUT ;
    USE SIGNAL ;
    PORT
      LAYER M4 ;
        RECT  36.528 13.632 36.72 13.656 ;
    END
  END dq[57]
  PIN dq[58]
    DIRECTION OUTPUT ;
    USE SIGNAL ;
    PORT
      LAYER M4 ;
        RECT  36.528 13.824 36.72 13.848 ;
    END
  END dq[58]
  PIN dq[59]
    DIRECTION OUTPUT ;
    USE SIGNAL ;
    PORT
      LAYER M4 ;
        RECT  36.528 13.968 36.72 13.992 ;
    END
  END dq[59]
  PIN dq[5]
    DIRECTION OUTPUT ;
    USE SIGNAL ;
    PORT
      LAYER M4 ;
        RECT  36.528 5.232 36.72 5.256 ;
    END
  END dq[5]
  PIN dq[60]
    DIRECTION OUTPUT ;
    USE SIGNAL ;
    PORT
      LAYER M4 ;
        RECT  36.528 14.112 36.72 14.136 ;
    END
  END dq[60]
  PIN dq[61]
    DIRECTION OUTPUT ;
    USE SIGNAL ;
    PORT
      LAYER M4 ;
        RECT  36.528 14.304 36.72 14.328 ;
    END
  END dq[61]
  PIN dq[62]
    DIRECTION OUTPUT ;
    USE SIGNAL ;
    PORT
      LAYER M4 ;
        RECT  36.528 14.448 36.72 14.472 ;
    END
  END dq[62]
  PIN dq[63]
    DIRECTION OUTPUT ;
    USE SIGNAL ;
    PORT
      LAYER M4 ;
        RECT  36.528 14.64 36.72 14.664 ;
    END
  END dq[63]
  PIN dq[64]
    DIRECTION OUTPUT ;
    USE SIGNAL ;
    PORT
      LAYER M4 ;
        RECT  36.528 14.784 36.72 14.808 ;
    END
  END dq[64]
  PIN dq[65]
    DIRECTION OUTPUT ;
    USE SIGNAL ;
    PORT
      LAYER M4 ;
        RECT  36.528 14.928 36.72 14.952 ;
    END
  END dq[65]
  PIN dq[66]
    DIRECTION OUTPUT ;
    USE SIGNAL ;
    PORT
      LAYER M4 ;
        RECT  36.528 15.12 36.72 15.144 ;
    END
  END dq[66]
  PIN dq[67]
    DIRECTION OUTPUT ;
    USE SIGNAL ;
    PORT
      LAYER M4 ;
        RECT  36.528 15.264 36.72 15.288 ;
    END
  END dq[67]
  PIN dq[68]
    DIRECTION OUTPUT ;
    USE SIGNAL ;
    PORT
      LAYER M4 ;
        RECT  36.528 15.408 36.72 15.432 ;
    END
  END dq[68]
  PIN dq[69]
    DIRECTION OUTPUT ;
    USE SIGNAL ;
    PORT
      LAYER M4 ;
        RECT  36.528 15.6 36.72 15.624 ;
    END
  END dq[69]
  PIN dq[6]
    DIRECTION OUTPUT ;
    USE SIGNAL ;
    PORT
      LAYER M4 ;
        RECT  36.528 5.376 36.72 5.4 ;
    END
  END dq[6]
  PIN dq[70]
    DIRECTION OUTPUT ;
    USE SIGNAL ;
    PORT
      LAYER M4 ;
        RECT  36.528 15.744 36.72 15.768 ;
    END
  END dq[70]
  PIN dq[71]
    DIRECTION OUTPUT ;
    USE SIGNAL ;
    PORT
      LAYER M4 ;
        RECT  36.528 15.936 36.72 15.96 ;
    END
  END dq[71]
  PIN dq[72]
    DIRECTION OUTPUT ;
    USE SIGNAL ;
    PORT
      LAYER M4 ;
        RECT  36.528 16.08 36.72 16.104 ;
    END
  END dq[72]
  PIN dq[73]
    DIRECTION OUTPUT ;
    USE SIGNAL ;
    PORT
      LAYER M4 ;
        RECT  36.528 16.224 36.72 16.248 ;
    END
  END dq[73]
  PIN dq[74]
    DIRECTION OUTPUT ;
    USE SIGNAL ;
    PORT
      LAYER M4 ;
        RECT  36.528 16.416 36.72 16.44 ;
    END
  END dq[74]
  PIN dq[75]
    DIRECTION OUTPUT ;
    USE SIGNAL ;
    PORT
      LAYER M4 ;
        RECT  36.528 16.56 36.72 16.584 ;
    END
  END dq[75]
  PIN dq[76]
    DIRECTION OUTPUT ;
    USE SIGNAL ;
    PORT
      LAYER M4 ;
        RECT  36.528 16.704 36.72 16.728 ;
    END
  END dq[76]
  PIN dq[77]
    DIRECTION OUTPUT ;
    USE SIGNAL ;
    PORT
      LAYER M4 ;
        RECT  36.528 16.896 36.72 16.92 ;
    END
  END dq[77]
  PIN dq[78]
    DIRECTION OUTPUT ;
    USE SIGNAL ;
    PORT
      LAYER M4 ;
        RECT  36.528 17.04 36.72 17.064 ;
    END
  END dq[78]
  PIN dq[79]
    DIRECTION OUTPUT ;
    USE SIGNAL ;
    PORT
      LAYER M4 ;
        RECT  36.528 17.232 36.72 17.256 ;
    END
  END dq[79]
  PIN dq[7]
    DIRECTION OUTPUT ;
    USE SIGNAL ;
    PORT
      LAYER M4 ;
        RECT  36.528 5.568 36.72 5.592 ;
    END
  END dq[7]
  PIN dq[80]
    DIRECTION OUTPUT ;
    USE SIGNAL ;
    PORT
      LAYER M4 ;
        RECT  36.528 17.376 36.72 17.4 ;
    END
  END dq[80]
  PIN dq[81]
    DIRECTION OUTPUT ;
    USE SIGNAL ;
    PORT
      LAYER M4 ;
        RECT  36.528 17.52 36.72 17.544 ;
    END
  END dq[81]
  PIN dq[82]
    DIRECTION OUTPUT ;
    USE SIGNAL ;
    PORT
      LAYER M4 ;
        RECT  36.528 17.712 36.72 17.736 ;
    END
  END dq[82]
  PIN dq[83]
    DIRECTION OUTPUT ;
    USE SIGNAL ;
    PORT
      LAYER M4 ;
        RECT  36.528 17.856 36.72 17.88 ;
    END
  END dq[83]
  PIN dq[84]
    DIRECTION OUTPUT ;
    USE SIGNAL ;
    PORT
      LAYER M4 ;
        RECT  36.528 18 36.72 18.024 ;
    END
  END dq[84]
  PIN dq[85]
    DIRECTION OUTPUT ;
    USE SIGNAL ;
    PORT
      LAYER M4 ;
        RECT  36.528 18.192 36.72 18.216 ;
    END
  END dq[85]
  PIN dq[86]
    DIRECTION OUTPUT ;
    USE SIGNAL ;
    PORT
      LAYER M4 ;
        RECT  36.528 18.336 36.72 18.36 ;
    END
  END dq[86]
  PIN dq[87]
    DIRECTION OUTPUT ;
    USE SIGNAL ;
    PORT
      LAYER M4 ;
        RECT  36.528 18.528 36.72 18.552 ;
    END
  END dq[87]
  PIN dq[88]
    DIRECTION OUTPUT ;
    USE SIGNAL ;
    PORT
      LAYER M4 ;
        RECT  36.528 18.672 36.72 18.696 ;
    END
  END dq[88]
  PIN dq[89]
    DIRECTION OUTPUT ;
    USE SIGNAL ;
    PORT
      LAYER M4 ;
        RECT  36.528 18.816 36.72 18.84 ;
    END
  END dq[89]
  PIN dq[8]
    DIRECTION OUTPUT ;
    USE SIGNAL ;
    PORT
      LAYER M4 ;
        RECT  36.528 5.712 36.72 5.736 ;
    END
  END dq[8]
  PIN dq[90]
    DIRECTION OUTPUT ;
    USE SIGNAL ;
    PORT
      LAYER M4 ;
        RECT  36.528 19.008 36.72 19.032 ;
    END
  END dq[90]
  PIN dq[91]
    DIRECTION OUTPUT ;
    USE SIGNAL ;
    PORT
      LAYER M4 ;
        RECT  36.528 19.152 36.72 19.176 ;
    END
  END dq[91]
  PIN dq[92]
    DIRECTION OUTPUT ;
    USE SIGNAL ;
    PORT
      LAYER M4 ;
        RECT  36.528 19.296 36.72 19.32 ;
    END
  END dq[92]
  PIN dq[93]
    DIRECTION OUTPUT ;
    USE SIGNAL ;
    PORT
      LAYER M4 ;
        RECT  36.528 19.488 36.72 19.512 ;
    END
  END dq[93]
  PIN dq[94]
    DIRECTION OUTPUT ;
    USE SIGNAL ;
    PORT
      LAYER M4 ;
        RECT  36.528 19.632 36.72 19.656 ;
    END
  END dq[94]
  PIN dq[95]
    DIRECTION OUTPUT ;
    USE SIGNAL ;
    PORT
      LAYER M4 ;
        RECT  36.528 19.824 36.72 19.848 ;
    END
  END dq[95]
  PIN dq[96]
    DIRECTION OUTPUT ;
    USE SIGNAL ;
    PORT
      LAYER M4 ;
        RECT  36.528 19.968 36.72 19.992 ;
    END
  END dq[96]
  PIN dq[97]
    DIRECTION OUTPUT ;
    USE SIGNAL ;
    PORT
      LAYER M4 ;
        RECT  36.528 20.112 36.72 20.136 ;
    END
  END dq[97]
  PIN dq[98]
    DIRECTION OUTPUT ;
    USE SIGNAL ;
    PORT
      LAYER M4 ;
        RECT  36.528 20.304 36.72 20.328 ;
    END
  END dq[98]
  PIN dq[99]
    DIRECTION OUTPUT ;
    USE SIGNAL ;
    PORT
      LAYER M4 ;
        RECT  36.528 20.448 36.72 20.472 ;
    END
  END dq[99]
  PIN dq[9]
    DIRECTION OUTPUT ;
    USE SIGNAL ;
    PORT
      LAYER M4 ;
        RECT  36.528 5.856 36.72 5.88 ;
    END
  END dq[9]
  PIN VDD
    DIRECTION INOUT ;
    USE POWER ;
    PORT
      LAYER M5 ;
        RECT  32.292 2.151 32.412 97.209 ;
        RECT  29.592 2.151 29.712 97.209 ;
        RECT  26.892 2.151 27.012 97.209 ;
        RECT  24.192 2.151 24.312 97.209 ;
        RECT  21.492 2.151 21.612 97.209 ;
        RECT  18.792 2.151 18.912 97.209 ;
        RECT  16.092 2.151 16.212 97.209 ;
        RECT  13.392 2.151 13.512 97.209 ;
        RECT  10.692 2.151 10.812 97.209 ;
        RECT  7.992 2.151 8.112 97.209 ;
        RECT  5.292 2.151 5.412 97.209 ;
        RECT  2.592 2.151 2.712 97.209 ;
    END
  END VDD
  PIN VSS
    DIRECTION INOUT ;
    USE GROUND ;
    PORT
      LAYER M5 ;
        RECT  32.1 2.137 32.22 97.223 ;
        RECT  29.4 2.137 29.52 97.223 ;
        RECT  26.7 2.137 26.82 97.223 ;
        RECT  24 2.137 24.12 97.223 ;
        RECT  21.3 2.137 21.42 97.223 ;
        RECT  18.6 2.137 18.72 97.223 ;
        RECT  15.9 2.137 16.02 97.223 ;
        RECT  13.2 2.137 13.32 97.223 ;
        RECT  10.5 2.137 10.62 97.223 ;
        RECT  7.8 2.137 7.92 97.223 ;
        RECT  5.1 2.137 5.22 97.223 ;
        RECT  2.4 2.137 2.52 97.223 ;
    END
  END VSS
  # OT_OBS_CLOSED layer=M5 d_um=1.536 added=70
  OBS
    LAYER RVTN ;
     RECT  2.16 2.16 34.56 2.295 ;
     RECT  2.16 2.565 34.56 2.835 ;
     RECT  2.16 3.105 34.56 3.375 ;
     RECT  2.16 3.645 34.56 3.915 ;
     RECT  2.16 4.185 34.56 4.455 ;
     RECT  2.16 4.725 34.56 4.995 ;
     RECT  2.16 5.265 34.56 5.535 ;
     RECT  2.16 5.805 34.56 6.075 ;
     RECT  2.16 6.345 34.56 6.615 ;
     RECT  2.16 6.885 34.56 7.155 ;
     RECT  2.16 7.425 34.56 7.695 ;
     RECT  2.16 7.965 34.56 8.235 ;
     RECT  2.16 8.505 34.56 8.775 ;
     RECT  2.16 9.045 34.56 9.315 ;
     RECT  2.16 9.585 34.56 9.855 ;
     RECT  2.16 10.125 34.56 10.395 ;
     RECT  2.16 10.665 34.56 10.935 ;
     RECT  2.16 11.205 34.56 11.475 ;
     RECT  2.16 11.745 34.56 12.015 ;
     RECT  2.16 12.285 34.56 12.555 ;
     RECT  2.16 12.825 34.56 13.095 ;
     RECT  2.16 13.365 34.56 13.635 ;
     RECT  2.16 13.905 34.56 14.175 ;
     RECT  2.16 14.445 34.56 14.715 ;
     RECT  2.16 14.985 34.56 15.255 ;
     RECT  2.16 15.525 34.56 15.795 ;
     RECT  2.16 16.065 34.56 16.335 ;
     RECT  2.16 16.605 34.56 16.875 ;
     RECT  2.16 17.145 34.56 17.415 ;
     RECT  2.16 17.685 34.56 17.955 ;
     RECT  2.16 18.225 34.56 18.495 ;
     RECT  2.16 18.765 34.56 19.035 ;
     RECT  2.16 19.305 34.56 19.575 ;
     RECT  2.16 19.845 34.56 20.115 ;
     RECT  2.16 20.385 34.56 20.655 ;
     RECT  2.16 20.925 34.56 21.195 ;
     RECT  2.16 21.465 34.56 21.735 ;
     RECT  2.16 22.005 34.56 22.275 ;
     RECT  2.16 22.545 34.56 22.815 ;
     RECT  2.16 23.085 34.56 23.355 ;
     RECT  2.16 23.625 34.56 23.895 ;
     RECT  2.16 24.165 34.56 24.435 ;
     RECT  2.16 24.705 34.56 24.975 ;
     RECT  2.16 25.245 34.56 25.515 ;
     RECT  2.16 25.785 34.56 26.055 ;
     RECT  2.16 26.325 34.56 26.595 ;
     RECT  2.16 26.865 34.56 27.135 ;
     RECT  2.16 27.405 34.56 27.675 ;
     RECT  2.16 27.945 34.56 28.215 ;
     RECT  2.16 28.485 34.56 28.755 ;
     RECT  2.16 29.025 34.56 29.295 ;
     RECT  2.16 29.565 34.56 29.835 ;
     RECT  2.16 30.105 34.56 30.375 ;
     RECT  2.16 30.645 34.56 30.915 ;
     RECT  2.16 31.185 34.56 31.455 ;
     RECT  2.16 31.725 34.56 31.995 ;
     RECT  2.16 32.265 34.56 32.535 ;
     RECT  2.16 32.805 34.56 33.075 ;
     RECT  2.16 33.345 34.56 33.615 ;
     RECT  2.16 33.885 34.56 34.155 ;
     RECT  2.16 34.425 34.56 34.695 ;
     RECT  2.16 34.965 34.56 35.235 ;
     RECT  2.16 35.505 34.56 35.775 ;
     RECT  2.16 36.045 34.56 36.315 ;
     RECT  2.16 36.585 34.56 36.855 ;
     RECT  2.16 37.125 34.56 37.395 ;
     RECT  2.16 37.665 34.56 37.935 ;
     RECT  2.16 38.205 34.56 38.475 ;
     RECT  2.16 38.745 34.56 39.015 ;
     RECT  2.16 39.285 34.56 39.555 ;
     RECT  2.16 39.825 34.56 40.095 ;
     RECT  2.16 40.365 34.56 40.635 ;
     RECT  2.16 40.905 34.56 41.175 ;
     RECT  2.16 41.445 34.56 41.715 ;
     RECT  2.16 41.985 34.56 42.255 ;
     RECT  2.16 42.525 34.56 42.795 ;
     RECT  2.16 43.065 34.56 43.335 ;
     RECT  2.16 43.605 34.56 43.875 ;
     RECT  2.16 44.145 34.56 44.415 ;
     RECT  2.16 44.685 34.56 44.955 ;
     RECT  2.16 45.225 34.56 45.495 ;
     RECT  2.16 45.765 34.56 46.035 ;
     RECT  2.16 46.305 34.56 46.575 ;
     RECT  2.16 46.845 34.56 47.115 ;
     RECT  2.16 47.385 34.56 47.655 ;
     RECT  2.16 47.925 34.56 48.195 ;
     RECT  2.16 48.465 34.56 48.735 ;
     RECT  2.16 49.005 34.56 49.275 ;
     RECT  2.16 49.545 34.56 49.815 ;
     RECT  2.16 50.085 34.56 50.355 ;
     RECT  2.16 50.625 34.56 50.895 ;
     RECT  2.16 51.165 34.56 51.435 ;
     RECT  2.16 51.705 34.56 51.975 ;
     RECT  2.16 52.245 34.56 52.515 ;
     RECT  2.16 52.785 34.56 53.055 ;
     RECT  2.16 53.325 34.56 53.595 ;
     RECT  2.16 53.865 34.56 54.135 ;
     RECT  2.16 54.405 34.56 54.675 ;
     RECT  2.16 54.945 34.56 55.215 ;
     RECT  2.16 55.485 34.56 55.755 ;
     RECT  2.16 56.025 34.56 56.295 ;
     RECT  2.16 56.565 34.56 56.835 ;
     RECT  2.16 57.105 34.56 57.375 ;
     RECT  2.16 57.645 34.56 57.915 ;
     RECT  2.16 58.185 34.56 58.455 ;
     RECT  2.16 58.725 34.56 58.995 ;
     RECT  2.16 59.265 34.56 59.535 ;
     RECT  2.16 59.805 34.56 60.075 ;
     RECT  2.16 60.345 34.56 60.615 ;
     RECT  2.16 60.885 34.56 61.155 ;
     RECT  2.16 61.425 34.56 61.695 ;
     RECT  2.16 61.965 34.56 62.235 ;
     RECT  2.16 62.505 34.56 62.775 ;
     RECT  2.16 63.045 34.56 63.315 ;
     RECT  2.16 63.585 34.56 63.855 ;
     RECT  2.16 64.125 34.56 64.395 ;
     RECT  2.16 64.665 34.56 64.935 ;
     RECT  2.16 65.205 34.56 65.475 ;
     RECT  2.16 65.745 34.56 66.015 ;
     RECT  2.16 66.285 34.56 66.555 ;
     RECT  2.16 66.825 34.56 67.095 ;
     RECT  2.16 67.365 34.56 67.635 ;
     RECT  2.16 67.905 34.56 68.175 ;
     RECT  2.16 68.445 34.56 68.715 ;
     RECT  2.16 68.985 34.56 69.255 ;
     RECT  2.16 69.525 34.56 69.795 ;
     RECT  2.16 70.065 34.56 70.335 ;
     RECT  2.16 70.605 34.56 70.875 ;
     RECT  2.16 71.145 34.56 71.415 ;
     RECT  2.16 71.685 34.56 71.955 ;
     RECT  2.16 72.225 34.56 72.495 ;
     RECT  2.16 72.765 34.56 73.035 ;
     RECT  2.16 73.305 34.56 73.575 ;
     RECT  2.16 73.845 34.56 74.115 ;
     RECT  2.16 74.385 34.56 74.655 ;
     RECT  2.16 74.925 34.56 75.195 ;
     RECT  2.16 75.465 34.56 75.735 ;
     RECT  2.16 76.005 34.56 76.275 ;
     RECT  2.16 76.545 34.56 76.815 ;
     RECT  2.16 77.085 34.56 77.355 ;
     RECT  2.16 77.625 34.56 77.895 ;
     RECT  2.16 78.165 34.56 78.435 ;
     RECT  2.16 78.705 34.56 78.975 ;
     RECT  2.16 79.245 34.56 79.515 ;
     RECT  2.16 79.785 34.56 80.055 ;
     RECT  2.16 80.325 34.56 80.595 ;
     RECT  2.16 80.865 34.56 81.135 ;
     RECT  2.16 81.405 34.56 81.675 ;
     RECT  2.16 81.945 34.56 82.215 ;
     RECT  2.16 82.485 34.56 82.755 ;
     RECT  2.16 83.025 34.56 83.295 ;
     RECT  2.16 83.565 34.56 83.835 ;
     RECT  2.16 84.105 34.56 84.375 ;
     RECT  2.16 84.645 34.56 84.915 ;
     RECT  2.16 85.185 34.56 85.455 ;
     RECT  2.16 85.725 34.56 85.995 ;
     RECT  2.16 86.265 34.56 86.535 ;
     RECT  2.16 86.805 34.56 87.075 ;
     RECT  2.16 87.345 34.56 87.615 ;
     RECT  2.16 87.885 34.56 88.155 ;
     RECT  2.16 88.425 34.56 88.695 ;
     RECT  2.16 88.965 34.56 89.235 ;
     RECT  2.16 89.505 34.56 89.775 ;
     RECT  2.16 90.045 34.56 90.315 ;
     RECT  2.16 90.585 34.56 90.855 ;
     RECT  2.16 91.125 34.56 91.395 ;
     RECT  2.16 91.665 34.56 91.935 ;
     RECT  2.16 92.205 34.56 92.475 ;
     RECT  2.16 92.745 34.56 93.015 ;
     RECT  2.16 93.285 34.56 93.555 ;
     RECT  2.16 93.825 34.56 94.095 ;
     RECT  2.16 94.365 34.56 94.635 ;
     RECT  2.16 94.905 34.56 95.175 ;
     RECT  2.16 95.445 34.56 95.715 ;
     RECT  2.16 95.985 34.56 96.255 ;
     RECT  2.16 96.525 34.56 96.795 ;
     RECT  2.16 97.065 34.56 97.2 ;
    LAYER RVTP ;
     RECT  2.16 2.295 34.56 2.565 ;
     RECT  2.16 2.835 34.56 3.105 ;
     RECT  2.16 3.375 34.56 3.645 ;
     RECT  2.16 3.915 34.56 4.185 ;
     RECT  2.16 4.455 34.56 4.725 ;
     RECT  2.16 4.995 34.56 5.265 ;
     RECT  2.16 5.535 34.56 5.805 ;
     RECT  2.16 6.075 34.56 6.345 ;
     RECT  2.16 6.615 34.56 6.885 ;
     RECT  2.16 7.155 34.56 7.425 ;
     RECT  2.16 7.695 34.56 7.965 ;
     RECT  2.16 8.235 34.56 8.505 ;
     RECT  2.16 8.775 34.56 9.045 ;
     RECT  2.16 9.315 34.56 9.585 ;
     RECT  2.16 9.855 34.56 10.125 ;
     RECT  2.16 10.395 34.56 10.665 ;
     RECT  2.16 10.935 34.56 11.205 ;
     RECT  2.16 11.475 34.56 11.745 ;
     RECT  2.16 12.015 34.56 12.285 ;
     RECT  2.16 12.555 34.56 12.825 ;
     RECT  2.16 13.095 34.56 13.365 ;
     RECT  2.16 13.635 34.56 13.905 ;
     RECT  2.16 14.175 34.56 14.445 ;
     RECT  2.16 14.715 34.56 14.985 ;
     RECT  2.16 15.255 34.56 15.525 ;
     RECT  2.16 15.795 34.56 16.065 ;
     RECT  2.16 16.335 34.56 16.605 ;
     RECT  2.16 16.875 34.56 17.145 ;
     RECT  2.16 17.415 34.56 17.685 ;
     RECT  2.16 17.955 34.56 18.225 ;
     RECT  2.16 18.495 34.56 18.765 ;
     RECT  2.16 19.035 34.56 19.305 ;
     RECT  2.16 19.575 34.56 19.845 ;
     RECT  2.16 20.115 34.56 20.385 ;
     RECT  2.16 20.655 34.56 20.925 ;
     RECT  2.16 21.195 34.56 21.465 ;
     RECT  2.16 21.735 34.56 22.005 ;
     RECT  2.16 22.275 34.56 22.545 ;
     RECT  2.16 22.815 34.56 23.085 ;
     RECT  2.16 23.355 34.56 23.625 ;
     RECT  2.16 23.895 34.56 24.165 ;
     RECT  2.16 24.435 34.56 24.705 ;
     RECT  2.16 24.975 34.56 25.245 ;
     RECT  2.16 25.515 34.56 25.785 ;
     RECT  2.16 26.055 34.56 26.325 ;
     RECT  2.16 26.595 34.56 26.865 ;
     RECT  2.16 27.135 34.56 27.405 ;
     RECT  2.16 27.675 34.56 27.945 ;
     RECT  2.16 28.215 34.56 28.485 ;
     RECT  2.16 28.755 34.56 29.025 ;
     RECT  2.16 29.295 34.56 29.565 ;
     RECT  2.16 29.835 34.56 30.105 ;
     RECT  2.16 30.375 34.56 30.645 ;
     RECT  2.16 30.915 34.56 31.185 ;
     RECT  2.16 31.455 34.56 31.725 ;
     RECT  2.16 31.995 34.56 32.265 ;
     RECT  2.16 32.535 34.56 32.805 ;
     RECT  2.16 33.075 34.56 33.345 ;
     RECT  2.16 33.615 34.56 33.885 ;
     RECT  2.16 34.155 34.56 34.425 ;
     RECT  2.16 34.695 34.56 34.965 ;
     RECT  2.16 35.235 34.56 35.505 ;
     RECT  2.16 35.775 34.56 36.045 ;
     RECT  2.16 36.315 34.56 36.585 ;
     RECT  2.16 36.855 34.56 37.125 ;
     RECT  2.16 37.395 34.56 37.665 ;
     RECT  2.16 37.935 34.56 38.205 ;
     RECT  2.16 38.475 34.56 38.745 ;
     RECT  2.16 39.015 34.56 39.285 ;
     RECT  2.16 39.555 34.56 39.825 ;
     RECT  2.16 40.095 34.56 40.365 ;
     RECT  2.16 40.635 34.56 40.905 ;
     RECT  2.16 41.175 34.56 41.445 ;
     RECT  2.16 41.715 34.56 41.985 ;
     RECT  2.16 42.255 34.56 42.525 ;
     RECT  2.16 42.795 34.56 43.065 ;
     RECT  2.16 43.335 34.56 43.605 ;
     RECT  2.16 43.875 34.56 44.145 ;
     RECT  2.16 44.415 34.56 44.685 ;
     RECT  2.16 44.955 34.56 45.225 ;
     RECT  2.16 45.495 34.56 45.765 ;
     RECT  2.16 46.035 34.56 46.305 ;
     RECT  2.16 46.575 34.56 46.845 ;
     RECT  2.16 47.115 34.56 47.385 ;
     RECT  2.16 47.655 34.56 47.925 ;
     RECT  2.16 48.195 34.56 48.465 ;
     RECT  2.16 48.735 34.56 49.005 ;
     RECT  2.16 49.275 34.56 49.545 ;
     RECT  2.16 49.815 34.56 50.085 ;
     RECT  2.16 50.355 34.56 50.625 ;
     RECT  2.16 50.895 34.56 51.165 ;
     RECT  2.16 51.435 34.56 51.705 ;
     RECT  2.16 51.975 34.56 52.245 ;
     RECT  2.16 52.515 34.56 52.785 ;
     RECT  2.16 53.055 34.56 53.325 ;
     RECT  2.16 53.595 34.56 53.865 ;
     RECT  2.16 54.135 34.56 54.405 ;
     RECT  2.16 54.675 34.56 54.945 ;
     RECT  2.16 55.215 34.56 55.485 ;
     RECT  2.16 55.755 34.56 56.025 ;
     RECT  2.16 56.295 34.56 56.565 ;
     RECT  2.16 56.835 34.56 57.105 ;
     RECT  2.16 57.375 34.56 57.645 ;
     RECT  2.16 57.915 34.56 58.185 ;
     RECT  2.16 58.455 34.56 58.725 ;
     RECT  2.16 58.995 34.56 59.265 ;
     RECT  2.16 59.535 34.56 59.805 ;
     RECT  2.16 60.075 34.56 60.345 ;
     RECT  2.16 60.615 34.56 60.885 ;
     RECT  2.16 61.155 34.56 61.425 ;
     RECT  2.16 61.695 34.56 61.965 ;
     RECT  2.16 62.235 34.56 62.505 ;
     RECT  2.16 62.775 34.56 63.045 ;
     RECT  2.16 63.315 34.56 63.585 ;
     RECT  2.16 63.855 34.56 64.125 ;
     RECT  2.16 64.395 34.56 64.665 ;
     RECT  2.16 64.935 34.56 65.205 ;
     RECT  2.16 65.475 34.56 65.745 ;
     RECT  2.16 66.015 34.56 66.285 ;
     RECT  2.16 66.555 34.56 66.825 ;
     RECT  2.16 67.095 34.56 67.365 ;
     RECT  2.16 67.635 34.56 67.905 ;
     RECT  2.16 68.175 34.56 68.445 ;
     RECT  2.16 68.715 34.56 68.985 ;
     RECT  2.16 69.255 34.56 69.525 ;
     RECT  2.16 69.795 34.56 70.065 ;
     RECT  2.16 70.335 34.56 70.605 ;
     RECT  2.16 70.875 34.56 71.145 ;
     RECT  2.16 71.415 34.56 71.685 ;
     RECT  2.16 71.955 34.56 72.225 ;
     RECT  2.16 72.495 34.56 72.765 ;
     RECT  2.16 73.035 34.56 73.305 ;
     RECT  2.16 73.575 34.56 73.845 ;
     RECT  2.16 74.115 34.56 74.385 ;
     RECT  2.16 74.655 34.56 74.925 ;
     RECT  2.16 75.195 34.56 75.465 ;
     RECT  2.16 75.735 34.56 76.005 ;
     RECT  2.16 76.275 34.56 76.545 ;
     RECT  2.16 76.815 34.56 77.085 ;
     RECT  2.16 77.355 34.56 77.625 ;
     RECT  2.16 77.895 34.56 78.165 ;
     RECT  2.16 78.435 34.56 78.705 ;
     RECT  2.16 78.975 34.56 79.245 ;
     RECT  2.16 79.515 34.56 79.785 ;
     RECT  2.16 80.055 34.56 80.325 ;
     RECT  2.16 80.595 34.56 80.865 ;
     RECT  2.16 81.135 34.56 81.405 ;
     RECT  2.16 81.675 34.56 81.945 ;
     RECT  2.16 82.215 34.56 82.485 ;
     RECT  2.16 82.755 34.56 83.025 ;
     RECT  2.16 83.295 34.56 83.565 ;
     RECT  2.16 83.835 34.56 84.105 ;
     RECT  2.16 84.375 34.56 84.645 ;
     RECT  2.16 84.915 34.56 85.185 ;
     RECT  2.16 85.455 34.56 85.725 ;
     RECT  2.16 85.995 34.56 86.265 ;
     RECT  2.16 86.535 34.56 86.805 ;
     RECT  2.16 87.075 34.56 87.345 ;
     RECT  2.16 87.615 34.56 87.885 ;
     RECT  2.16 88.155 34.56 88.425 ;
     RECT  2.16 88.695 34.56 88.965 ;
     RECT  2.16 89.235 34.56 89.505 ;
     RECT  2.16 89.775 34.56 90.045 ;
     RECT  2.16 90.315 34.56 90.585 ;
     RECT  2.16 90.855 34.56 91.125 ;
     RECT  2.16 91.395 34.56 91.665 ;
     RECT  2.16 91.935 34.56 92.205 ;
     RECT  2.16 92.475 34.56 92.745 ;
     RECT  2.16 93.015 34.56 93.285 ;
     RECT  2.16 93.555 34.56 93.825 ;
     RECT  2.16 94.095 34.56 94.365 ;
     RECT  2.16 94.635 34.56 94.905 ;
     RECT  2.16 95.175 34.56 95.445 ;
     RECT  2.16 95.715 34.56 95.985 ;
     RECT  2.16 96.255 34.56 96.525 ;
     RECT  2.16 96.795 34.56 97.065 ;
    LAYER M1 ;
     RECT  2.16 2.151 34.56 97.209 ;
    LAYER M2 ;
     RECT  0.535 14.22 2.16 14.238 ;
     RECT  0.211 37.602 2.16 37.62 ;
     RECT  0.535 39.87 2.16 39.888 ;
     RECT  0.319 58.122 2.16 58.14 ;
     RECT  0.535 79.758 2.16 79.776 ;
     RECT  18.175 99.198 18.383 99.216 ;
     RECT  2.16 2.151 34.56 97.209 ;
     RECT  34.56 94.878 34.583 96.444 ;
     RECT  34.56 3.618 34.763 58.248 ;
     RECT  34.56 59.004 34.763 73.764 ;
     RECT  34.56 82.728 34.763 93.924 ;
     RECT  34.763 3.618 34.799 41.778 ;
     RECT  34.763 59.004 34.799 68.004 ;
     RECT  34.763 68.796 34.799 73.764 ;
     RECT  34.763 82.728 34.799 93.852 ;
     RECT  34.583 94.878 34.799 95.364 ;
     RECT  34.799 82.728 34.835 88.722 ;
     RECT  34.799 89.748 34.835 93.852 ;
     RECT  34.799 94.878 34.979 94.896 ;
     RECT  34.583 96.156 35.051 96.444 ;
     RECT  35.051 96.426 35.087 96.444 ;
     RECT  34.799 6.246 35.339 19.764 ;
     RECT  34.799 3.618 35.375 5.094 ;
     RECT  35.339 6.246 35.375 19.674 ;
     RECT  34.799 20.664 35.375 41.778 ;
     RECT  34.763 42.534 35.375 58.248 ;
     RECT  34.799 59.004 35.375 62.262 ;
     RECT  34.799 63.09 35.375 68.004 ;
     RECT  34.799 68.796 35.375 73.638 ;
     RECT  34.56 74.664 35.375 81.864 ;
     RECT  34.835 84.15 35.375 88.524 ;
     RECT  34.835 90.594 35.375 93.852 ;
     RECT  35.375 8.586 35.411 11.268 ;
     RECT  35.375 20.664 35.411 21.024 ;
     RECT  35.375 21.816 35.411 22.032 ;
     RECT  35.375 34.128 35.411 39.924 ;
     RECT  35.375 3.618 35.447 4.554 ;
     RECT  35.375 74.664 35.447 81.504 ;
     RECT  35.375 42.534 35.807 48.456 ;
     RECT  35.375 59.166 35.915 60.138 ;
     RECT  34.835 89.748 35.915 89.802 ;
     RECT  35.447 3.618 35.951 4.374 ;
     RECT  35.375 6.246 35.951 7.722 ;
     RECT  35.411 8.586 35.951 8.874 ;
     RECT  35.411 9.936 35.951 11.268 ;
     RECT  35.375 12.06 35.951 19.674 ;
     RECT  35.411 20.664 35.951 20.754 ;
     RECT  35.411 21.816 35.951 21.834 ;
     RECT  35.375 23.436 35.951 24.966 ;
     RECT  35.375 25.83 35.951 32.364 ;
     RECT  35.375 33.156 35.951 33.372 ;
     RECT  35.411 34.128 35.951 35.802 ;
     RECT  35.411 36.594 35.951 39.924 ;
     RECT  35.375 40.68 35.951 41.778 ;
     RECT  35.807 42.534 35.951 46.134 ;
     RECT  35.807 46.926 35.951 48.456 ;
     RECT  35.375 49.356 35.951 49.644 ;
     RECT  35.375 50.4 35.951 57.438 ;
     RECT  35.375 58.23 35.951 58.248 ;
     RECT  35.915 59.274 35.951 60.138 ;
     RECT  35.375 61.164 35.951 61.758 ;
     RECT  35.375 63.09 35.951 63.342 ;
     RECT  35.375 64.476 35.951 68.004 ;
     RECT  35.375 69.336 35.951 69.624 ;
     RECT  35.375 70.416 35.951 73.638 ;
     RECT  35.447 74.664 35.951 77.994 ;
     RECT  35.447 78.984 35.951 81.504 ;
     RECT  34.835 82.728 35.951 83.394 ;
     RECT  35.375 84.384 35.951 88.488 ;
     RECT  35.915 89.784 35.951 89.802 ;
     RECT  35.375 90.594 35.951 93.384 ;
     RECT  35.951 3.618 35.987 3.636 ;
     RECT  35.951 8.856 35.987 8.874 ;
     RECT  35.951 10.206 35.987 10.809 ;
     RECT  35.951 12.33 35.987 12.348 ;
     RECT  35.951 13.986 35.987 14.004 ;
     RECT  35.951 14.76 35.987 14.778 ;
     RECT  35.951 19.656 35.987 19.674 ;
     RECT  35.951 20.736 35.987 20.754 ;
     RECT  35.951 23.868 35.987 23.886 ;
     RECT  35.951 25.866 35.987 27.162 ;
     RECT  35.951 29.304 35.987 31.518 ;
     RECT  35.951 33.354 35.987 33.372 ;
     RECT  35.951 34.236 35.987 34.794 ;
     RECT  35.951 36.594 35.987 36.918 ;
     RECT  35.951 37.71 35.987 37.962 ;
     RECT  35.951 40.68 35.987 41.202 ;
     RECT  35.951 42.534 35.987 43.164 ;
     RECT  35.951 43.956 35.987 44.514 ;
     RECT  35.951 45.846 35.987 45.864 ;
     RECT  35.951 46.926 35.987 47.754 ;
     RECT  35.951 50.634 35.987 51.192 ;
     RECT  35.951 53.406 35.987 54.504 ;
     RECT  35.951 55.494 35.987 55.512 ;
     RECT  35.951 56.34 35.987 56.934 ;
     RECT  35.951 59.346 35.987 60.138 ;
     RECT  35.951 61.74 35.987 61.758 ;
     RECT  35.951 63.126 35.987 63.144 ;
     RECT  35.951 64.746 35.987 66.276 ;
     RECT  35.951 67.914 35.987 67.932 ;
     RECT  35.951 69.606 35.987 69.624 ;
     RECT  35.951 72.468 35.987 72.828 ;
     RECT  35.951 74.934 35.987 74.952 ;
     RECT  35.951 75.978 35.987 76.266 ;
     RECT  35.951 77.4 35.987 77.724 ;
     RECT  35.951 79.326 35.987 80.118 ;
     RECT  35.951 81.108 35.987 81.126 ;
     RECT  35.951 82.764 35.987 83.052 ;
     RECT  35.951 85.266 35.987 86.022 ;
     RECT  35.951 86.814 35.987 86.832 ;
     RECT  35.951 87.588 35.987 87.606 ;
     RECT  35.951 92.556 35.987 93.042 ;
     RECT  35.987 10.476 36.023 10.809 ;
     RECT  35.951 17.694 36.023 17.712 ;
     RECT  35.987 25.866 36.023 25.884 ;
     RECT  35.987 30.186 36.023 30.204 ;
     RECT  35.987 30.996 36.023 31.518 ;
     RECT  35.987 36.9 36.023 36.918 ;
     RECT  35.987 37.944 36.023 37.962 ;
     RECT  35.987 40.68 36.023 40.698 ;
     RECT  35.987 42.534 36.023 42.552 ;
     RECT  35.987 43.956 36.023 43.974 ;
     RECT  35.987 47.286 36.023 47.304 ;
     RECT  35.987 59.508 36.023 60.138 ;
     RECT  35.987 65.25 36.023 66.114 ;
     RECT  35.987 72.81 36.023 72.828 ;
     RECT  35.951 73.62 36.023 73.638 ;
     RECT  35.987 76.248 36.023 76.266 ;
     RECT  35.987 79.596 36.023 79.614 ;
     RECT  35.987 83.034 36.023 83.052 ;
     RECT  35.987 85.428 36.023 85.446 ;
     RECT  35.951 88.434 36.023 88.452 ;
     RECT  35.951 90.936 36.023 91.224 ;
     RECT  35.987 92.826 36.023 92.844 ;
     RECT  36.023 10.746 36.059 10.764 ;
     RECT  35.987 56.574 36.059 56.934 ;
     RECT  36.023 65.826 36.059 65.844 ;
     RECT  36.059 56.574 36.095 56.592 ;
    LAYER M3 ;
     RECT  2.415 2.143 2.505 2.413 ;
     RECT  5.115 2.143 5.205 2.413 ;
     RECT  7.815 2.143 7.905 2.413 ;
     RECT  10.515 2.143 10.605 2.413 ;
     RECT  13.215 2.143 13.305 2.413 ;
     RECT  15.915 2.143 16.005 2.413 ;
     RECT  18.615 2.143 18.705 2.413 ;
     RECT  21.315 2.143 21.405 2.413 ;
     RECT  24.015 2.143 24.105 2.413 ;
     RECT  26.715 2.143 26.805 2.413 ;
     RECT  29.415 2.143 29.505 2.413 ;
     RECT  32.115 2.143 32.205 2.413 ;
     RECT  34.2 3.145 34.218 3.181 ;
     RECT  34.2 3.181 34.434 3.379 ;
     RECT  33.804 3.379 34.434 3.685 ;
     RECT  35.964 3.613 35.982 3.721 ;
     RECT  2.415 2.413 2.697 4.225 ;
     RECT  32.115 2.413 32.397 4.225 ;
     RECT  33.3 3.685 34.434 4.225 ;
     RECT  2.415 4.225 3.294 4.261 ;
     RECT  2.415 4.261 3.438 4.541 ;
     RECT  2.415 4.541 2.697 4.555 ;
     RECT  7.815 2.413 8.097 4.621 ;
     RECT  5.115 2.413 5.397 4.765 ;
     RECT  7.416 4.621 8.097 4.765 ;
     RECT  32.115 4.225 34.434 4.801 ;
     RECT  35.352 3.721 35.982 4.801 ;
     RECT  2.412 4.555 2.697 4.891 ;
     RECT  5.115 4.765 5.49 4.927 ;
     RECT  30.852 4.927 30.87 4.963 ;
     RECT  30.78 4.963 30.87 5.027 ;
     RECT  3.924 4.801 3.978 5.035 ;
     RECT  5.115 4.927 5.562 5.035 ;
     RECT  32.115 4.801 35.982 5.069 ;
     RECT  3.924 5.035 4.158 5.071 ;
     RECT  5.115 5.035 5.67 5.161 ;
     RECT  3.924 5.071 4.302 5.197 ;
     RECT  10.515 2.413 10.797 5.269 ;
     RECT  7.128 4.765 8.097 5.305 ;
     RECT  2.304 4.891 2.697 5.341 ;
     RECT  5.115 5.161 6.21 5.341 ;
     RECT  7.128 5.305 8.478 5.341 ;
     RECT  10.515 5.269 10.818 5.369 ;
     RECT  30.78 5.027 30.798 5.369 ;
     RECT  35.352 5.069 35.982 5.405 ;
     RECT  9.684 4.963 9.702 5.431 ;
     RECT  9.684 5.431 9.774 5.531 ;
     RECT  2.304 5.341 2.934 5.563 ;
     RECT  3.924 5.197 4.374 5.563 ;
     RECT  5.115 5.341 8.478 5.563 ;
     RECT  3.924 5.563 8.478 5.597 ;
     RECT  35.352 5.405 35.442 5.597 ;
     RECT  32.115 5.069 34.434 5.809 ;
     RECT  2.304 5.563 3.186 5.881 ;
     RECT  3.924 5.597 8.406 5.881 ;
     RECT  32.115 5.809 34.794 5.971 ;
     RECT  2.304 5.881 8.406 6.269 ;
     RECT  9.504 6.151 9.522 6.269 ;
     RECT  31.788 5.971 34.794 6.269 ;
     RECT  32.115 6.269 34.794 6.365 ;
     RECT  2.304 6.269 6.102 6.809 ;
     RECT  3.996 6.809 6.102 6.881 ;
     RECT  6.84 6.269 8.406 6.961 ;
     RECT  6.84 6.961 8.442 7.079 ;
     RECT  4.032 6.881 6.102 7.189 ;
     RECT  6.84 7.079 8.154 7.189 ;
     RECT  32.115 6.365 34.434 7.393 ;
     RECT  35.928 6.241 35.946 7.393 ;
     RECT  32.004 7.393 34.434 7.771 ;
     RECT  35.352 7.393 35.946 7.771 ;
     RECT  9.432 7.771 9.45 7.889 ;
     RECT  2.304 6.809 3.258 7.969 ;
     RECT  4.032 7.189 8.154 7.969 ;
     RECT  2.304 7.969 8.154 8.131 ;
     RECT  32.004 7.771 35.946 8.231 ;
     RECT  2.304 8.131 8.19 8.311 ;
     RECT  2.304 8.311 8.298 8.429 ;
     RECT  2.304 8.429 3.294 8.537 ;
     RECT  32.115 8.231 35.946 8.635 ;
     RECT  4.212 8.429 6.21 8.735 ;
     RECT  32.115 8.635 35.982 8.879 ;
     RECT  32.115 8.879 35.946 9.041 ;
     RECT  32.115 9.041 34.254 9.085 ;
     RECT  2.304 8.537 3.078 9.112 ;
     RECT  30.78 7.051 30.798 9.247 ;
     RECT  2.268 9.112 3.078 9.391 ;
     RECT  30.78 9.247 30.87 9.419 ;
     RECT  2.268 9.391 3.222 9.661 ;
     RECT  35.352 9.041 35.946 9.739 ;
     RECT  7.092 8.429 8.097 9.751 ;
     RECT  31.932 9.085 34.254 9.779 ;
     RECT  2.268 9.661 3.258 9.931 ;
     RECT  4.248 8.735 6.21 9.931 ;
     RECT  31.932 9.779 34.218 10.021 ;
     RECT  2.268 9.931 6.21 10.057 ;
     RECT  7.056 9.751 8.097 10.057 ;
     RECT  35.352 9.739 35.982 10.075 ;
     RECT  31.716 10.021 34.218 10.121 ;
     RECT  2.268 10.057 8.097 10.157 ;
     RECT  2.304 10.157 8.097 10.229 ;
     RECT  30.78 9.419 30.798 10.327 ;
     RECT  30.78 10.327 30.87 10.427 ;
     RECT  6.372 10.229 8.097 10.471 ;
     RECT  35.352 10.075 36.054 10.555 ;
     RECT  6.372 10.471 8.802 10.661 ;
     RECT  6.372 10.661 6.39 10.697 ;
     RECT  30.78 10.427 30.798 10.733 ;
     RECT  7.128 10.661 8.802 10.769 ;
     RECT  35.316 10.555 36.054 10.769 ;
     RECT  35.316 10.769 36.018 10.814 ;
     RECT  35.316 10.814 35.946 10.859 ;
     RECT  32.076 10.121 34.218 10.939 ;
     RECT  2.304 10.229 5.634 11.011 ;
     RECT  7.128 10.769 8.226 11.273 ;
     RECT  2.304 11.011 6.354 11.371 ;
     RECT  32.076 10.939 34.29 11.371 ;
     RECT  31.536 11.371 34.29 11.399 ;
     RECT  2.268 11.371 6.354 11.507 ;
     RECT  2.304 11.507 6.354 11.551 ;
     RECT  7.128 11.273 8.154 11.551 ;
     RECT  30.78 11.749 30.798 11.849 ;
     RECT  31.536 11.399 34.254 11.849 ;
     RECT  0.252 11.755 0.27 11.885 ;
     RECT  9.144 11.821 9.378 11.939 ;
     RECT  35.352 10.859 35.946 12.043 ;
     RECT  2.304 11.551 8.154 12.091 ;
     RECT  35.352 12.043 35.982 12.221 ;
     RECT  31.752 11.849 34.254 12.289 ;
     RECT  2.304 12.091 8.19 12.325 ;
     RECT  35.928 12.221 35.982 12.353 ;
     RECT  2.304 12.325 8.298 12.451 ;
     RECT  30.78 12.757 30.798 12.793 ;
     RECT  31.752 12.289 34.794 13.019 ;
     RECT  30.78 12.793 30.87 13.027 ;
     RECT  32.115 13.019 34.794 13.037 ;
     RECT  2.304 12.451 8.586 13.559 ;
     RECT  9.432 13.441 9.45 13.559 ;
     RECT  6.948 13.559 8.586 13.613 ;
     RECT  35.928 12.353 35.946 13.627 ;
     RECT  7.056 13.613 8.586 13.703 ;
     RECT  7.056 13.703 8.514 13.739 ;
     RECT  32.115 13.037 34.362 13.819 ;
     RECT  32.115 13.819 34.794 13.901 ;
     RECT  2.304 13.559 6.174 13.945 ;
     RECT  30.78 13.027 31.338 13.945 ;
     RECT  2.268 13.945 6.174 13.997 ;
     RECT  2.304 13.997 6.174 14.009 ;
     RECT  35.928 13.627 35.982 14.009 ;
     RECT  0.54 14.215 0.558 14.333 ;
     RECT  30.78 13.945 31.374 14.341 ;
     RECT  32.115 13.901 34.254 14.341 ;
     RECT  7.164 13.739 8.514 14.369 ;
     RECT  35.928 14.009 35.946 14.635 ;
     RECT  7.164 14.369 8.298 14.639 ;
     RECT  3.42 14.009 6.174 14.683 ;
     RECT  35.316 14.635 35.946 14.755 ;
     RECT  3.42 14.683 6.966 14.819 ;
     RECT  7.815 14.639 8.298 14.957 ;
     RECT  35.316 14.755 35.982 14.957 ;
     RECT  6.732 14.819 6.966 15.053 ;
     RECT  9.432 15.025 9.45 15.215 ;
     RECT  2.304 14.009 2.697 15.259 ;
     RECT  3.42 14.819 5.706 15.259 ;
     RECT  30.78 14.341 34.254 15.259 ;
     RECT  35.316 14.957 35.946 15.259 ;
     RECT  30.78 15.259 35.946 15.296 ;
     RECT  30.78 15.296 34.254 15.359 ;
     RECT  6.948 15.053 6.966 15.403 ;
     RECT  7.815 14.957 8.097 15.403 ;
     RECT  31.572 15.359 34.254 15.449 ;
     RECT  35.352 15.296 35.946 15.449 ;
     RECT  2.304 15.259 5.706 15.565 ;
     RECT  2.304 15.565 5.958 15.601 ;
     RECT  0.396 15.595 0.414 15.739 ;
     RECT  0.216 15.739 0.414 15.773 ;
     RECT  0.216 15.773 0.234 15.869 ;
     RECT  2.304 15.601 6.21 15.871 ;
     RECT  6.948 15.403 8.097 15.871 ;
     RECT  30.78 15.359 30.798 15.899 ;
     RECT  2.304 15.871 8.097 16.219 ;
     RECT  35.892 15.449 35.946 16.219 ;
     RECT  32.115 15.449 34.254 16.231 ;
     RECT  8.928 15.871 8.946 16.259 ;
     RECT  2.268 16.219 8.097 16.367 ;
     RECT  31.896 16.231 34.254 16.375 ;
     RECT  2.304 16.367 8.097 16.411 ;
     RECT  21.315 2.413 21.597 16.411 ;
     RECT  31.572 16.375 34.254 16.501 ;
     RECT  35.352 16.219 35.946 16.529 ;
     RECT  31.32 16.501 34.254 16.645 ;
     RECT  31.32 16.645 34.434 16.681 ;
     RECT  21.096 16.411 21.597 16.709 ;
     RECT  31.248 16.681 34.434 16.843 ;
     RECT  30.78 16.843 34.434 16.943 ;
     RECT  31.428 16.943 34.434 17.035 ;
     RECT  2.304 16.411 8.37 17.117 ;
     RECT  9.684 17.221 9.702 17.339 ;
     RECT  7.272 17.117 8.37 17.581 ;
     RECT  2.304 17.117 6.534 17.609 ;
     RECT  7.272 17.581 8.586 17.645 ;
     RECT  35.928 16.529 35.946 17.689 ;
     RECT  31.428 17.035 34.794 17.725 ;
     RECT  7.416 17.645 8.586 17.789 ;
     RECT  2.304 17.609 6.282 17.851 ;
     RECT  35.928 17.689 36.018 17.851 ;
     RECT  30.78 17.725 34.794 17.879 ;
     RECT  35.892 17.851 36.018 18.029 ;
     RECT  32.004 17.879 34.794 18.059 ;
     RECT  35.892 18.029 35.946 18.301 ;
     RECT  7.416 17.789 8.097 18.419 ;
     RECT  9.108 18.121 9.126 18.419 ;
     RECT  2.268 17.851 6.282 18.571 ;
     RECT  7.815 18.419 8.097 18.571 ;
     RECT  35.856 18.301 35.946 18.667 ;
     RECT  2.268 18.571 7.074 18.725 ;
     RECT  7.815 18.571 8.514 18.833 ;
     RECT  2.304 18.725 7.074 18.869 ;
     RECT  32.004 18.059 34.218 19.003 ;
     RECT  35.316 18.667 35.946 19.003 ;
     RECT  32.004 19.003 35.946 19.201 ;
     RECT  31.968 19.201 35.946 19.273 ;
     RECT  3.996 18.869 7.074 19.499 ;
     RECT  9.252 19.381 9.27 19.571 ;
     RECT  3.996 19.499 6.246 19.615 ;
     RECT  6.984 19.499 7.074 19.615 ;
     RECT  7.815 18.833 8.097 19.615 ;
     RECT  31.932 19.273 35.946 19.627 ;
     RECT  2.304 18.869 3.042 19.651 ;
     RECT  3.816 19.615 6.246 19.651 ;
     RECT  31.932 19.627 35.982 19.769 ;
     RECT  2.304 19.651 6.246 19.949 ;
     RECT  31.932 19.769 34.794 20.011 ;
     RECT  30.78 17.879 30.87 20.147 ;
     RECT  31.68 20.011 34.794 20.309 ;
     RECT  6.984 19.615 8.097 20.425 ;
     RECT  6.948 20.425 8.097 20.453 ;
     RECT  0.252 20.347 0.27 20.477 ;
     RECT  31.896 20.309 34.794 20.587 ;
     RECT  35.892 19.769 35.982 20.587 ;
     RECT  2.304 19.949 5.814 20.695 ;
     RECT  2.304 20.695 6.138 20.731 ;
     RECT  6.948 20.453 6.966 20.731 ;
     RECT  7.815 20.453 8.097 20.731 ;
     RECT  31.896 20.587 35.982 20.759 ;
     RECT  21.315 16.709 21.597 20.827 ;
     RECT  29.415 2.413 29.697 20.827 ;
     RECT  7.815 20.731 8.19 20.857 ;
     RECT  14.832 20.827 14.85 20.957 ;
     RECT  21.315 20.827 21.69 20.957 ;
     RECT  22.824 20.827 22.842 20.957 ;
     RECT  29.415 20.827 29.79 20.957 ;
     RECT  9.216 20.695 9.234 21.001 ;
     RECT  30.78 20.147 30.834 21.091 ;
     RECT  31.896 20.759 35.946 21.091 ;
     RECT  30.78 21.091 35.946 21.191 ;
     RECT  30.78 21.191 30.87 21.263 ;
     RECT  7.815 20.857 8.262 21.271 ;
     RECT  9.216 21.001 9.342 21.271 ;
     RECT  7.815 21.271 9.414 21.389 ;
     RECT  7.815 21.389 8.802 21.497 ;
     RECT  2.304 20.731 6.966 21.505 ;
     RECT  7.815 21.497 8.406 21.505 ;
     RECT  2.304 21.505 8.406 21.569 ;
     RECT  31.968 21.191 35.946 21.569 ;
     RECT  0.216 21.499 0.234 21.629 ;
     RECT  32.004 21.569 35.946 21.659 ;
     RECT  2.304 21.569 6.246 21.731 ;
     RECT  34.74 21.659 35.946 21.839 ;
     RECT  4.284 21.731 6.246 21.929 ;
     RECT  32.004 21.659 34.002 21.929 ;
     RECT  2.304 21.731 3.51 21.971 ;
     RECT  2.304 21.971 3.474 22.072 ;
     RECT  30.78 21.263 30.798 22.073 ;
     RECT  2.268 22.072 3.474 22.109 ;
     RECT  32.04 21.929 34.002 22.411 ;
     RECT  34.74 21.839 35.406 22.411 ;
     RECT  7.164 21.569 8.406 22.585 ;
     RECT  10.515 5.369 10.797 22.612 ;
     RECT  32.04 22.411 35.406 22.699 ;
     RECT  10.515 22.612 10.818 22.739 ;
     RECT  4.284 21.929 6.21 22.747 ;
     RECT  7.164 22.585 9.126 22.747 ;
     RECT  2.304 22.109 3.474 22.783 ;
     RECT  4.284 22.747 9.126 22.783 ;
     RECT  2.304 22.783 9.126 22.811 ;
     RECT  3.78 22.811 9.054 22.847 ;
     RECT  32.04 22.699 35.946 22.891 ;
     RECT  2.304 22.811 2.862 23.009 ;
     RECT  6.804 22.847 9.054 23.009 ;
     RECT  2.304 23.009 2.697 23.179 ;
     RECT  31.896 22.891 35.946 23.279 ;
     RECT  3.78 22.847 5.958 23.593 ;
     RECT  6.804 23.009 8.097 23.629 ;
     RECT  9.036 23.009 9.054 23.791 ;
     RECT  10.515 22.739 10.797 23.791 ;
     RECT  9.036 23.791 9.306 23.819 ;
     RECT  3.6 23.593 5.958 23.827 ;
     RECT  2.268 23.179 2.697 23.855 ;
     RECT  32.112 23.279 35.946 23.863 ;
     RECT  10.515 23.791 10.854 23.927 ;
     RECT  30.78 23.791 30.798 23.927 ;
     RECT  32.112 23.863 35.982 24.029 ;
     RECT  6.768 23.629 8.097 24.089 ;
     RECT  32.112 24.029 35.946 24.169 ;
     RECT  7.416 24.089 8.097 24.205 ;
     RECT  2.304 23.855 2.697 24.241 ;
     RECT  3.6 23.827 5.994 24.241 ;
     RECT  31.932 24.169 35.946 24.269 ;
     RECT  7.416 24.205 8.19 24.359 ;
     RECT  2.304 24.241 2.826 24.619 ;
     RECT  3.6 24.241 6.534 24.619 ;
     RECT  31.932 24.269 34.326 24.629 ;
     RECT  9.288 23.819 9.306 24.701 ;
     RECT  30.852 24.403 30.87 24.745 ;
     RECT  2.304 24.619 6.534 24.811 ;
     RECT  2.268 24.811 6.534 25.051 ;
     RECT  7.416 24.359 8.097 25.051 ;
     RECT  31.932 24.629 34.254 25.079 ;
     RECT  2.268 25.051 8.097 25.085 ;
     RECT  35.352 24.269 35.946 25.181 ;
     RECT  2.268 25.085 5.958 25.205 ;
     RECT  30.78 24.745 30.87 25.313 ;
     RECT  6.84 25.085 8.097 25.321 ;
     RECT  6.84 25.321 8.226 25.439 ;
     RECT  30.78 25.313 30.798 25.439 ;
     RECT  6.84 25.439 8.154 25.583 ;
     RECT  35.928 25.181 35.946 25.627 ;
     RECT  6.84 25.583 8.097 25.709 ;
     RECT  32.115 25.079 34.254 25.861 ;
     RECT  35.928 25.627 36.018 25.889 ;
     RECT  35.928 25.889 35.982 25.951 ;
     RECT  9.576 25.591 9.594 25.979 ;
     RECT  32.076 25.861 34.254 25.979 ;
     RECT  2.304 25.205 5.958 26.095 ;
     RECT  32.115 25.979 34.254 26.095 ;
     RECT  32.115 26.095 34.326 26.299 ;
     RECT  35.352 25.951 35.982 26.299 ;
     RECT  2.304 26.095 5.994 26.401 ;
     RECT  2.304 26.401 6.354 26.527 ;
     RECT  7.164 25.709 8.097 26.527 ;
     RECT  10.515 23.927 10.797 26.527 ;
     RECT  0.252 25.963 0.27 26.573 ;
     RECT  10.515 26.527 10.854 26.627 ;
     RECT  30.78 26.527 30.798 26.627 ;
     RECT  32.115 26.299 35.982 26.663 ;
     RECT  9.396 26.671 9.414 26.833 ;
     RECT  2.304 26.527 8.097 26.861 ;
     RECT  32.115 26.663 34.758 26.869 ;
     RECT  31.608 26.869 34.758 27.031 ;
     RECT  8.892 26.833 9.414 27.131 ;
     RECT  3.78 26.861 8.097 27.167 ;
     RECT  9.396 27.131 9.414 27.239 ;
     RECT  35.928 26.663 35.982 27.293 ;
     RECT  3.96 27.167 8.097 27.301 ;
     RECT  30.852 27.031 34.758 27.595 ;
     RECT  35.928 27.293 35.946 27.595 ;
     RECT  3.96 27.301 8.586 27.671 ;
     RECT  2.304 26.861 2.79 27.679 ;
     RECT  30.852 27.595 35.946 27.743 ;
     RECT  3.96 27.671 6.93 27.779 ;
     RECT  31.068 27.743 35.946 27.941 ;
     RECT  3.96 27.779 6.858 28.021 ;
     RECT  7.815 27.671 8.586 28.049 ;
     RECT  31.068 27.941 34.794 28.283 ;
     RECT  2.304 27.679 2.862 28.291 ;
     RECT  3.924 28.021 6.858 28.291 ;
     RECT  2.304 28.291 6.858 28.409 ;
     RECT  31.068 28.283 31.086 28.409 ;
     RECT  7.815 28.049 8.478 28.417 ;
     RECT  31.824 28.283 34.794 28.481 ;
     RECT  7.668 28.417 8.478 28.561 ;
     RECT  30.852 28.561 30.87 28.679 ;
     RECT  31.932 28.481 34.794 28.679 ;
     RECT  35.928 27.941 35.946 28.699 ;
     RECT  30.78 28.687 30.798 28.859 ;
     RECT  35.928 28.699 35.982 29.179 ;
     RECT  35.352 29.179 35.982 29.219 ;
     RECT  7.02 28.561 8.478 29.371 ;
     RECT  6.84 29.371 8.622 29.461 ;
     RECT  2.304 28.409 6.066 29.497 ;
     RECT  6.84 29.461 8.874 29.497 ;
     RECT  2.304 29.497 8.874 29.669 ;
     RECT  8.856 29.669 8.874 29.767 ;
     RECT  10.515 26.627 10.797 29.803 ;
     RECT  35.928 29.219 35.982 29.851 ;
     RECT  8.856 29.767 9.27 29.867 ;
     RECT  31.932 28.679 34.254 29.911 ;
     RECT  10.515 29.803 10.854 29.939 ;
     RECT  31.068 29.911 34.254 30.073 ;
     RECT  30.852 30.073 34.254 30.109 ;
     RECT  30.78 30.109 34.758 30.209 ;
     RECT  30.852 30.209 34.758 30.443 ;
     RECT  2.304 29.669 8.097 30.569 ;
     RECT  31.068 30.443 34.758 30.569 ;
     RECT  0.216 30.475 0.234 30.605 ;
     RECT  2.304 30.569 5.886 30.811 ;
     RECT  31.356 30.569 34.758 30.811 ;
     RECT  2.268 30.811 5.886 30.839 ;
     RECT  31.356 30.811 34.794 30.839 ;
     RECT  2.268 30.839 5.814 30.875 ;
     RECT  32.076 30.839 34.794 30.946 ;
     RECT  32.076 30.946 34.83 31.147 ;
     RECT  35.928 29.851 36.018 31.147 ;
     RECT  6.768 30.569 8.097 31.189 ;
     RECT  32.076 31.147 36.018 31.217 ;
     RECT  32.076 31.217 34.83 31.289 ;
     RECT  6.768 31.189 8.586 31.379 ;
     RECT  2.304 30.875 5.814 31.649 ;
     RECT  32.076 31.289 34.794 31.657 ;
     RECT  3.852 31.649 5.814 31.919 ;
     RECT  6.84 31.379 8.19 31.919 ;
     RECT  3.924 31.919 5.814 32.071 ;
     RECT  35.928 31.217 36.018 32.141 ;
     RECT  6.948 31.919 8.19 32.161 ;
     RECT  3.924 32.071 5.886 32.341 ;
     RECT  30.78 31.693 30.798 32.341 ;
     RECT  31.68 31.657 34.794 32.341 ;
     RECT  6.948 32.161 8.262 32.369 ;
     RECT  30.78 32.341 34.794 32.443 ;
     RECT  35.928 32.141 35.946 32.443 ;
     RECT  30.78 32.443 35.946 32.459 ;
     RECT  6.948 32.369 8.19 32.495 ;
     RECT  9.324 32.269 9.342 32.495 ;
     RECT  3.924 32.341 5.994 32.683 ;
     RECT  2.304 31.649 3.006 32.809 ;
     RECT  3.924 32.683 6.39 32.809 ;
     RECT  7.344 32.495 8.19 32.999 ;
     RECT  32.115 32.459 35.946 33.067 ;
     RECT  2.304 32.809 6.39 33.241 ;
     RECT  7.344 32.999 8.097 33.241 ;
     RECT  32.115 33.067 35.982 33.277 ;
     RECT  30.78 32.459 30.798 33.385 ;
     RECT  2.304 33.241 8.097 33.403 ;
     RECT  10.515 29.939 10.797 33.421 ;
     RECT  31.572 33.277 35.982 33.449 ;
     RECT  30.78 33.385 30.834 33.547 ;
     RECT  31.572 33.449 34.254 33.547 ;
     RECT  2.268 33.403 8.097 33.575 ;
     RECT  10.515 33.421 10.818 33.611 ;
     RECT  30.78 33.547 34.254 33.809 ;
     RECT  35.352 33.449 35.982 33.923 ;
     RECT  30.78 33.809 30.87 33.989 ;
     RECT  2.304 33.575 8.097 34.051 ;
     RECT  31.896 33.809 34.254 34.219 ;
     RECT  2.304 34.051 8.586 34.355 ;
     RECT  6.732 34.355 8.586 34.393 ;
     RECT  6.732 34.393 8.622 34.493 ;
     RECT  2.304 34.355 5.922 34.555 ;
     RECT  6.732 34.493 6.894 34.619 ;
     RECT  9.396 34.501 9.414 34.619 ;
     RECT  6.768 34.619 6.894 34.691 ;
     RECT  30.852 33.989 30.87 34.727 ;
     RECT  35.928 33.923 35.982 34.799 ;
     RECT  31.896 34.219 34.794 34.843 ;
     RECT  35.928 34.799 35.946 34.843 ;
     RECT  2.268 34.555 5.922 34.997 ;
     RECT  7.815 34.493 8.622 34.997 ;
     RECT  31.896 34.843 35.946 34.997 ;
     RECT  31.896 34.997 34.434 35.041 ;
     RECT  31.824 35.041 34.434 35.267 ;
     RECT  31.824 35.267 34.29 35.275 ;
     RECT  6.804 34.691 6.894 35.311 ;
     RECT  30.78 34.897 30.798 35.339 ;
     RECT  2.304 34.997 5.922 35.429 ;
     RECT  6.804 35.311 7.002 35.429 ;
     RECT  9.432 35.311 9.45 35.429 ;
     RECT  6.84 35.429 7.002 35.437 ;
     RECT  7.815 34.997 8.097 35.437 ;
     RECT  31.608 35.275 34.29 35.473 ;
     RECT  30.852 35.473 34.29 35.699 ;
     RECT  32.04 35.699 34.254 35.843 ;
     RECT  3.924 35.429 5.922 35.851 ;
     RECT  6.84 35.437 8.097 35.851 ;
     RECT  2.304 35.429 3.006 35.969 ;
     RECT  10.515 33.611 10.797 35.977 ;
     RECT  10.515 35.977 10.818 36.077 ;
     RECT  2.304 35.969 2.697 36.139 ;
     RECT  6.84 35.851 8.586 36.239 ;
     RECT  35.352 34.997 35.946 36.239 ;
     RECT  7.815 36.239 8.586 36.247 ;
     RECT  30.852 35.699 30.87 36.247 ;
     RECT  3.924 35.851 6.066 36.283 ;
     RECT  6.84 36.239 6.93 36.283 ;
     RECT  35.928 36.239 35.946 36.331 ;
     RECT  30.78 36.247 30.87 36.347 ;
     RECT  3.924 36.283 6.93 36.391 ;
     RECT  7.815 36.247 8.622 36.391 ;
     RECT  7.815 36.391 9.234 36.419 ;
     RECT  35.928 36.331 35.982 36.475 ;
     RECT  30.852 36.347 30.87 36.481 ;
     RECT  32.04 35.843 34.218 36.481 ;
     RECT  2.268 36.139 2.697 36.545 ;
     RECT  3.744 36.391 6.93 36.557 ;
     RECT  30.852 36.481 34.218 36.581 ;
     RECT  9.216 36.419 9.234 36.779 ;
     RECT  31.86 36.581 34.218 36.779 ;
     RECT  32.115 36.779 34.218 36.811 ;
     RECT  3.96 36.557 6.93 36.815 ;
     RECT  2.304 36.545 2.697 36.859 ;
     RECT  30.852 36.581 30.87 36.923 ;
     RECT  0.252 36.859 0.27 36.989 ;
     RECT  4.068 36.815 6.93 37.049 ;
     RECT  4.14 37.049 6.93 37.085 ;
     RECT  2.304 36.859 3.222 37.133 ;
     RECT  32.115 36.811 34.758 37.147 ;
     RECT  35.928 36.475 36.018 37.147 ;
     RECT  4.284 37.085 6.93 37.291 ;
     RECT  7.815 36.419 8.406 37.291 ;
     RECT  4.284 37.291 8.406 37.561 ;
     RECT  0.216 37.597 0.234 37.661 ;
     RECT  4.284 37.561 8.658 37.733 ;
     RECT  9.684 37.561 9.702 37.741 ;
     RECT  10.515 36.077 10.797 37.741 ;
     RECT  2.304 37.133 3.186 37.771 ;
     RECT  32.115 37.147 36.018 37.805 ;
     RECT  4.284 37.733 5.397 37.831 ;
     RECT  30.78 37.093 30.798 37.831 ;
     RECT  32.115 37.805 34.794 37.831 ;
     RECT  6.192 37.733 8.658 37.859 ;
     RECT  9.684 37.741 10.797 37.859 ;
     RECT  10.515 37.859 10.797 37.867 ;
     RECT  30.78 37.831 34.794 37.967 ;
     RECT  35.892 37.805 36.018 37.967 ;
     RECT  6.192 37.859 8.19 38.003 ;
     RECT  2.268 37.771 3.186 38.011 ;
     RECT  10.515 37.867 10.854 38.039 ;
     RECT  30.852 37.967 34.794 38.039 ;
     RECT  31.572 38.039 34.794 38.129 ;
     RECT  2.268 38.011 3.222 38.165 ;
     RECT  31.932 38.129 34.794 38.285 ;
     RECT  2.304 38.165 3.222 38.371 ;
     RECT  3.96 37.831 5.397 38.371 ;
     RECT  7.056 38.003 8.19 38.399 ;
     RECT  31.932 38.285 34.254 38.507 ;
     RECT  35.892 37.967 35.946 38.587 ;
     RECT  7.092 38.399 8.19 38.641 ;
     RECT  9.18 38.245 9.594 38.641 ;
     RECT  7.092 38.641 9.594 38.741 ;
     RECT  6.192 38.003 6.21 38.779 ;
     RECT  31.968 38.507 34.254 38.939 ;
     RECT  2.304 38.371 5.397 39.091 ;
     RECT  6.192 38.779 6.282 39.091 ;
     RECT  7.815 38.741 9.594 39.119 ;
     RECT  2.304 39.091 6.282 39.181 ;
     RECT  2.304 39.181 6.93 39.209 ;
     RECT  7.815 39.119 8.982 39.389 ;
     RECT  6.66 39.209 6.93 39.479 ;
     RECT  6.84 39.479 6.93 39.487 ;
     RECT  7.815 39.389 8.55 39.487 ;
     RECT  6.84 39.487 8.55 39.533 ;
     RECT  6.84 39.533 6.858 39.551 ;
     RECT  30.888 39.451 30.906 39.551 ;
     RECT  2.304 39.209 5.67 39.623 ;
     RECT  7.596 39.533 8.55 39.659 ;
     RECT  7.596 39.659 8.442 39.749 ;
     RECT  32.004 38.939 34.254 39.749 ;
     RECT  32.076 39.749 34.254 39.821 ;
     RECT  32.112 39.821 34.254 39.883 ;
     RECT  35.352 38.587 35.946 39.883 ;
     RECT  30.78 39.793 30.798 39.893 ;
     RECT  0.54 39.865 0.558 39.917 ;
     RECT  32.112 39.883 35.946 40.013 ;
     RECT  3.42 39.623 5.67 40.019 ;
     RECT  9.504 39.901 9.522 40.199 ;
     RECT  32.112 40.013 34.254 40.325 ;
     RECT  2.304 39.623 2.697 40.363 ;
     RECT  35.352 40.013 35.946 40.363 ;
     RECT  3.888 40.019 5.67 40.441 ;
     RECT  7.596 39.749 8.226 40.531 ;
     RECT  7.416 40.531 8.226 40.567 ;
     RECT  7.416 40.567 8.298 40.603 ;
     RECT  30.852 40.567 30.87 40.639 ;
     RECT  32.112 40.325 34.218 40.675 ;
     RECT  35.352 40.363 36.018 40.703 ;
     RECT  3.888 40.441 5.922 40.801 ;
     RECT  2.304 40.363 2.862 40.837 ;
     RECT  3.888 40.801 6.246 40.945 ;
     RECT  7.308 40.603 8.298 40.945 ;
     RECT  2.304 40.837 2.934 41.179 ;
     RECT  35.352 40.703 35.982 41.207 ;
     RECT  2.304 41.179 2.97 41.215 ;
     RECT  3.888 40.945 8.298 41.215 ;
     RECT  32.004 40.675 34.218 41.215 ;
     RECT  2.304 41.215 8.298 41.341 ;
     RECT  2.304 41.341 8.586 41.405 ;
     RECT  30.78 40.639 30.87 41.477 ;
     RECT  31.968 41.215 34.218 41.485 ;
     RECT  0.216 41.419 0.234 41.549 ;
     RECT  2.376 41.405 8.586 41.549 ;
     RECT  35.352 41.207 35.946 41.639 ;
     RECT  31.932 41.485 34.218 41.719 ;
     RECT  6.588 41.549 8.586 41.747 ;
     RECT  31.932 41.719 34.254 41.755 ;
     RECT  9.684 41.179 9.702 41.791 ;
     RECT  6.588 41.747 8.262 41.819 ;
     RECT  30.78 41.477 30.798 41.909 ;
     RECT  7.668 41.819 8.262 41.945 ;
     RECT  0.252 41.851 0.27 41.981 ;
     RECT  31.716 41.755 34.254 41.989 ;
     RECT  6.588 41.819 6.93 42.017 ;
     RECT  9.432 41.791 9.702 42.061 ;
     RECT  6.732 42.017 6.93 42.077 ;
     RECT  2.376 41.549 5.85 42.139 ;
     RECT  7.668 41.945 8.097 42.179 ;
     RECT  9.36 42.061 9.702 42.359 ;
     RECT  6.84 42.077 6.93 42.449 ;
     RECT  35.928 41.639 35.946 42.475 ;
     RECT  9.684 42.359 9.702 42.521 ;
     RECT  35.928 42.475 35.982 42.529 ;
     RECT  31.716 41.989 34.794 42.601 ;
     RECT  31.392 42.601 34.794 42.719 ;
     RECT  7.815 42.179 8.097 42.727 ;
     RECT  2.304 42.139 5.85 42.799 ;
     RECT  31.608 42.719 34.758 42.845 ;
     RECT  7.815 42.727 8.586 43.141 ;
     RECT  7.815 43.141 8.658 43.147 ;
     RECT  2.304 42.799 5.922 43.169 ;
     RECT  6.696 42.871 6.714 43.181 ;
     RECT  7.56 43.147 8.658 43.267 ;
     RECT  35.928 42.529 36.018 43.291 ;
     RECT  7.488 43.267 8.658 43.303 ;
     RECT  29.415 20.957 29.697 43.303 ;
     RECT  7.488 43.303 8.73 43.411 ;
     RECT  7.488 43.411 8.838 43.439 ;
     RECT  29.415 43.303 30.222 43.439 ;
     RECT  7.815 43.439 8.838 43.529 ;
     RECT  35.892 43.291 36.018 43.609 ;
     RECT  35.352 43.609 36.018 43.661 ;
     RECT  31.608 42.845 34.326 43.765 ;
     RECT  0.252 43.771 0.27 43.901 ;
     RECT  6.228 43.411 6.318 43.951 ;
     RECT  35.928 43.661 36.018 43.979 ;
     RECT  6.228 43.951 6.354 44.011 ;
     RECT  6.228 44.011 6.498 44.185 ;
     RECT  4.176 43.169 5.397 44.221 ;
     RECT  6.228 44.185 6.606 44.221 ;
     RECT  2.304 43.169 3.402 44.299 ;
     RECT  4.176 44.221 6.606 44.299 ;
     RECT  2.304 44.299 6.606 44.347 ;
     RECT  2.304 44.347 6.858 44.375 ;
     RECT  0.216 44.251 0.234 44.381 ;
     RECT  31.608 43.765 34.83 44.477 ;
     RECT  30.78 44.077 30.798 44.491 ;
     RECT  31.608 44.477 34.29 44.491 ;
     RECT  35.928 43.979 35.982 44.581 ;
     RECT  30.78 44.491 34.29 44.609 ;
     RECT  30.78 44.609 30.87 44.753 ;
     RECT  4.536 44.375 6.858 44.761 ;
     RECT  7.815 43.529 8.097 44.761 ;
     RECT  31.896 44.609 34.29 44.879 ;
     RECT  4.536 44.761 8.097 44.951 ;
     RECT  30.78 44.753 30.798 44.987 ;
     RECT  8.928 44.995 8.946 45.031 ;
     RECT  2.304 44.375 3.654 45.115 ;
     RECT  4.536 44.951 6.462 45.115 ;
     RECT  8.928 45.031 9.018 45.149 ;
     RECT  2.304 45.115 6.462 45.257 ;
     RECT  8.928 45.149 8.946 45.329 ;
     RECT  7.272 44.951 8.097 45.391 ;
     RECT  7.272 45.391 8.658 45.419 ;
     RECT  2.304 45.257 6.246 45.689 ;
     RECT  32.076 44.879 34.29 45.697 ;
     RECT  31.932 45.697 34.29 45.841 ;
     RECT  35.352 44.581 35.982 45.869 ;
     RECT  31.356 45.841 34.29 45.995 ;
     RECT  31.932 45.995 34.29 46.027 ;
     RECT  35.352 45.869 35.946 46.027 ;
     RECT  7.416 45.419 8.658 46.111 ;
     RECT  7.416 46.111 9.126 46.139 ;
     RECT  2.304 45.689 3.078 46.471 ;
     RECT  3.852 45.689 6.246 46.471 ;
     RECT  7.416 46.139 8.097 46.543 ;
     RECT  30.924 46.507 30.942 46.543 ;
     RECT  30.852 46.543 30.942 46.607 ;
     RECT  31.932 46.027 35.946 46.679 ;
     RECT  35.784 46.679 35.946 46.699 ;
     RECT  21.315 20.957 21.597 46.747 ;
     RECT  29.415 43.439 29.697 46.747 ;
     RECT  30.852 46.607 30.87 46.747 ;
     RECT  2.304 46.471 6.246 46.777 ;
     RECT  35.784 46.699 35.982 46.841 ;
     RECT  35.928 46.841 35.982 46.843 ;
     RECT  14.832 46.747 14.85 46.877 ;
     RECT  21.315 46.747 21.69 46.877 ;
     RECT  22.824 46.747 22.842 46.877 ;
     RECT  29.415 46.747 29.79 46.877 ;
     RECT  31.932 46.679 34.794 46.885 ;
     RECT  9.108 46.139 9.126 46.921 ;
     RECT  2.304 46.777 6.318 47.039 ;
     RECT  9.108 46.921 9.198 47.039 ;
     RECT  2.304 47.039 3.294 47.075 ;
     RECT  7.164 46.543 8.097 47.119 ;
     RECT  30.78 46.747 30.87 47.219 ;
     RECT  35.928 46.843 36.018 47.309 ;
     RECT  8.82 47.281 8.946 47.579 ;
     RECT  4.14 47.039 6.318 47.615 ;
     RECT  7.128 47.119 8.097 47.623 ;
     RECT  31.86 46.885 34.794 47.695 ;
     RECT  4.392 47.615 6.318 47.731 ;
     RECT  7.128 47.623 8.406 47.731 ;
     RECT  10.515 38.039 10.797 47.731 ;
     RECT  35.928 47.309 35.982 47.759 ;
     RECT  31.608 47.695 34.794 47.803 ;
     RECT  35.928 47.759 35.946 47.803 ;
     RECT  2.304 47.075 3.222 47.848 ;
     RECT  4.392 47.731 8.406 47.849 ;
     RECT  10.515 47.731 10.854 47.849 ;
     RECT  31.608 47.803 35.946 47.849 ;
     RECT  2.304 47.848 3.51 47.885 ;
     RECT  4.392 47.849 8.262 47.891 ;
     RECT  30.78 47.219 30.798 48.163 ;
     RECT  31.608 47.849 34.794 48.163 ;
     RECT  9.288 48.001 9.45 48.271 ;
     RECT  9.288 48.271 9.486 48.299 ;
     RECT  30.78 48.163 34.794 48.365 ;
     RECT  30.78 48.365 34.362 48.389 ;
     RECT  4.392 47.891 8.097 48.433 ;
     RECT  0.252 48.331 0.27 48.461 ;
     RECT  9.36 48.299 9.486 48.569 ;
     RECT  35.928 47.849 35.946 48.619 ;
     RECT  30.816 48.389 34.362 48.767 ;
     RECT  10.515 47.849 10.797 48.811 ;
     RECT  9.36 48.569 9.378 48.929 ;
     RECT  35.352 48.619 35.946 48.929 ;
     RECT  10.515 48.811 10.854 49.001 ;
     RECT  2.304 47.885 2.862 49.009 ;
     RECT  4.248 48.433 8.097 49.009 ;
     RECT  2.304 49.009 8.097 49.351 ;
     RECT  30.816 48.767 34.29 49.469 ;
     RECT  2.304 49.351 8.406 49.541 ;
     RECT  30.816 49.469 34.254 49.541 ;
     RECT  2.304 49.541 8.097 49.739 ;
     RECT  4.14 49.739 7.074 49.775 ;
     RECT  30.816 49.541 34.218 49.891 ;
     RECT  35.928 48.929 35.946 49.915 ;
     RECT  30.78 49.891 34.218 50.009 ;
     RECT  35.352 49.915 35.946 50.107 ;
     RECT  4.14 49.775 7.002 50.117 ;
     RECT  30.78 50.009 30.798 50.117 ;
     RECT  2.304 49.739 3.33 50.251 ;
     RECT  31.788 50.009 34.218 50.359 ;
     RECT  31.788 50.359 34.326 50.395 ;
     RECT  35.352 50.107 35.982 50.395 ;
     RECT  7.815 49.739 8.097 50.521 ;
     RECT  7.815 50.521 8.478 50.621 ;
     RECT  10.515 49.001 10.797 50.629 ;
     RECT  10.515 50.629 10.854 50.729 ;
     RECT  2.268 50.251 3.33 50.731 ;
     RECT  4.14 50.117 6.93 50.731 ;
     RECT  31.788 50.395 35.982 50.863 ;
     RECT  9.396 50.521 9.414 50.927 ;
     RECT  31.5 50.863 35.982 50.935 ;
     RECT  31.464 50.935 35.982 51.097 ;
     RECT  31.392 51.097 35.982 51.101 ;
     RECT  2.268 50.731 6.93 51.125 ;
     RECT  31.392 51.101 34.83 51.169 ;
     RECT  35.928 51.101 35.982 51.197 ;
     RECT  2.304 51.125 6.93 51.259 ;
     RECT  7.815 50.621 8.097 51.259 ;
     RECT  2.304 51.259 8.097 51.293 ;
     RECT  31.356 51.169 34.83 51.467 ;
     RECT  2.304 51.293 6.246 51.629 ;
     RECT  31.356 51.467 34.254 51.871 ;
     RECT  35.928 51.197 35.946 51.883 ;
     RECT  3.528 51.629 6.246 51.899 ;
     RECT  3.816 51.899 6.246 52.051 ;
     RECT  30.78 51.871 34.254 52.079 ;
     RECT  7.164 51.293 8.097 52.249 ;
     RECT  3.816 52.051 6.39 52.321 ;
     RECT  7.164 52.249 8.586 52.321 ;
     RECT  30.78 52.079 30.87 52.349 ;
     RECT  3.816 52.321 8.586 52.439 ;
     RECT  30.78 52.349 30.798 52.439 ;
     RECT  2.304 51.629 2.697 52.507 ;
     RECT  2.304 52.507 2.754 52.681 ;
     RECT  3.816 52.439 8.298 52.745 ;
     RECT  2.304 52.681 2.934 52.861 ;
     RECT  3.816 52.745 5.397 52.861 ;
     RECT  9.54 52.591 9.63 52.979 ;
     RECT  35.352 51.883 35.946 52.987 ;
     RECT  32.076 52.079 34.254 53.023 ;
     RECT  35.352 52.987 35.982 53.123 ;
     RECT  31.788 53.023 34.254 53.293 ;
     RECT  6.12 52.745 8.298 53.321 ;
     RECT  6.12 53.321 8.097 53.393 ;
     RECT  30.78 53.257 30.798 53.429 ;
     RECT  2.304 52.861 5.397 53.515 ;
     RECT  6.12 53.393 6.534 53.515 ;
     RECT  31.716 53.293 34.326 53.515 ;
     RECT  9.144 53.491 9.162 53.699 ;
     RECT  31.716 53.515 34.83 53.833 ;
     RECT  31.176 53.833 34.83 54.059 ;
     RECT  0.252 53.995 0.27 54.125 ;
     RECT  9.432 53.869 9.486 54.131 ;
     RECT  31.536 54.059 34.83 54.131 ;
     RECT  35.928 53.123 35.982 54.283 ;
     RECT  2.304 53.515 6.534 54.337 ;
     RECT  7.38 53.393 8.097 54.337 ;
     RECT  2.304 54.337 8.097 54.365 ;
     RECT  3.996 54.365 8.097 54.409 ;
     RECT  35.352 54.283 35.982 54.509 ;
     RECT  2.304 54.365 2.862 54.607 ;
     RECT  2.268 54.607 2.862 54.653 ;
     RECT  3.996 54.409 8.37 54.658 ;
     RECT  7.056 54.658 8.37 54.679 ;
     RECT  3.996 54.658 6.174 54.779 ;
     RECT  3.996 54.779 6.102 54.869 ;
     RECT  7.056 54.679 9.054 55.013 ;
     RECT  31.896 54.131 34.29 55.139 ;
     RECT  31.932 55.139 34.29 55.211 ;
     RECT  2.304 54.653 2.862 55.255 ;
     RECT  3.996 54.869 5.886 55.255 ;
     RECT  2.304 55.255 5.886 55.409 ;
     RECT  35.352 54.509 35.946 55.409 ;
     RECT  35.928 55.409 35.946 55.489 ;
     RECT  30.78 54.913 30.798 55.525 ;
     RECT  32.115 55.211 34.29 55.525 ;
     RECT  2.304 55.409 2.697 55.579 ;
     RECT  7.056 55.013 8.514 55.679 ;
     RECT  30.78 55.525 30.87 55.787 ;
     RECT  3.672 55.409 5.886 55.831 ;
     RECT  7.74 55.679 8.514 55.831 ;
     RECT  35.928 55.489 35.982 55.915 ;
     RECT  3.672 55.831 5.922 55.921 ;
     RECT  2.268 55.579 2.697 55.985 ;
     RECT  3.672 55.921 6.03 56.065 ;
     RECT  7.74 55.831 8.622 56.093 ;
     RECT  10.515 50.729 10.797 56.101 ;
     RECT  32.115 55.525 34.326 56.101 ;
     RECT  35.928 55.915 36.018 56.107 ;
     RECT  10.515 56.101 10.854 56.219 ;
     RECT  3.672 56.065 6.318 56.255 ;
     RECT  2.304 55.985 2.697 56.299 ;
     RECT  3.672 56.255 5.397 56.299 ;
     RECT  6.156 56.255 6.318 56.371 ;
     RECT  35.928 56.107 36.054 56.395 ;
     RECT  30.78 55.787 30.798 56.399 ;
     RECT  32.004 56.101 34.326 56.461 ;
     RECT  6.156 56.371 6.462 56.569 ;
     RECT  35.928 56.395 36.09 56.597 ;
     RECT  31.644 56.461 34.326 56.641 ;
     RECT  2.304 56.299 5.397 56.731 ;
     RECT  31.176 56.641 34.326 56.759 ;
     RECT  2.268 56.731 5.397 56.831 ;
     RECT  31.608 56.759 34.326 56.875 ;
     RECT  35.928 56.597 36.054 56.939 ;
     RECT  3.636 56.831 5.397 57.001 ;
     RECT  6.156 56.569 6.966 57.001 ;
     RECT  7.74 56.093 8.097 57.109 ;
     RECT  3.636 57.001 6.966 57.181 ;
     RECT  7.74 57.109 8.658 57.181 ;
     RECT  31.608 56.875 34.794 57.209 ;
     RECT  35.928 56.939 35.946 57.547 ;
     RECT  2.268 56.831 2.862 57.677 ;
     RECT  2.304 57.677 2.862 57.685 ;
     RECT  3.636 57.181 8.658 57.685 ;
     RECT  31.608 57.209 34.326 57.839 ;
     RECT  2.304 57.685 8.658 57.911 ;
     RECT  30.78 57.307 30.798 57.919 ;
     RECT  31.608 57.839 34.254 57.919 ;
     RECT  29.415 46.877 29.697 57.991 ;
     RECT  30.78 57.919 34.254 57.991 ;
     RECT  7.815 57.911 8.658 58.109 ;
     RECT  0.252 58.027 0.27 58.117 ;
     RECT  0.252 58.117 0.342 58.157 ;
     RECT  0.324 58.157 0.342 58.205 ;
     RECT  29.415 57.991 34.254 58.379 ;
     RECT  30.78 58.379 30.798 58.487 ;
     RECT  7.815 58.109 8.586 58.649 ;
     RECT  2.304 57.911 7.074 58.693 ;
     RECT  7.815 58.649 8.37 58.693 ;
     RECT  2.304 58.693 8.37 58.829 ;
     RECT  31.788 58.379 34.254 58.843 ;
     RECT  35.352 57.547 35.946 58.843 ;
     RECT  2.304 58.829 7.074 58.973 ;
     RECT  31.788 58.843 35.946 59.027 ;
     RECT  31.788 59.027 34.83 59.063 ;
     RECT  31.788 59.063 34.758 59.099 ;
     RECT  35.892 59.027 35.946 59.179 ;
     RECT  7.815 58.829 8.37 59.189 ;
     RECT  35.892 59.179 35.982 59.189 ;
     RECT  35.928 59.189 35.982 59.323 ;
     RECT  31.788 59.099 34.254 59.467 ;
     RECT  31.572 59.467 34.254 59.729 ;
     RECT  9.216 59.611 9.234 59.737 ;
     RECT  10.515 56.219 10.797 59.737 ;
     RECT  9.216 59.737 9.27 59.738 ;
     RECT  2.304 58.973 6.93 59.755 ;
     RECT  7.815 59.189 8.298 59.755 ;
     RECT  9.252 59.738 9.27 59.837 ;
     RECT  10.515 59.737 10.926 59.837 ;
     RECT  31.932 59.729 34.254 59.995 ;
     RECT  31.932 59.995 34.794 59.999 ;
     RECT  35.928 59.323 36.018 60.143 ;
     RECT  0.396 60.139 0.414 60.283 ;
     RECT  32.115 59.999 34.794 60.283 ;
     RECT  0.216 60.283 0.414 60.317 ;
     RECT  32.115 60.283 35.37 60.341 ;
     RECT  2.304 59.755 8.298 60.377 ;
     RECT  0.216 60.317 0.234 60.413 ;
     RECT  3.852 60.377 8.298 60.419 ;
     RECT  5.115 60.419 8.298 60.421 ;
     RECT  3.852 60.419 4.194 60.539 ;
     RECT  3.852 60.539 4.05 60.701 ;
     RECT  2.304 60.377 3.078 60.952 ;
     RECT  35.352 60.341 35.37 60.955 ;
     RECT  35.352 60.955 35.946 61.099 ;
     RECT  2.268 60.952 3.078 61.195 ;
     RECT  3.852 60.701 3.978 61.195 ;
     RECT  32.115 60.341 34.254 61.195 ;
     RECT  5.115 60.421 8.442 61.231 ;
     RECT  30.78 61.123 30.798 61.357 ;
     RECT  2.268 61.195 3.978 61.501 ;
     RECT  30.78 61.357 30.87 61.501 ;
     RECT  32.115 61.195 34.326 61.579 ;
     RECT  35.352 61.099 35.982 61.579 ;
     RECT  2.268 61.501 4.374 61.655 ;
     RECT  30.78 61.501 31.374 61.691 ;
     RECT  5.115 61.231 8.514 61.757 ;
     RECT  32.115 61.579 35.982 61.763 ;
     RECT  21.315 46.877 21.597 61.867 ;
     RECT  29.415 58.379 29.697 61.867 ;
     RECT  32.115 61.763 35.37 61.897 ;
     RECT  14.832 61.867 14.85 61.997 ;
     RECT  21.315 61.867 21.69 61.997 ;
     RECT  22.824 61.867 22.842 61.997 ;
     RECT  29.415 61.867 29.79 61.997 ;
     RECT  30.78 61.691 30.798 61.997 ;
     RECT  7.164 61.757 8.514 62.069 ;
     RECT  0.252 61.291 0.27 62.093 ;
     RECT  2.304 61.655 4.374 62.131 ;
     RECT  5.115 61.757 6.39 62.131 ;
     RECT  31.788 61.897 35.37 62.285 ;
     RECT  9.36 61.771 9.378 62.311 ;
     RECT  7.164 62.069 8.406 62.429 ;
     RECT  31.788 62.285 34.794 62.509 ;
     RECT  2.304 62.131 6.39 62.536 ;
     RECT  7.164 62.429 8.37 62.536 ;
     RECT  2.304 62.536 8.37 62.572 ;
     RECT  9.36 62.311 9.486 62.581 ;
     RECT  2.268 62.572 8.37 62.765 ;
     RECT  31.356 62.509 34.794 62.815 ;
     RECT  9.36 62.581 9.702 62.851 ;
     RECT  3.636 62.765 8.37 62.861 ;
     RECT  3.636 62.861 8.097 62.879 ;
     RECT  9.288 62.851 9.702 62.879 ;
     RECT  9.288 62.879 9.306 62.969 ;
     RECT  35.964 62.587 35.982 63.067 ;
     RECT  30.78 62.815 34.794 63.149 ;
     RECT  35.928 63.067 35.982 63.149 ;
     RECT  2.268 62.765 2.862 63.545 ;
     RECT  2.304 63.545 2.862 63.595 ;
     RECT  3.636 62.879 6.246 63.595 ;
     RECT  30.78 63.149 30.798 63.617 ;
     RECT  31.932 63.149 34.794 63.617 ;
     RECT  2.304 63.595 6.246 63.661 ;
     RECT  7.056 62.879 8.097 63.661 ;
     RECT  35.928 63.149 35.946 63.691 ;
     RECT  0.216 63.691 0.234 63.821 ;
     RECT  35.352 63.691 35.946 64.061 ;
     RECT  31.932 63.617 34.254 64.093 ;
     RECT  8.856 64.201 8.946 64.319 ;
     RECT  31.536 64.093 34.254 64.319 ;
     RECT  35.928 64.061 35.946 64.363 ;
     RECT  8.928 64.319 8.946 64.391 ;
     RECT  32.115 64.319 34.254 64.633 ;
     RECT  2.304 63.661 8.097 64.733 ;
     RECT  2.304 64.733 2.934 64.843 ;
     RECT  4.068 64.733 8.097 64.859 ;
     RECT  30.96 64.327 31.374 64.859 ;
     RECT  4.068 64.859 6.102 64.895 ;
     RECT  2.268 64.843 2.934 65.003 ;
     RECT  35.928 64.363 35.982 65.179 ;
     RECT  10.515 59.837 10.797 65.245 ;
     RECT  6.948 64.859 8.097 65.371 ;
     RECT  6.948 65.371 8.154 65.399 ;
     RECT  2.304 65.003 2.934 65.467 ;
     RECT  35.928 65.179 36.018 65.467 ;
     RECT  10.515 65.245 10.818 65.471 ;
     RECT  32.115 64.633 34.29 65.479 ;
     RECT  2.304 65.467 3.294 65.515 ;
     RECT  4.068 64.895 5.994 65.515 ;
     RECT  30.78 65.443 30.798 65.543 ;
     RECT  35.928 65.467 36.054 65.659 ;
     RECT  2.304 65.515 5.994 65.705 ;
     RECT  31.932 65.479 34.29 65.785 ;
     RECT  4.104 65.705 5.994 65.821 ;
     RECT  35.352 65.659 36.054 65.849 ;
     RECT  4.104 65.821 6.03 65.911 ;
     RECT  31.644 65.785 34.326 65.939 ;
     RECT  35.352 65.849 36.018 66.047 ;
     RECT  35.928 66.047 36.018 66.173 ;
     RECT  8.892 66.091 8.91 66.209 ;
     RECT  31.644 65.939 34.218 66.253 ;
     RECT  35.928 66.173 35.982 66.281 ;
     RECT  4.104 65.911 6.246 66.427 ;
     RECT  7.056 65.399 8.154 66.427 ;
     RECT  31.356 66.253 34.218 66.451 ;
     RECT  2.304 65.705 3.366 66.631 ;
     RECT  4.104 66.427 8.154 66.631 ;
     RECT  30.852 66.451 34.218 66.901 ;
     RECT  30.78 66.901 34.218 66.955 ;
     RECT  9.18 66.901 9.27 67.127 ;
     RECT  30.78 66.955 34.254 67.171 ;
     RECT  30.78 67.171 34.362 67.243 ;
     RECT  30.78 67.243 34.794 67.289 ;
     RECT  9.288 67.171 9.306 67.325 ;
     RECT  2.304 66.631 8.154 67.369 ;
     RECT  2.304 67.369 8.262 67.432 ;
     RECT  2.268 67.432 8.262 67.441 ;
     RECT  2.268 67.441 8.478 67.559 ;
     RECT  2.268 67.559 8.298 67.595 ;
     RECT  9.648 67.441 9.738 67.667 ;
     RECT  30.78 67.289 34.758 67.667 ;
     RECT  0.216 67.675 0.234 67.805 ;
     RECT  2.304 67.595 8.298 67.829 ;
     RECT  30.852 67.667 34.758 67.829 ;
     RECT  35.928 66.281 35.946 67.909 ;
     RECT  35.928 67.909 35.982 67.949 ;
     RECT  35.928 67.949 35.946 68.009 ;
     RECT  32.076 67.829 34.758 68.059 ;
     RECT  9.648 67.667 9.666 68.099 ;
     RECT  30.852 67.829 30.87 68.243 ;
     RECT  10.515 65.471 10.797 68.251 ;
     RECT  10.515 68.251 10.926 68.369 ;
     RECT  32.076 68.059 34.794 68.395 ;
     RECT  9.144 68.251 9.198 68.549 ;
     RECT  2.304 67.829 6.282 68.611 ;
     RECT  30.78 68.683 30.798 68.783 ;
     RECT  7.128 67.829 8.298 68.791 ;
     RECT  32.076 68.395 35.37 68.819 ;
     RECT  2.304 68.611 6.354 68.909 ;
     RECT  32.076 68.819 34.794 68.909 ;
     RECT  32.076 68.909 34.758 69.025 ;
     RECT  2.304 68.909 4.374 69.061 ;
     RECT  5.115 68.909 6.354 69.061 ;
     RECT  7.128 68.791 8.586 69.061 ;
     RECT  9.72 69.061 9.738 69.179 ;
     RECT  35.928 68.875 35.946 69.211 ;
     RECT  5.115 69.061 8.586 69.331 ;
     RECT  5.115 69.331 8.73 69.449 ;
     RECT  0.216 69.355 0.234 69.485 ;
     RECT  6.912 69.449 8.097 69.485 ;
     RECT  35.928 69.211 35.982 69.629 ;
     RECT  32.004 69.025 34.758 69.691 ;
     RECT  35.928 69.629 35.946 69.691 ;
     RECT  5.115 69.449 6.138 69.719 ;
     RECT  2.268 69.061 4.374 69.727 ;
     RECT  5.115 69.719 5.886 69.727 ;
     RECT  2.268 69.727 5.886 69.755 ;
     RECT  32.004 69.691 35.946 70.105 ;
     RECT  6.912 69.485 6.93 70.169 ;
     RECT  9.108 69.871 9.126 70.259 ;
     RECT  31.572 70.105 35.946 70.267 ;
     RECT  31.14 70.267 35.946 70.303 ;
     RECT  7.815 69.485 8.097 70.339 ;
     RECT  30.78 70.303 35.946 70.367 ;
     RECT  9.216 70.303 9.234 70.439 ;
     RECT  30.78 70.367 34.758 70.529 ;
     RECT  2.304 69.755 5.886 70.555 ;
     RECT  30.78 70.529 30.798 70.637 ;
     RECT  7.776 70.339 8.097 70.645 ;
     RECT  2.304 70.555 5.994 70.681 ;
     RECT  7.632 70.645 8.097 70.795 ;
     RECT  7.632 70.795 8.19 70.835 ;
     RECT  2.304 70.681 6.318 70.871 ;
     RECT  9.432 70.681 9.45 70.915 ;
     RECT  7.632 70.835 8.097 70.951 ;
     RECT  32.004 70.529 34.758 70.979 ;
     RECT  32.004 70.979 34.254 71.021 ;
     RECT  32.004 71.021 34.218 71.105 ;
     RECT  32.076 71.105 34.218 71.141 ;
     RECT  7.02 70.951 8.097 71.177 ;
     RECT  35.856 70.367 35.946 71.323 ;
     RECT  9.432 70.915 9.486 71.483 ;
     RECT  10.515 68.369 10.797 71.491 ;
     RECT  8.82 71.491 8.838 71.609 ;
     RECT  10.515 71.491 10.854 71.609 ;
     RECT  35.352 71.323 35.946 71.659 ;
     RECT  2.304 70.871 6.066 71.725 ;
     RECT  2.304 71.725 6.138 71.761 ;
     RECT  30.78 71.653 30.798 71.789 ;
     RECT  32.115 71.141 34.218 71.803 ;
     RECT  35.352 71.659 35.982 71.803 ;
     RECT  2.304 71.761 6.282 71.879 ;
     RECT  32.115 71.803 35.982 71.933 ;
     RECT  35.352 71.933 35.982 71.947 ;
     RECT  7.272 71.177 8.097 71.995 ;
     RECT  7.272 71.995 8.406 72.149 ;
     RECT  7.272 72.149 8.097 72.301 ;
     RECT  2.304 71.879 5.706 72.527 ;
     RECT  30.852 71.923 30.87 72.535 ;
     RECT  32.115 71.933 34.29 72.535 ;
     RECT  9.684 72.301 9.702 72.599 ;
     RECT  4.32 72.527 5.706 72.661 ;
     RECT  30.852 72.535 34.29 72.733 ;
     RECT  4.32 72.661 5.778 72.805 ;
     RECT  6.84 72.301 8.097 72.805 ;
     RECT  4.32 72.805 5.886 72.841 ;
     RECT  6.624 72.805 8.097 72.841 ;
     RECT  4.32 72.841 8.097 72.845 ;
     RECT  30.78 72.733 34.29 72.955 ;
     RECT  35.352 71.947 36.018 72.955 ;
     RECT  2.304 72.527 3.546 73.031 ;
     RECT  7.236 72.845 8.097 73.111 ;
     RECT  4.32 72.845 6.246 73.381 ;
     RECT  0.216 73.339 0.234 73.469 ;
     RECT  30.78 72.955 36.018 73.469 ;
     RECT  35.928 73.469 36.018 73.607 ;
     RECT  36 73.607 36.018 73.643 ;
     RECT  30.78 73.469 34.83 73.769 ;
     RECT  2.304 73.031 3.006 73.805 ;
     RECT  3.996 73.381 6.246 73.849 ;
     RECT  7.236 73.111 8.262 73.849 ;
     RECT  30.78 73.769 30.906 73.877 ;
     RECT  2.304 73.805 2.862 73.915 ;
     RECT  3.78 73.849 8.262 73.921 ;
     RECT  3.6 73.921 8.262 73.949 ;
     RECT  4.428 73.949 8.262 74.011 ;
     RECT  4.428 74.011 8.586 74.309 ;
     RECT  31.896 73.769 34.83 74.309 ;
     RECT  10.515 71.609 10.797 74.389 ;
     RECT  10.515 74.389 10.818 74.489 ;
     RECT  31.932 74.309 34.83 74.539 ;
     RECT  35.928 74.395 35.946 74.539 ;
     RECT  2.268 73.915 2.862 74.573 ;
     RECT  4.428 74.309 8.154 74.579 ;
     RECT  30.852 73.877 30.906 74.651 ;
     RECT  2.304 74.573 2.862 74.731 ;
     RECT  3.6 73.949 3.654 74.731 ;
     RECT  9.36 74.425 9.378 74.731 ;
     RECT  31.932 74.539 35.946 74.849 ;
     RECT  30.852 74.651 30.87 74.929 ;
     RECT  32.115 74.849 35.946 74.929 ;
     RECT  30.78 74.929 30.87 74.957 ;
     RECT  4.428 74.579 5.67 74.965 ;
     RECT  9.288 74.731 9.378 74.993 ;
     RECT  2.304 74.731 3.654 75.001 ;
     RECT  4.392 74.965 5.67 75.001 ;
     RECT  9.36 74.993 9.378 75.029 ;
     RECT  0.216 75.019 0.234 75.149 ;
     RECT  6.516 74.579 8.154 75.199 ;
     RECT  2.304 75.001 5.67 75.541 ;
     RECT  6.516 75.199 8.622 75.541 ;
     RECT  10.515 74.489 10.797 75.667 ;
     RECT  32.115 74.929 35.982 75.667 ;
     RECT  31.608 75.667 35.982 75.691 ;
     RECT  10.515 75.667 10.926 75.803 ;
     RECT  2.304 75.541 8.622 75.821 ;
     RECT  4.536 75.821 8.622 75.839 ;
     RECT  4.536 75.839 8.097 76.073 ;
     RECT  2.304 75.821 3.726 76.171 ;
     RECT  31.608 75.691 36.018 76.271 ;
     RECT  31.608 76.271 35.982 76.307 ;
     RECT  31.608 76.307 34.794 76.379 ;
     RECT  8.892 76.549 8.91 76.585 ;
     RECT  8.892 76.585 8.946 76.621 ;
     RECT  2.268 76.171 3.726 76.819 ;
     RECT  4.536 76.073 5.85 76.819 ;
     RECT  2.268 76.819 5.85 76.939 ;
     RECT  6.624 76.073 8.097 76.939 ;
     RECT  8.892 76.621 8.982 77.053 ;
     RECT  2.268 76.939 8.097 77.081 ;
     RECT  2.268 77.081 3.006 77.117 ;
     RECT  2.304 77.117 3.006 77.315 ;
     RECT  30.78 74.957 30.798 77.387 ;
     RECT  8.892 77.053 9.162 77.549 ;
     RECT  31.68 76.379 34.794 77.557 ;
     RECT  3.744 77.081 8.097 77.585 ;
     RECT  9.144 77.549 9.162 77.621 ;
     RECT  30.96 77.557 34.794 77.693 ;
     RECT  35.928 76.307 35.982 77.729 ;
     RECT  35.928 77.729 35.946 77.803 ;
     RECT  30.96 77.693 34.254 77.819 ;
     RECT  3.744 77.585 6.642 77.899 ;
     RECT  3.636 77.899 6.642 78.061 ;
     RECT  2.304 77.315 2.697 78.241 ;
     RECT  3.42 78.061 6.642 78.241 ;
     RECT  7.416 77.585 8.097 78.241 ;
     RECT  2.304 78.241 6.642 78.431 ;
     RECT  10.515 75.803 10.797 78.439 ;
     RECT  31.248 77.819 34.254 78.467 ;
     RECT  10.515 78.439 10.926 78.511 ;
     RECT  4.104 78.431 6.642 78.601 ;
     RECT  7.416 78.241 8.118 78.601 ;
     RECT  10.515 78.511 10.998 78.629 ;
     RECT  2.304 78.431 3.33 78.665 ;
     RECT  2.304 78.665 3.258 78.763 ;
     RECT  35.352 77.803 35.946 78.763 ;
     RECT  4.104 78.601 8.118 78.773 ;
     RECT  9.684 78.781 9.702 78.871 ;
     RECT  9.072 78.871 9.702 78.899 ;
     RECT  35.352 78.763 35.982 78.907 ;
     RECT  31.248 78.467 34.218 78.943 ;
     RECT  9.072 78.899 9.09 78.971 ;
     RECT  2.268 78.763 3.258 79.007 ;
     RECT  7.272 78.773 8.118 79.051 ;
     RECT  30.78 78.943 34.218 79.169 ;
     RECT  4.104 78.773 6.318 79.205 ;
     RECT  4.104 79.205 6.21 79.241 ;
     RECT  31.896 79.169 34.218 79.435 ;
     RECT  35.352 78.907 36.018 79.435 ;
     RECT  4.104 79.241 6.03 79.475 ;
     RECT  30.78 79.169 30.87 79.583 ;
     RECT  2.304 79.007 3.258 79.591 ;
     RECT  31.896 79.435 36.018 79.619 ;
     RECT  31.896 79.619 35.982 79.781 ;
     RECT  7.272 79.051 8.37 79.889 ;
     RECT  2.304 79.591 3.654 79.915 ;
     RECT  7.272 79.889 8.298 79.979 ;
     RECT  0.54 79.753 0.558 80.237 ;
     RECT  7.272 79.979 8.226 80.249 ;
     RECT  31.896 79.781 34.254 80.257 ;
     RECT  7.272 80.249 8.097 80.329 ;
     RECT  4.428 79.475 6.03 80.395 ;
     RECT  2.268 79.915 3.654 80.401 ;
     RECT  4.428 80.395 6.282 80.401 ;
     RECT  7.092 80.329 8.097 80.401 ;
     RECT  10.515 78.629 10.797 80.401 ;
     RECT  10.515 80.401 10.818 80.555 ;
     RECT  30.78 79.583 30.798 80.627 ;
     RECT  31.68 80.257 34.254 80.635 ;
     RECT  9.288 80.671 9.378 80.789 ;
     RECT  0.252 80.731 0.27 80.861 ;
     RECT  31.68 80.635 34.326 80.869 ;
     RECT  9.288 80.789 9.306 80.969 ;
     RECT  31.68 80.869 34.434 81.059 ;
     RECT  2.268 80.401 8.097 81.167 ;
     RECT  31.932 81.059 34.434 81.643 ;
     RECT  35.352 79.781 35.982 81.643 ;
     RECT  31.932 81.643 35.982 81.725 ;
     RECT  30.852 81.643 30.87 81.743 ;
     RECT  9.252 81.751 9.342 81.869 ;
     RECT  35.352 81.725 35.982 81.869 ;
     RECT  2.304 81.167 8.097 82.012 ;
     RECT  2.268 82.012 8.097 82.021 ;
     RECT  10.515 80.555 10.797 82.111 ;
     RECT  2.268 82.021 8.154 82.175 ;
     RECT  10.515 82.111 10.854 82.211 ;
     RECT  2.304 82.175 8.154 82.291 ;
     RECT  9.252 81.869 9.27 82.291 ;
     RECT  2.304 82.291 9.27 82.409 ;
     RECT  2.304 82.409 8.118 82.481 ;
     RECT  35.928 81.869 35.982 82.507 ;
     RECT  31.932 81.725 34.434 82.525 ;
     RECT  31.824 82.525 34.434 82.651 ;
     RECT  31.824 82.651 34.794 82.679 ;
     RECT  32.076 82.679 34.794 82.795 ;
     RECT  30.78 82.417 30.798 83.057 ;
     RECT  35.928 82.507 36.018 83.057 ;
     RECT  0.252 83.035 0.27 83.165 ;
     RECT  30.852 83.227 30.87 83.327 ;
     RECT  32.076 82.795 34.83 83.327 ;
     RECT  2.304 82.481 6.93 83.605 ;
     RECT  7.815 82.481 8.118 83.605 ;
     RECT  2.304 83.605 8.118 83.731 ;
     RECT  2.304 83.731 8.298 83.795 ;
     RECT  34.704 83.327 34.83 83.803 ;
     RECT  35.928 83.057 35.946 83.803 ;
     RECT  2.304 83.795 3.006 83.867 ;
     RECT  34.704 83.803 35.946 83.981 ;
     RECT  32.076 83.327 33.966 84.073 ;
     RECT  3.744 83.795 8.298 84.137 ;
     RECT  32.004 84.073 33.966 84.181 ;
     RECT  7.74 84.137 8.298 84.209 ;
     RECT  3.744 84.137 6.966 84.335 ;
     RECT  32.004 84.181 34.254 84.371 ;
     RECT  35.352 83.981 35.946 84.427 ;
     RECT  9.144 84.343 9.162 84.479 ;
     RECT  30.78 84.109 30.798 84.541 ;
     RECT  3.744 84.335 6.858 84.649 ;
     RECT  10.515 82.211 10.797 84.649 ;
     RECT  2.304 83.867 2.862 84.721 ;
     RECT  3.672 84.649 6.858 84.721 ;
     RECT  2.304 84.721 6.858 84.748 ;
     RECT  10.515 84.649 10.926 84.749 ;
     RECT  30.78 84.541 30.906 84.749 ;
     RECT  7.815 84.209 8.298 84.847 ;
     RECT  2.268 84.748 6.858 84.875 ;
     RECT  10.515 84.749 10.854 84.875 ;
     RECT  7.815 84.847 8.406 84.893 ;
     RECT  32.04 84.371 34.254 85.099 ;
     RECT  35.352 84.427 35.982 85.099 ;
     RECT  32.04 85.099 35.982 85.109 ;
     RECT  2.304 84.875 6.858 85.181 ;
     RECT  30.852 84.749 30.906 85.351 ;
     RECT  32.04 85.109 34.794 85.351 ;
     RECT  30.852 85.351 34.794 85.379 ;
     RECT  35.928 85.109 35.982 85.423 ;
     RECT  30.852 85.379 31.374 85.523 ;
     RECT  9.54 84.883 9.558 85.531 ;
     RECT  30.852 85.523 30.942 85.531 ;
     RECT  6.444 85.181 6.858 85.579 ;
     RECT  7.815 84.893 8.097 85.579 ;
     RECT  35.928 85.423 36.018 85.613 ;
     RECT  9.252 85.531 9.558 85.649 ;
     RECT  30.78 85.531 30.942 85.757 ;
     RECT  32.115 85.379 34.794 85.915 ;
     RECT  6.444 85.579 8.097 86.011 ;
     RECT  30.78 85.757 30.87 86.027 ;
     RECT  6.336 86.011 8.097 86.045 ;
     RECT  6.336 86.045 6.354 86.063 ;
     RECT  2.304 85.181 5.598 86.161 ;
     RECT  7.128 86.045 8.097 86.161 ;
     RECT  32.115 85.915 34.83 86.269 ;
     RECT  32.004 86.269 34.83 86.305 ;
     RECT  31.86 86.305 34.83 86.467 ;
     RECT  0.252 86.395 0.27 86.525 ;
     RECT  30.852 86.027 30.87 86.603 ;
     RECT  31.68 86.467 34.83 86.639 ;
     RECT  7.128 86.161 8.442 86.669 ;
     RECT  31.788 86.639 34.83 86.683 ;
     RECT  35.928 85.613 35.982 86.683 ;
     RECT  7.596 86.669 8.442 86.809 ;
     RECT  2.304 86.161 5.814 86.822 ;
     RECT  6.66 86.845 6.678 86.881 ;
     RECT  31.788 86.683 35.982 86.909 ;
     RECT  31.788 86.909 34.29 86.999 ;
     RECT  30.78 87.043 30.798 87.143 ;
     RECT  6.588 86.881 6.678 87.421 ;
     RECT  7.596 86.809 8.514 87.421 ;
     RECT  2.304 86.822 5.85 87.499 ;
     RECT  31.932 86.999 34.29 87.539 ;
     RECT  35.352 86.909 35.982 87.611 ;
     RECT  2.268 87.499 5.85 87.691 ;
     RECT  6.588 87.421 8.514 87.691 ;
     RECT  0.216 87.595 0.234 87.725 ;
     RECT  2.268 87.691 8.586 87.725 ;
     RECT  7.272 87.725 8.586 87.809 ;
     RECT  32.004 87.539 34.29 87.835 ;
     RECT  35.352 87.611 35.946 87.835 ;
     RECT  2.268 87.725 6.426 87.845 ;
     RECT  32.004 87.835 35.946 88.429 ;
     RECT  32.004 88.429 36.018 88.541 ;
     RECT  2.304 87.845 2.862 88.591 ;
     RECT  3.6 87.845 6.426 88.591 ;
     RECT  10.515 84.875 10.797 88.663 ;
     RECT  36 88.541 36.018 88.685 ;
     RECT  32.004 88.541 34.83 88.699 ;
     RECT  30.78 88.663 30.798 88.763 ;
     RECT  9.144 88.231 9.162 88.799 ;
     RECT  10.515 88.663 10.854 88.889 ;
     RECT  31.824 88.699 34.83 88.889 ;
     RECT  0.216 88.795 0.234 88.925 ;
     RECT  7.815 87.809 8.154 88.933 ;
     RECT  2.304 88.591 6.426 89.131 ;
     RECT  31.932 88.889 34.83 89.195 ;
     RECT  2.268 89.131 6.426 89.267 ;
     RECT  7.452 88.933 8.154 89.311 ;
     RECT  2.304 89.267 6.426 89.339 ;
     RECT  31.968 89.195 34.83 89.429 ;
     RECT  7.452 89.311 8.298 89.581 ;
     RECT  7.452 89.581 8.406 89.671 ;
     RECT  7.056 89.671 8.406 89.699 ;
     RECT  31.968 89.429 33.966 89.699 ;
     RECT  35.928 89.467 35.946 89.743 ;
     RECT  2.304 89.339 6.318 90.247 ;
     RECT  7.056 89.699 8.097 90.247 ;
     RECT  35.892 89.743 35.946 90.283 ;
     RECT  32.04 89.699 33.966 90.355 ;
     RECT  34.74 89.429 34.83 90.355 ;
     RECT  32.04 90.355 34.83 90.419 ;
     RECT  8.82 90.391 8.838 90.509 ;
     RECT  32.04 90.419 34.794 90.517 ;
     RECT  35.892 90.283 35.982 90.571 ;
     RECT  30.78 90.517 30.798 90.625 ;
     RECT  2.304 90.247 8.097 90.779 ;
     RECT  9.648 90.625 9.666 90.779 ;
     RECT  35.892 90.571 36.018 90.779 ;
     RECT  2.304 90.779 6.858 90.815 ;
     RECT  10.515 88.889 10.797 90.931 ;
     RECT  10.515 90.931 10.854 91.049 ;
     RECT  35.928 90.779 36.018 91.229 ;
     RECT  3.78 90.815 6.858 91.319 ;
     RECT  30.78 90.625 30.87 91.327 ;
     RECT  31.896 90.517 34.794 91.363 ;
     RECT  31.86 91.363 34.794 91.579 ;
     RECT  35.928 91.229 35.946 91.579 ;
     RECT  3.924 91.319 6.858 91.589 ;
     RECT  31.86 91.579 35.946 91.589 ;
     RECT  30.78 91.327 30.942 91.597 ;
     RECT  2.304 90.815 2.898 91.627 ;
     RECT  0.252 91.627 0.27 91.757 ;
     RECT  7.596 90.779 8.097 91.859 ;
     RECT  31.896 91.589 35.946 91.859 ;
     RECT  7.815 91.859 8.097 92.011 ;
     RECT  31.896 91.859 34.218 92.165 ;
     RECT  2.304 91.627 3.006 92.203 ;
     RECT  35.028 91.859 35.946 92.203 ;
     RECT  2.304 92.203 3.186 92.209 ;
     RECT  3.924 91.589 6.57 92.209 ;
     RECT  2.304 92.209 6.57 92.371 ;
     RECT  7.815 92.011 8.154 92.435 ;
     RECT  2.304 92.371 6.642 92.443 ;
     RECT  35.028 92.203 35.982 92.669 ;
     RECT  7.815 92.435 8.097 92.749 ;
     RECT  30.78 91.597 31.158 92.785 ;
     RECT  35.928 92.669 35.982 92.821 ;
     RECT  35.928 92.821 36.018 92.909 ;
     RECT  9.144 92.371 9.162 92.975 ;
     RECT  2.304 92.443 6.714 92.983 ;
     RECT  32.076 92.165 34.218 92.983 ;
     RECT  35.928 92.909 35.982 93.047 ;
     RECT  2.304 92.983 6.858 93.091 ;
     RECT  7.596 92.749 8.097 93.091 ;
     RECT  32.076 92.983 34.254 93.163 ;
     RECT  35.028 92.669 35.082 93.163 ;
     RECT  30.708 92.785 31.158 93.209 ;
     RECT  2.304 93.091 8.097 93.289 ;
     RECT  0.216 92.779 0.234 93.389 ;
     RECT  35.928 93.047 35.946 93.389 ;
     RECT  2.304 93.289 8.19 93.451 ;
     RECT  2.304 93.451 8.586 93.551 ;
     RECT  32.076 93.163 35.082 93.595 ;
     RECT  32.004 93.595 35.082 93.793 ;
     RECT  31.716 93.793 35.082 93.829 ;
     RECT  31.716 93.829 35.37 93.869 ;
     RECT  6.48 93.551 8.586 93.893 ;
     RECT  2.304 93.551 5.634 93.979 ;
     RECT  31.716 93.869 35.082 94.019 ;
     RECT  6.84 93.893 8.586 94.027 ;
     RECT  9.396 93.865 9.414 94.027 ;
     RECT  30.852 93.209 30.87 94.135 ;
     RECT  6.84 94.027 9.414 94.171 ;
     RECT  6.84 94.171 9.702 94.289 ;
     RECT  2.268 93.979 5.634 94.297 ;
     RECT  30.816 94.135 30.87 94.333 ;
     RECT  2.268 94.297 6.102 94.349 ;
     RECT  30.78 94.333 30.87 94.559 ;
     RECT  2.268 94.349 5.742 94.631 ;
     RECT  6.84 94.289 8.406 94.631 ;
     RECT  2.268 94.631 3.51 94.865 ;
     RECT  32.004 94.019 35.082 94.981 ;
     RECT  7.815 94.631 8.406 95.071 ;
     RECT  31.608 94.981 35.082 95.099 ;
     RECT  2.304 94.865 3.51 95.135 ;
     RECT  4.356 94.631 5.742 95.135 ;
     RECT  6.84 94.631 7.038 95.171 ;
     RECT  7.815 95.071 8.55 95.243 ;
     RECT  7.815 95.243 8.406 95.279 ;
     RECT  30.78 94.559 30.798 95.369 ;
     RECT  6.84 95.171 7.002 95.405 ;
     RECT  2.415 95.135 3.51 95.441 ;
     RECT  2.415 95.441 3.15 95.513 ;
     RECT  5.115 95.135 5.742 95.549 ;
     RECT  7.815 95.279 8.154 95.549 ;
     RECT  6.984 95.405 7.002 95.639 ;
     RECT  3.96 95.521 3.978 95.675 ;
     RECT  32.115 95.099 35.082 95.945 ;
     RECT  32.115 95.945 32.922 96.215 ;
     RECT  33.732 95.945 35.082 96.449 ;
     RECT  33.732 96.449 34.47 96.485 ;
     RECT  33.948 96.485 34.47 96.719 ;
     RECT  33.948 96.719 33.966 96.755 ;
     RECT  2.415 95.513 2.697 96.947 ;
     RECT  5.115 95.549 5.397 96.947 ;
     RECT  7.815 95.549 8.097 96.947 ;
     RECT  10.515 91.049 10.797 96.947 ;
     RECT  13.215 2.413 13.497 96.947 ;
     RECT  15.915 2.413 16.197 96.947 ;
     RECT  18.615 2.413 18.897 96.947 ;
     RECT  21.315 61.997 21.597 96.947 ;
     RECT  24.015 2.413 24.297 96.947 ;
     RECT  26.715 2.413 26.997 96.947 ;
     RECT  29.415 61.997 29.697 96.947 ;
     RECT  32.115 96.215 32.397 96.947 ;
     RECT  2.415 96.947 2.505 97.217 ;
     RECT  5.115 96.947 5.205 97.217 ;
     RECT  7.815 96.947 7.905 97.217 ;
     RECT  10.515 96.947 10.605 97.217 ;
     RECT  13.215 96.947 13.305 97.217 ;
     RECT  15.915 96.947 16.005 97.217 ;
     RECT  18.615 96.947 18.705 97.217 ;
     RECT  21.315 96.947 21.405 97.217 ;
     RECT  24.015 96.947 24.105 97.217 ;
     RECT  26.715 96.947 26.805 97.217 ;
     RECT  29.415 96.947 29.505 97.217 ;
     RECT  32.115 96.947 32.205 97.217 ;
     RECT  18.18 99.228 18.198 99.245 ;
    LAYER M4 ;
     RECT  0.156 4.416 2.408 95.016 ;
     RECT  2.408 2.148 2.512 97.212 ;
     RECT  2.512 2.418 2.704 96.942 ;
     RECT  2.704 54.096 2.729 55.32 ;
     RECT  2.704 16.896 2.765 18.552 ;
     RECT  2.704 36.864 2.765 42.84 ;
     RECT  2.704 47.856 2.765 50.952 ;
     RECT  2.704 52.512 2.765 52.536 ;
     RECT  2.704 61.392 2.765 64.392 ;
     RECT  2.704 72.432 2.765 76.872 ;
     RECT  2.704 78.912 2.765 78.936 ;
     RECT  2.704 79.968 2.765 83.64 ;
     RECT  2.704 88.896 2.765 89.496 ;
     RECT  2.704 90.576 2.765 93.288 ;
     RECT  2.704 5.568 2.801 9.24 ;
     RECT  2.704 10.416 2.801 11.928 ;
     RECT  2.765 16.896 2.801 16.92 ;
     RECT  2.765 18.192 2.801 18.216 ;
     RECT  2.704 24.624 2.801 28.536 ;
     RECT  2.704 29.52 2.801 33.096 ;
     RECT  2.704 84.816 2.801 84.936 ;
     RECT  2.801 10.416 2.837 10.584 ;
     RECT  2.801 29.952 2.839 32.28 ;
     RECT  2.765 38.688 2.867 42.6 ;
     RECT  2.704 13.344 2.873 15.864 ;
     RECT  2.867 38.736 2.873 42.6 ;
     RECT  2.765 47.856 2.873 50.184 ;
     RECT  2.765 72.432 2.873 73.368 ;
     RECT  2.704 94.656 2.873 94.68 ;
     RECT  2.873 14.304 2.909 15.864 ;
     RECT  2.704 67.68 2.909 67.704 ;
     RECT  2.873 41.184 2.981 42.6 ;
     RECT  2.704 34.08 3.017 35.352 ;
     RECT  2.704 69.456 3.017 71.16 ;
     RECT  2.873 72.864 3.017 73.368 ;
     RECT  2.765 75.12 3.017 76.872 ;
     RECT  2.765 91.632 3.017 93.288 ;
     RECT  2.765 88.896 3.089 88.92 ;
     RECT  2.765 90.576 3.089 90.6 ;
     RECT  2.873 38.736 3.125 39.528 ;
     RECT  2.704 43.872 3.125 46.776 ;
     RECT  3.017 71.136 3.125 71.16 ;
     RECT  2.801 5.568 3.197 6.264 ;
     RECT  2.704 20.016 3.197 21.96 ;
     RECT  3.017 92.208 3.197 92.808 ;
     RECT  3.197 20.016 3.233 20.376 ;
     RECT  2.981 41.424 3.233 42.6 ;
     RECT  2.839 29.952 3.277 32.232 ;
     RECT  2.909 14.304 3.305 15.288 ;
     RECT  2.704 65.472 3.305 65.496 ;
     RECT  2.765 79.968 3.305 83.064 ;
     RECT  2.704 87.6 3.305 87.624 ;
     RECT  2.801 11.76 3.341 11.928 ;
     RECT  2.801 24.624 3.377 26.568 ;
     RECT  2.704 4.512 3.443 4.536 ;
     RECT  2.801 7.824 3.443 7.848 ;
     RECT  3.197 21.36 3.443 21.96 ;
     RECT  3.377 24.624 3.443 26.28 ;
     RECT  2.873 47.856 3.521 47.88 ;
     RECT  2.765 61.392 3.557 63.816 ;
     RECT  3.305 81.264 3.628 82.152 ;
     RECT  2.704 56.448 3.685 58.536 ;
     RECT  3.685 56.448 3.697 58.824 ;
     RECT  2.704 60.288 3.697 60.312 ;
     RECT  3.697 56.448 3.731 60.312 ;
     RECT  2.765 36.864 3.733 37.128 ;
     RECT  3.731 58.656 3.733 60.312 ;
     RECT  3.74 78 3.781 78.024 ;
     RECT  3.233 20.016 3.805 20.04 ;
     RECT  2.837 10.56 3.827 10.584 ;
     RECT  3.017 76.032 3.827 76.68 ;
     RECT  3.305 79.968 3.827 79.992 ;
     RECT  2.729 55.296 3.836 55.32 ;
     RECT  3.731 56.448 3.836 57.336 ;
     RECT  3.341 11.904 3.841 11.928 ;
     RECT  2.801 84.816 3.841 84.84 ;
     RECT  3.841 84.816 3.877 85.176 ;
     RECT  3.841 11.904 3.913 12.504 ;
     RECT  3.277 31.104 3.913 32.232 ;
     RECT  3.877 86.496 3.913 86.52 ;
     RECT  3.836 55.296 3.923 57.336 ;
     RECT  3.836 88.848 3.923 88.872 ;
     RECT  2.873 49.392 3.925 50.184 ;
     RECT  3.733 58.656 3.925 60.36 ;
     RECT  3.557 61.392 3.925 63.288 ;
     RECT  3.913 31.104 3.949 32.52 ;
     RECT  3.628 82.128 3.953 82.152 ;
     RECT  3.925 58.656 3.971 63.288 ;
     RECT  3.877 84.336 3.971 85.176 ;
     RECT  3.913 11.904 3.973 13.08 ;
     RECT  3.305 14.304 3.973 15.048 ;
     RECT  3.017 34.224 3.98 35.352 ;
     RECT  3.733 36.528 3.98 37.128 ;
     RECT  3.125 38.736 3.98 39.24 ;
     RECT  3.973 11.904 4.019 15.048 ;
     RECT  3.125 44.304 4.019 46.776 ;
     RECT  3.98 38.64 4.057 39.24 ;
     RECT  3.971 58.656 4.067 60.936 ;
     RECT  3.877 90.864 4.093 90.888 ;
     RECT  4.019 45.12 4.133 46.776 ;
     RECT  3.781 78 4.201 78.744 ;
     RECT  4.133 45.168 4.22 46.776 ;
     RECT  3.925 49.392 4.229 50.76 ;
     RECT  4.019 13.632 4.268 15.048 ;
     RECT  3.233 41.616 4.316 42.6 ;
     RECT  3.805 19.632 4.345 20.04 ;
     RECT  4.229 49.008 4.381 50.76 ;
     RECT  3.443 25.056 4.405 26.28 ;
     RECT  2.704 23.52 4.412 23.544 ;
     RECT  4.345 19.2 4.453 20.04 ;
     RECT  3.443 21.936 4.453 21.96 ;
     RECT  2.801 9.216 4.46 9.24 ;
     RECT  4.46 9.072 4.501 9.24 ;
     RECT  4.019 11.904 4.501 12.504 ;
     RECT  3.277 29.952 4.501 29.976 ;
     RECT  3.949 31.104 4.501 32.616 ;
     RECT  4.093 66.144 4.517 66.168 ;
     RECT  3.877 17.04 4.525 17.064 ;
     RECT  4.405 76.896 4.525 76.92 ;
     RECT  4.201 78 4.525 78.936 ;
     RECT  3.98 34.224 4.597 37.128 ;
     RECT  4.057 38.112 4.597 39.24 ;
     RECT  4.405 25.056 4.604 26.76 ;
     RECT  4.345 92.64 4.633 92.664 ;
     RECT  2.801 28.512 4.645 28.536 ;
     RECT  4.501 29.952 4.645 32.616 ;
     RECT  4.525 76.896 4.669 78.936 ;
     RECT  4.093 90.624 4.669 90.888 ;
     RECT  4.669 90.528 4.693 90.888 ;
     RECT  4.412 23.52 4.741 24.072 ;
     RECT  3.913 86.496 4.789 87.048 ;
     RECT  3.923 56.448 4.837 57.336 ;
     RECT  4.517 65.52 4.837 66.168 ;
     RECT  4.364 75.792 4.844 75.816 ;
     RECT  4.669 76.896 4.844 79.272 ;
     RECT  3.197 5.616 4.885 6.264 ;
     RECT  2.729 54.096 4.885 54.12 ;
     RECT  4.741 74.304 4.885 74.328 ;
     RECT  4.741 64.32 4.94 64.344 ;
     RECT  4.837 65.52 4.94 66.6 ;
     RECT  4.501 9.072 4.981 9.96 ;
     RECT  4.501 11.232 4.981 12.504 ;
     RECT  4.741 23.184 4.981 24.072 ;
     RECT  4.604 25.056 4.981 27.336 ;
     RECT  4.129 52.848 4.981 52.872 ;
     RECT  4.885 54.096 4.981 54.168 ;
     RECT  4.837 56.448 4.981 57.432 ;
     RECT  4.067 58.656 4.981 58.968 ;
     RECT  4.067 60.336 4.981 60.936 ;
     RECT  3.971 85.056 4.993 85.176 ;
     RECT  4.885 5.568 5.108 6.264 ;
     RECT  4.981 8.448 5.108 12.504 ;
     RECT  4.268 13.632 5.108 15.096 ;
     RECT  4.525 16.272 5.108 17.064 ;
     RECT  4.453 19.2 5.108 22.2 ;
     RECT  4.981 23.184 5.108 27.336 ;
     RECT  4.645 28.512 5.108 32.616 ;
     RECT  4.597 34.224 5.108 39.24 ;
     RECT  4.117 40.608 5.108 40.632 ;
     RECT  4.316 41.616 5.108 42.696 ;
     RECT  4.22 45.168 5.108 47.688 ;
     RECT  4.381 49.008 5.108 50.904 ;
     RECT  4.981 52.848 5.108 54.168 ;
     RECT  3.923 55.296 5.108 55.368 ;
     RECT  4.981 56.352 5.108 58.968 ;
     RECT  4.981 60.336 5.108 61.464 ;
     RECT  3.971 62.592 5.108 63.288 ;
     RECT  4.94 64.32 5.108 66.6 ;
     RECT  3.017 69.456 5.108 70.152 ;
     RECT  5.065 71.472 5.108 71.496 ;
     RECT  3.017 72.864 5.108 72.888 ;
     RECT  4.885 74.304 5.108 74.712 ;
     RECT  4.844 75.792 5.108 79.272 ;
     RECT  4.981 80.352 5.108 80.376 ;
     RECT  4.597 82.032 5.108 82.056 ;
     RECT  4.885 83.232 5.108 83.832 ;
     RECT  4.993 84.864 5.108 85.176 ;
     RECT  4.789 86.16 5.108 87.048 ;
     RECT  4.453 89.424 5.108 89.544 ;
     RECT  4.693 90.528 5.108 91.608 ;
     RECT  4.633 92.64 5.108 92.808 ;
     RECT  4.741 94.08 5.108 94.104 ;
     RECT  5.108 2.148 5.212 97.212 ;
     RECT  5.212 2.418 5.404 96.942 ;
     RECT  5.404 82.656 5.429 87.048 ;
     RECT  5.404 13.632 5.465 13.704 ;
     RECT  5.404 38.688 5.555 39.48 ;
     RECT  5.404 49.488 5.555 49.8 ;
     RECT  5.404 70.08 5.555 71.784 ;
     RECT  5.404 88.944 5.555 88.968 ;
     RECT  5.404 74.064 5.573 74.712 ;
     RECT  5.404 94.08 5.645 94.344 ;
     RECT  5.404 5.568 5.681 5.592 ;
     RECT  5.555 38.784 5.681 39.48 ;
     RECT  5.404 76.464 5.681 81.48 ;
     RECT  5.404 15.312 5.699 17.064 ;
     RECT  5.404 29.376 5.699 29.4 ;
     RECT  5.404 30.48 5.699 33.336 ;
     RECT  5.404 23.856 5.753 25.464 ;
     RECT  5.555 49.488 5.789 49.608 ;
     RECT  5.404 50.784 5.891 52.44 ;
     RECT  5.573 74.064 5.891 74.088 ;
     RECT  5.681 76.464 5.891 80.424 ;
     RECT  5.404 44.976 5.897 47.88 ;
     RECT  5.555 70.08 5.897 70.584 ;
     RECT  5.404 42.72 5.905 42.744 ;
     RECT  5.404 53.52 5.932 53.544 ;
     RECT  5.404 6.816 5.939 8.568 ;
     RECT  5.891 76.944 5.939 80.424 ;
     RECT  5.404 54.624 6.005 58.968 ;
     RECT  5.897 70.56 6.005 70.584 ;
     RECT  5.681 81.456 6.005 81.48 ;
     RECT  5.753 23.856 6.028 25.08 ;
     RECT  5.404 60.24 6.035 63.528 ;
     RECT  5.429 82.656 6.041 86.856 ;
     RECT  5.939 8.544 6.113 8.568 ;
     RECT  5.404 64.848 6.113 68.616 ;
     RECT  5.404 9.936 6.131 9.96 ;
     RECT  5.404 12.144 6.131 12.168 ;
     RECT  5.465 13.632 6.131 13.656 ;
     RECT  6.113 65.376 6.131 68.616 ;
     RECT  5.555 71.76 6.179 71.784 ;
     RECT  5.699 31.728 6.227 33.336 ;
     RECT  6.131 66.432 6.227 68.232 ;
     RECT  5.699 15.696 6.275 17.064 ;
     RECT  5.404 18.816 6.275 21.672 ;
     RECT  6.275 16.56 6.293 17.064 ;
     RECT  5.699 30.48 6.293 30.504 ;
     RECT  5.681 38.784 6.293 38.808 ;
     RECT  6.227 67.776 6.293 68.232 ;
     RECT  5.939 76.944 6.293 78.936 ;
     RECT  5.404 91.152 6.293 91.176 ;
     RECT  6.028 24.624 6.365 25.08 ;
     RECT  6.227 66.432 6.365 66.456 ;
     RECT  6.293 77.52 6.365 78.936 ;
     RECT  6.005 54.624 6.371 57.432 ;
     RECT  6.293 17.04 6.469 17.064 ;
     RECT  5.897 44.976 6.469 46.776 ;
     RECT  6.371 56.4 6.473 56.424 ;
     RECT  5.891 50.784 6.541 51.288 ;
     RECT  6.365 24.624 6.545 24.648 ;
     RECT  6.041 83.232 6.545 86.856 ;
     RECT  5.404 27.072 6.572 27.096 ;
     RECT  5.789 49.584 6.613 49.608 ;
     RECT  6.541 50.592 6.613 51.288 ;
     RECT  6.005 58.512 6.613 58.968 ;
     RECT  6.035 60.24 6.613 61.752 ;
     RECT  6.545 84.192 6.617 86.856 ;
     RECT  6.469 44.016 6.648 46.776 ;
     RECT  6.572 27.072 6.659 27.912 ;
     RECT  6.227 31.728 6.659 32.712 ;
     RECT  6.572 34.32 6.659 34.344 ;
     RECT  5.939 80.4 6.659 80.424 ;
     RECT  6.572 92.832 6.659 92.856 ;
     RECT  6.709 74.832 6.716 74.856 ;
     RECT  5.404 40.608 6.721 40.632 ;
     RECT  6.617 84.864 6.725 86.856 ;
     RECT  6.648 43.152 6.755 46.776 ;
     RECT  5.404 72.816 6.755 72.936 ;
     RECT  6.659 31.728 6.757 32.472 ;
     RECT  5.939 7.2 6.761 7.224 ;
     RECT  6.709 42.048 6.796 42.072 ;
     RECT  6.716 74.832 6.797 75.816 ;
     RECT  6.365 77.52 6.803 77.544 ;
     RECT  5.404 35.328 6.829 37.032 ;
     RECT  6.829 35.136 6.853 37.032 ;
     RECT  6.613 58.512 7.045 61.752 ;
     RECT  6.725 86.64 7.1 86.856 ;
     RECT  5.897 47.856 7.153 47.88 ;
     RECT  6.469 17.04 7.261 17.112 ;
     RECT  6.365 78.624 7.261 78.936 ;
     RECT  5.645 94.32 7.369 94.344 ;
     RECT  6.853 35.136 7.381 37.608 ;
     RECT  6.755 44.976 7.381 46.776 ;
     RECT  7.153 47.856 7.381 48.504 ;
     RECT  6.797 75.792 7.429 75.816 ;
     RECT  7.225 5.568 7.808 6.264 ;
     RECT  7.081 7.44 7.808 7.464 ;
     RECT  7.081 9.072 7.808 9.096 ;
     RECT  7.117 10.848 7.808 10.872 ;
     RECT  6.937 13.584 7.808 13.608 ;
     RECT  6.721 14.88 7.808 15.432 ;
     RECT  7.261 17.04 7.808 17.64 ;
     RECT  6.275 19.152 7.808 20.904 ;
     RECT  7.436 23.856 7.808 23.88 ;
     RECT  7.477 25.536 7.808 25.56 ;
     RECT  6.659 27.072 7.808 27.24 ;
     RECT  7.585 29.088 7.808 29.112 ;
     RECT  6.757 30.672 7.808 32.472 ;
     RECT  6.853 33.984 7.808 34.008 ;
     RECT  7.381 35.136 7.808 38.424 ;
     RECT  7.477 39.504 7.808 39.528 ;
     RECT  6.721 40.608 7.808 41.016 ;
     RECT  6.755 43.152 7.808 43.176 ;
     RECT  7.381 44.976 7.808 48.504 ;
     RECT  6.613 49.584 7.808 51.288 ;
     RECT  5.891 52.416 7.808 52.44 ;
     RECT  6.371 54.624 7.808 55.272 ;
     RECT  6.371 57.408 7.808 57.432 ;
     RECT  7.045 58.512 7.808 62.232 ;
     RECT  7.004 63.504 7.808 63.528 ;
     RECT  6.131 65.376 7.808 65.4 ;
     RECT  6.293 67.776 7.808 67.8 ;
     RECT  7.261 71.904 7.808 71.928 ;
     RECT  6.755 72.912 7.808 72.936 ;
     RECT  7.429 75.792 7.808 76.392 ;
     RECT  7.261 78.624 7.808 79.224 ;
     RECT  7.189 80.592 7.808 80.616 ;
     RECT  7.1 82.32 7.808 82.344 ;
     RECT  6.725 84.864 7.808 85.608 ;
     RECT  7.1 86.64 7.808 87.72 ;
     RECT  7.141 90.528 7.808 90.552 ;
     RECT  7.369 93.504 7.808 94.344 ;
     RECT  7.808 2.148 7.912 97.212 ;
     RECT  7.912 2.418 8.104 96.942 ;
     RECT  8.104 25.536 8.165 25.56 ;
     RECT  8.104 45.984 8.165 46.776 ;
     RECT  8.104 36.24 8.201 36.312 ;
     RECT  8.104 61.728 8.201 62.856 ;
     RECT  8.104 39.504 8.243 40.248 ;
     RECT  8.104 38.4 8.265 38.424 ;
     RECT  8.104 20.832 8.273 20.904 ;
     RECT  8.104 47.856 8.273 47.88 ;
     RECT  8.243 40.224 8.281 40.248 ;
     RECT  8.104 41.904 8.284 41.928 ;
     RECT  8.104 14.928 8.309 14.952 ;
     RECT  8.104 50.544 8.309 50.616 ;
     RECT  8.201 36.288 8.381 36.312 ;
     RECT  8.201 61.872 8.387 62.856 ;
     RECT  8.104 64.176 8.387 64.2 ;
     RECT  8.104 67.488 8.387 67.512 ;
     RECT  8.104 70.8 8.387 70.824 ;
     RECT  8.104 71.904 8.387 71.928 ;
     RECT  8.104 84.864 8.417 84.888 ;
     RECT  8.387 61.872 8.425 62.136 ;
     RECT  8.104 60.48 8.453 60.504 ;
     RECT  8.104 5.568 8.489 5.592 ;
     RECT  8.309 50.592 8.489 50.616 ;
     RECT  8.273 20.832 10.508 20.856 ;
     RECT  8.165 46.752 10.508 46.776 ;
     RECT  8.425 61.872 10.508 61.896 ;
     RECT  10.508 2.148 10.612 97.212 ;
     RECT  10.612 2.418 10.804 96.942 ;
     RECT  10.804 20.832 13.208 20.856 ;
     RECT  10.804 46.752 13.208 46.776 ;
     RECT  10.804 61.872 13.208 61.896 ;
     RECT  13.208 2.148 13.312 97.212 ;
     RECT  13.312 2.418 13.504 96.942 ;
     RECT  13.504 20.832 14.821 20.856 ;
     RECT  13.504 46.752 14.821 46.776 ;
     RECT  13.504 61.872 14.821 61.896 ;
     RECT  14.821 20.832 14.861 20.952 ;
     RECT  14.821 46.752 14.861 46.872 ;
     RECT  14.821 61.872 14.861 61.992 ;
     RECT  14.861 20.928 15.908 20.952 ;
     RECT  14.861 46.848 15.908 46.872 ;
     RECT  14.861 61.968 15.908 61.992 ;
     RECT  15.908 2.148 16.012 97.212 ;
     RECT  16.012 2.418 16.204 96.942 ;
     RECT  5.653 99.216 18.209 99.24 ;
     RECT  16.204 20.928 18.608 20.952 ;
     RECT  16.204 46.848 18.608 46.872 ;
     RECT  16.204 61.968 18.608 61.992 ;
     RECT  18.608 2.148 18.712 97.212 ;
     RECT  18.712 2.418 18.904 96.942 ;
     RECT  18.904 20.928 21.308 20.952 ;
     RECT  18.904 46.848 21.308 46.872 ;
     RECT  18.904 61.968 21.308 61.992 ;
     RECT  21.308 2.148 21.412 97.212 ;
     RECT  21.412 2.418 21.604 96.942 ;
     RECT  21.604 20.832 21.701 20.952 ;
     RECT  21.604 46.752 21.701 46.872 ;
     RECT  21.604 61.872 21.701 61.992 ;
     RECT  21.701 20.832 22.813 20.856 ;
     RECT  21.701 46.752 22.813 46.776 ;
     RECT  21.701 61.872 22.813 61.896 ;
     RECT  22.813 20.832 22.853 20.952 ;
     RECT  22.813 46.752 22.853 46.872 ;
     RECT  22.813 61.872 22.853 61.992 ;
     RECT  22.853 20.928 24.008 20.952 ;
     RECT  22.853 46.848 24.008 46.872 ;
     RECT  22.853 61.968 24.008 61.992 ;
     RECT  24.008 2.148 24.112 97.212 ;
     RECT  24.112 2.418 24.304 96.942 ;
     RECT  24.304 20.928 26.708 20.952 ;
     RECT  24.304 46.848 26.708 46.872 ;
     RECT  24.304 61.968 26.708 61.992 ;
     RECT  26.708 2.148 26.812 97.212 ;
     RECT  26.812 2.418 27.004 96.942 ;
     RECT  27.004 20.928 29.408 20.952 ;
     RECT  27.004 46.848 29.408 46.872 ;
     RECT  27.004 61.968 29.408 61.992 ;
     RECT  29.408 2.148 29.512 97.212 ;
     RECT  29.512 2.418 29.704 96.942 ;
     RECT  29.704 20.832 29.801 20.952 ;
     RECT  29.704 46.752 29.801 46.872 ;
     RECT  29.704 61.872 29.801 61.992 ;
     RECT  29.801 20.832 30.769 20.856 ;
     RECT  29.801 46.752 30.769 46.776 ;
     RECT  29.801 61.872 30.769 61.896 ;
     RECT  30.769 20.832 30.809 20.952 ;
     RECT  30.769 46.752 30.809 46.872 ;
     RECT  30.769 61.872 30.809 61.992 ;
     RECT  30.809 61.968 31.777 61.992 ;
     RECT  30.809 46.848 31.957 46.872 ;
     RECT  31.777 61.968 32.065 62.184 ;
     RECT  31.849 16.8 32.108 16.824 ;
     RECT  30.809 20.928 32.108 20.952 ;
     RECT  31.885 34.8 32.108 34.824 ;
     RECT  32.029 42.192 32.108 42.216 ;
     RECT  32.065 45.264 32.108 45.288 ;
     RECT  31.957 46.848 32.108 47.16 ;
     RECT  31.777 58.944 32.108 58.968 ;
     RECT  32.065 61.968 32.108 62.568 ;
     RECT  32.065 88.704 32.108 88.728 ;
     RECT  32.108 2.148 32.212 97.212 ;
     RECT  32.212 2.418 32.404 96.942 ;
     RECT  32.404 16.8 32.501 16.824 ;
     RECT  32.404 87.84 32.501 89.064 ;
     RECT  32.404 46.848 32.789 47.592 ;
     RECT  32.404 66.528 32.861 66.552 ;
     RECT  32.404 50.4 32.969 50.424 ;
     RECT  32.404 37.392 33.005 38.184 ;
     RECT  32.404 45.264 33.077 45.72 ;
     RECT  32.404 61.536 33.113 63.576 ;
     RECT  32.404 11.952 33.185 13.608 ;
     RECT  32.501 87.84 33.221 88.728 ;
     RECT  32.404 55.92 33.397 55.944 ;
     RECT  32.404 68.112 33.401 68.136 ;
     RECT  32.404 84.624 33.401 84.648 ;
     RECT  32.404 58.944 33.433 58.968 ;
     RECT  33.077 45.264 33.437 45.576 ;
     RECT  33.397 55.92 33.437 56.52 ;
     RECT  32.404 33.024 33.545 33.048 ;
     RECT  32.404 18.48 33.577 18.504 ;
     RECT  32.404 42.144 33.577 42.216 ;
     RECT  33.577 41.664 33.581 42.216 ;
     RECT  32.404 79.248 33.653 79.272 ;
     RECT  32.789 47.04 33.685 47.592 ;
     RECT  33.541 66.48 33.685 66.504 ;
     RECT  33.113 61.632 33.725 63.576 ;
     RECT  32.404 75.696 33.725 76.344 ;
     RECT  32.404 77.808 33.725 77.832 ;
     RECT  33.469 90 33.725 90.024 ;
     RECT  32.404 60.336 33.761 60.36 ;
     RECT  32.404 30.336 33.829 30.36 ;
     RECT  33.757 5.712 33.973 5.736 ;
     RECT  33.973 4.896 34.117 5.736 ;
     RECT  33.685 66.336 34.153 66.504 ;
     RECT  33.437 56.496 34.157 56.52 ;
     RECT  33.185 11.952 34.189 12.264 ;
     RECT  33.185 13.584 34.189 13.608 ;
     RECT  33.577 18.48 34.189 18.744 ;
     RECT  32.404 20.832 34.189 21.672 ;
     RECT  33.541 26.736 34.189 26.76 ;
     RECT  33.829 30.336 34.189 30.648 ;
     RECT  32.404 39.312 34.189 39.336 ;
     RECT  33.581 41.664 34.189 41.88 ;
     RECT  33.437 45.552 34.189 45.576 ;
     RECT  33.685 47.04 34.189 47.688 ;
     RECT  34.117 48.816 34.189 48.84 ;
     RECT  33.541 52.368 34.189 52.392 ;
     RECT  33.433 58.032 34.189 58.968 ;
     RECT  33.725 61.632 34.189 62.904 ;
     RECT  34.153 66.336 34.189 66.648 ;
     RECT  32.404 69.264 34.189 69.288 ;
     RECT  33.685 72.768 34.189 72.792 ;
     RECT  33.865 80.88 34.189 80.904 ;
     RECT  32.404 82.032 34.189 83.16 ;
     RECT  33.469 91.392 34.189 91.416 ;
     RECT  34.117 4.896 34.225 6.216 ;
     RECT  33.541 7.344 34.225 7.368 ;
     RECT  34.189 15.6 34.225 17.256 ;
     RECT  34.189 18.48 34.225 19.32 ;
     RECT  34.189 54.48 34.225 54.84 ;
     RECT  34.189 66.288 34.225 66.648 ;
     RECT  34.189 70.848 34.225 70.872 ;
     RECT  34.189 71.904 34.225 74.28 ;
     RECT  34.225 15.6 34.261 19.32 ;
     RECT  34.189 93.024 34.441 93.72 ;
     RECT  34.297 94.8 34.441 94.824 ;
     RECT  34.189 33.744 34.657 36.168 ;
     RECT  34.225 66.288 34.693 66.984 ;
     RECT  34.189 68.544 34.693 69.384 ;
     RECT  34.189 80.736 34.693 83.16 ;
     RECT  34.189 8.928 34.729 14.472 ;
     RECT  34.261 15.6 34.729 19.848 ;
     RECT  34.657 32.928 34.729 36.168 ;
     RECT  33.005 37.392 34.729 37.416 ;
     RECT  34.189 38.736 34.729 41.88 ;
     RECT  34.189 43.44 34.729 43.464 ;
     RECT  34.189 45.552 34.729 45.768 ;
     RECT  34.189 51.552 34.729 53.208 ;
     RECT  34.189 56.592 34.729 58.968 ;
     RECT  34.189 60.48 34.729 62.904 ;
     RECT  34.189 63.888 34.729 64.536 ;
     RECT  34.693 66.288 34.729 69.384 ;
     RECT  34.225 70.848 34.729 74.28 ;
     RECT  33.725 76.32 34.729 76.344 ;
     RECT  34.189 78.288 34.729 79.128 ;
     RECT  34.189 87.024 34.729 87.048 ;
     RECT  34.693 89.28 34.729 89.304 ;
     RECT  34.189 90.432 34.729 91.896 ;
     RECT  34.225 4.896 34.765 7.368 ;
     RECT  34.729 8.928 34.765 19.848 ;
     RECT  34.189 20.832 34.765 31.512 ;
     RECT  34.729 32.928 34.765 37.416 ;
     RECT  34.729 38.736 34.765 43.464 ;
     RECT  34.729 51.408 34.765 53.208 ;
     RECT  34.225 54.48 34.765 54.984 ;
     RECT  34.729 60.48 34.765 64.536 ;
     RECT  34.729 66.288 34.765 74.904 ;
     RECT  34.729 76.32 34.765 79.128 ;
     RECT  34.693 80.736 34.765 83.64 ;
     RECT  34.729 87.024 34.765 87.864 ;
     RECT  34.729 88.992 34.765 91.896 ;
     RECT  34.765 4.896 34.801 43.944 ;
     RECT  34.189 47.04 34.801 49.656 ;
     RECT  34.765 85.104 34.801 85.128 ;
     RECT  34.765 86.4 34.801 91.896 ;
     RECT  34.441 93.024 34.801 94.824 ;
     RECT  34.801 85.104 35.017 91.896 ;
     RECT  34.801 93.024 35.017 95.016 ;
     RECT  34.801 4.896 35.341 44.472 ;
     RECT  34.729 45.552 35.341 46.056 ;
     RECT  34.801 47.04 35.341 50.424 ;
     RECT  34.765 51.408 35.341 54.984 ;
     RECT  34.765 66.288 35.341 79.608 ;
     RECT  34.765 80.736 35.341 83.976 ;
     RECT  35.017 85.104 35.341 95.016 ;
     RECT  35.341 4.416 35.377 46.056 ;
     RECT  35.341 47.04 35.377 55.128 ;
     RECT  35.377 4.416 35.917 55.128 ;
     RECT  34.729 56.592 35.917 59.016 ;
     RECT  34.765 60 35.917 64.536 ;
     RECT  35.341 65.664 35.917 95.016 ;
     RECT  35.917 4.416 36.54 95.016 ;
    LAYER M5 ;
     RECT  2.4 2.137 2.52 2.151 ;
     RECT  5.1 2.137 5.22 2.151 ;
     RECT  7.8 2.137 7.92 2.151 ;
     RECT  10.5 2.137 10.62 2.151 ;
     RECT  13.2 2.137 13.32 2.151 ;
     RECT  15.9 2.137 16.02 2.151 ;
     RECT  18.6 2.137 18.72 2.151 ;
     RECT  21.3 2.137 21.42 2.151 ;
     RECT  24 2.137 24.12 2.151 ;
     RECT  26.7 2.137 26.82 2.151 ;
     RECT  29.4 2.137 29.52 2.151 ;
     RECT  32.1 2.137 32.22 2.151 ;
     RECT  2.4 2.151 2.712 4.501 ;
     RECT  2.4 4.501 3.432 5.605 ;
     RECT  5.1 2.151 5.412 5.605 ;
     RECT  7.8 2.151 8.112 6.229 ;
     RECT  2.4 5.605 5.412 6.275 ;
     RECT  5.1 6.275 5.412 6.805 ;
     RECT  7.248 6.229 8.112 7.475 ;
     RECT  5.1 6.805 5.928 8.437 ;
     RECT  4.992 8.437 5.928 8.579 ;
     RECT  4.992 8.579 5.412 9.061 ;
     RECT  7.8 7.475 8.112 9.061 ;
     RECT  2.4 6.275 3.432 9.205 ;
     RECT  4.512 9.061 5.412 9.205 ;
     RECT  2.4 9.205 5.412 9.251 ;
     RECT  3.792 9.251 5.412 9.925 ;
     RECT  7.152 9.061 8.112 10.883 ;
     RECT  3.792 9.925 6.12 11.267 ;
     RECT  2.4 9.251 2.712 11.893 ;
     RECT  3.792 11.267 3.816 11.893 ;
     RECT  2.4 11.893 3.816 11.939 ;
     RECT  5.1 11.267 6.12 12.179 ;
     RECT  2.4 11.939 3.48 13.045 ;
     RECT  7.8 10.883 8.112 13.573 ;
     RECT  5.1 12.179 5.412 13.621 ;
     RECT  2.4 13.045 4.008 13.667 ;
     RECT  2.4 13.667 3.48 14.339 ;
     RECT  5.1 13.621 6.12 14.485 ;
     RECT  4.704 14.485 6.12 15.061 ;
     RECT  7.152 13.573 8.112 15.443 ;
     RECT  4.32 15.061 6.12 16.357 ;
     RECT  7.8 15.443 8.112 17.605 ;
     RECT  4.32 16.357 6.264 19.141 ;
     RECT  7.296 17.605 8.112 19.141 ;
     RECT  4.32 19.141 8.112 19.955 ;
     RECT  2.4 14.339 2.712 20.005 ;
     RECT  4.32 19.955 6.264 20.005 ;
     RECT  2.4 20.005 6.264 20.051 ;
     RECT  4.464 20.051 6.264 21.683 ;
     RECT  7.8 19.955 8.112 23.845 ;
     RECT  4.464 21.683 6.216 24.083 ;
     RECT  4.992 24.083 6.216 25.045 ;
     RECT  2.4 20.051 3.432 26.291 ;
     RECT  4.416 25.045 6.216 26.771 ;
     RECT  4.656 26.771 6.216 27.061 ;
     RECT  7.488 23.845 8.112 27.061 ;
     RECT  4.656 27.061 8.112 27.251 ;
     RECT  4.656 27.251 6.648 29.123 ;
     RECT  7.68 27.251 8.112 29.123 ;
     RECT  2.4 26.291 2.712 30.709 ;
     RECT  5.1 29.123 6.648 30.709 ;
     RECT  2.4 30.709 3.24 31.427 ;
     RECT  4.512 30.709 6.648 31.907 ;
     RECT  2.4 31.427 2.856 32.243 ;
     RECT  5.1 31.907 6.648 32.437 ;
     RECT  7.8 29.123 8.112 32.437 ;
     RECT  4.032 34.213 4.056 35.845 ;
     RECT  5.1 32.437 8.112 35.845 ;
     RECT  4.032 35.845 8.112 37.619 ;
     RECT  7.392 37.619 8.112 38.389 ;
     RECT  7.392 38.389 8.232 38.435 ;
     RECT  2.4 32.243 2.712 38.677 ;
     RECT  2.4 38.677 2.856 39.251 ;
     RECT  0.288 38.725 0.312 39.539 ;
     RECT  7.8 38.435 8.232 41.939 ;
     RECT  4.032 37.619 6.216 42.037 ;
     RECT  4.032 42.037 6.744 42.181 ;
     RECT  3.984 42.181 6.744 42.707 ;
     RECT  5.1 42.707 6.744 44.051 ;
     RECT  3.984 42.707 4.008 45.155 ;
     RECT  5.1 44.051 6.216 46.741 ;
     RECT  7.8 41.939 8.112 47.317 ;
     RECT  4.272 46.741 6.216 47.845 ;
     RECT  7.392 47.317 8.112 47.845 ;
     RECT  4.272 47.845 8.112 48.515 ;
     RECT  4.272 48.515 6.648 49.043 ;
     RECT  2.4 39.251 2.712 49.381 ;
     RECT  2.4 49.381 3.96 50.195 ;
     RECT  5.1 49.043 6.648 50.579 ;
     RECT  3.936 50.195 3.96 50.771 ;
     RECT  5.1 50.579 6.216 52.837 ;
     RECT  4.224 52.837 6.216 54.613 ;
     RECT  4.224 54.613 6.36 56.197 ;
     RECT  3.888 56.197 6.36 57.059 ;
     RECT  3.888 57.059 6.216 58.117 ;
     RECT  3.696 58.117 6.216 58.501 ;
     RECT  7.8 48.515 8.112 58.501 ;
     RECT  3.696 58.501 8.112 58.835 ;
     RECT  3.984 58.835 8.112 59.315 ;
     RECT  4.032 59.315 8.112 59.795 ;
     RECT  4.032 59.795 6.216 60.661 ;
     RECT  7.8 59.795 8.112 62.101 ;
     RECT  3.936 60.661 6.216 62.197 ;
     RECT  7.8 62.101 8.376 62.197 ;
     RECT  0.288 61.093 0.312 62.725 ;
     RECT  3.936 62.197 8.376 62.819 ;
     RECT  0.192 62.725 0.312 63.011 ;
     RECT  4.752 62.819 8.376 64.355 ;
     RECT  0.288 63.011 0.312 64.547 ;
     RECT  4.848 64.355 8.376 65.411 ;
     RECT  4.848 65.411 6.216 65.509 ;
     RECT  4.56 65.509 6.216 66.179 ;
     RECT  4.848 66.179 6.216 66.611 ;
     RECT  5.1 66.611 6.216 67.765 ;
     RECT  7.8 65.411 8.376 67.765 ;
     RECT  5.1 67.765 8.376 68.627 ;
     RECT  5.1 68.627 5.688 71.749 ;
     RECT  7.008 68.627 8.376 71.749 ;
     RECT  5.1 71.749 8.376 71.939 ;
     RECT  5.1 71.939 8.112 72.851 ;
     RECT  2.4 50.195 2.712 72.853 ;
     RECT  5.1 72.851 5.688 74.053 ;
     RECT  6.72 72.851 8.112 74.053 ;
     RECT  5.1 74.053 8.112 74.293 ;
     RECT  2.4 72.853 3.528 75.781 ;
     RECT  4.896 74.293 8.112 75.781 ;
     RECT  2.4 75.781 8.112 76.067 ;
     RECT  3.792 76.067 8.112 77.555 ;
     RECT  3.792 77.555 6.12 78.613 ;
     RECT  7.104 77.555 8.112 78.613 ;
     RECT  3.792 78.613 8.112 79.283 ;
     RECT  2.4 76.067 2.712 79.957 ;
     RECT  3.792 79.283 3.816 79.957 ;
     RECT  2.4 79.957 3.816 80.003 ;
     RECT  4.992 79.283 8.112 80.387 ;
     RECT  5.1 80.387 8.112 80.435 ;
     RECT  5.1 80.435 5.928 82.021 ;
     RECT  2.4 80.003 3.576 82.163 ;
     RECT  4.896 82.021 5.928 82.691 ;
     RECT  4.896 82.691 5.688 83.267 ;
     RECT  3.936 84.325 3.96 85.091 ;
     RECT  5.1 83.267 5.688 85.141 ;
     RECT  7.104 80.435 8.112 85.619 ;
     RECT  4.8 85.141 5.688 86.005 ;
     RECT  4.8 86.005 6.264 86.195 ;
     RECT  5.1 86.195 6.264 86.629 ;
     RECT  7.8 85.619 8.112 86.629 ;
     RECT  5.1 86.629 8.112 86.867 ;
     RECT  3.888 86.485 3.912 90.517 ;
     RECT  5.1 86.867 5.688 90.517 ;
     RECT  7.152 86.867 8.112 90.563 ;
     RECT  3.888 90.517 5.688 90.899 ;
     RECT  4.704 90.899 5.688 91.619 ;
     RECT  5.1 91.619 5.688 92.821 ;
     RECT  7.632 90.563 8.112 93.539 ;
     RECT  5.1 92.821 6.648 94.355 ;
     RECT  2.4 82.163 2.712 97.209 ;
     RECT  7.8 93.539 8.112 97.209 ;
     RECT  10.5 2.151 10.812 97.209 ;
     RECT  13.2 2.151 13.512 97.209 ;
     RECT  15.9 2.151 16.212 97.209 ;
     RECT  18.6 2.151 18.912 97.209 ;
     RECT  21.3 2.151 21.612 97.209 ;
     RECT  24 2.151 24.312 97.209 ;
     RECT  26.7 2.151 27.012 97.209 ;
     RECT  29.4 2.151 29.712 97.209 ;
     RECT  32.1 2.151 32.412 97.209 ;
     RECT  2.4 97.209 2.52 97.223 ;
     RECT  5.1 94.355 5.688 97.223 ;
     RECT  7.8 97.209 7.92 97.223 ;
     RECT  10.5 97.209 10.62 97.223 ;
     RECT  13.2 97.209 13.32 97.223 ;
     RECT  15.9 97.209 16.02 97.223 ;
     RECT  18.6 97.209 18.72 97.223 ;
     RECT  21.3 97.209 21.42 97.223 ;
     RECT  24 97.209 24.12 97.223 ;
     RECT  26.7 97.209 26.82 97.223 ;
     RECT  29.4 97.209 29.52 97.223 ;
     RECT  32.1 97.209 32.22 97.223 ;
     RECT  5.664 97.223 5.688 99.251 ;
     RECT  5.928 6.805 7.248 7.475 ;
     RECT  5.412 8.579 5.928 9.061 ;
     RECT  3.432 9.061 4.512 9.205 ;
     RECT  5.412 9.061 7.152 9.925 ;
     RECT  2.712 9.251 3.792 11.893 ;
     RECT  6.12 9.925 7.152 10.883 ;
     RECT  3.816 11.267 5.1 11.939 ;
     RECT  3.48 11.939 5.1 13.045 ;
     RECT  5.412 12.179 6.12 13.573 ;
     RECT  4.008 13.045 5.1 13.667 ;
     RECT  5.412 13.573 7.152 13.621 ;
     RECT  6.12 13.621 7.152 15.443 ;
     RECT  3.48 13.667 5.1 14.339 ;
     RECT  4.32 14.339 5.1 14.485 ;
     RECT  4.32 14.485 4.704 15.061 ;
     RECT  6.12 15.443 6.264 16.357 ;
     RECT  6.264 17.605 7.296 19.141 ;
     RECT  3.432 20.051 4.464 24.083 ;
     RECT  6.216 23.845 7.488 27.061 ;
     RECT  3.432 24.083 4.992 25.045 ;
     RECT  3.432 25.045 4.416 26.291 ;
     RECT  6.648 27.251 7.68 29.123 ;
     RECT  6.648 29.123 7.8 32.437 ;
     RECT  3.24 30.709 4.512 31.427 ;
     RECT  2.712 34.213 4.032 38.677 ;
     RECT  4.056 34.213 5.1 35.845 ;
     RECT  6.216 37.619 7.392 38.435 ;
     RECT  2.856 38.677 4.032 39.251 ;
     RECT  2.712 39.251 4.032 42.181 ;
     RECT  6.744 42.037 7.8 44.051 ;
     RECT  2.712 42.181 3.984 45.155 ;
     RECT  4.008 42.707 5.1 45.155 ;
     RECT  6.216 47.317 7.392 47.845 ;
     RECT  6.648 48.515 7.8 50.579 ;
     RECT  4.272 49.043 5.1 49.381 ;
     RECT  3.96 49.381 5.1 50.771 ;
     RECT  2.712 50.195 3.936 50.771 ;
     RECT  2.712 52.837 4.224 56.197 ;
     RECT  6.36 54.613 7.8 57.059 ;
     RECT  2.712 56.197 3.888 58.117 ;
     RECT  6.216 57.059 7.8 58.501 ;
     RECT  2.712 58.117 3.696 58.835 ;
     RECT  2.712 58.835 3.984 59.315 ;
     RECT  2.712 59.315 4.032 60.661 ;
     RECT  2.712 60.661 3.936 62.819 ;
     RECT  4.752 64.355 4.848 65.509 ;
     RECT  5.688 68.627 7.008 71.749 ;
     RECT  5.688 72.851 6.72 74.053 ;
     RECT  3.528 74.293 4.896 75.781 ;
     RECT  2.712 76.067 3.792 79.957 ;
     RECT  6.12 77.555 7.104 78.613 ;
     RECT  3.816 79.283 4.992 80.003 ;
     RECT  3.576 80.003 4.992 80.387 ;
     RECT  3.576 80.387 5.1 82.021 ;
     RECT  5.928 80.435 7.104 82.691 ;
     RECT  3.576 82.021 4.896 82.163 ;
     RECT  5.688 82.691 7.104 85.619 ;
     RECT  4.896 83.267 5.1 84.325 ;
     RECT  2.712 84.325 3.936 85.091 ;
     RECT  3.96 84.325 5.1 85.091 ;
     RECT  2.712 85.091 5.1 85.141 ;
     RECT  2.712 85.141 4.8 86.195 ;
     RECT  5.688 85.619 7.8 86.005 ;
     RECT  6.264 86.005 7.8 86.629 ;
     RECT  2.712 86.195 5.1 86.485 ;
     RECT  2.712 86.485 3.888 90.899 ;
     RECT  3.912 86.485 5.1 90.517 ;
     RECT  5.688 86.867 7.152 90.563 ;
     RECT  6.648 92.821 7.632 93.539 ;
     RECT  6.648 93.539 7.8 94.355 ;
  END
END dsfd_hstnh_560
END LIBRARY
